# Copyright (c) 1993 - 2025 ARM Limited. All Rights Reserved.
# Use of this Software is subject to the terms and conditions of the
# applicable license agreement with ARM Limited.

# PhyVGen V 11.0.0-beta2
# ARM Version r3p1
# Creation Date: Fri Jan 31 07:31:40 2025


# Memory Configuration:
# ~~~~~~~~~~~~~~~~~~~~~
#  -PG_PINS_domain VDDCE -activity_factor 50 -atf off -back_biasing off
# -bit_blast off -bits 128 -bmux off -check_instname on -diodes on -drive 6
# -ema on -frequency 500 -instname sram128x128 -left_bus_delim "[" -mux 2 -mvt
# BASE -name_case lower -power_gating off -power_type otc -pwr_gnd_rename
# vddpe:VDDPE,vddce:VDDCE,vsse:VSSE -rcols 2 -redundancy off -retention on
# -right_bus_delim "]" -rrows 0 -ser none -single_domain_only on -site_def off
# -top_layer m5-m10 -vmin_assist on -words 128 -wp_size 1 -write_mask off
# -write_thru off -corners
# ffg_cbestt_0p88v_0p88v_0c,ffg_cbestt_0p88v_0p88v_125c,ffg_cbestt_0p88v_0p88v_m40c,ssg_cworstt_0p72v_0p72v_0c,ssg_cworstt_0p72v_0p72v_125c,ssg_cworstt_0p72v_0p72v_m40c,tt_typical_0p80v_0p80v_25c,tt_typical_0p80v_0p80v_85c
# 

VERSION 5.8 ;
BUSBITCHARS "[]" ;
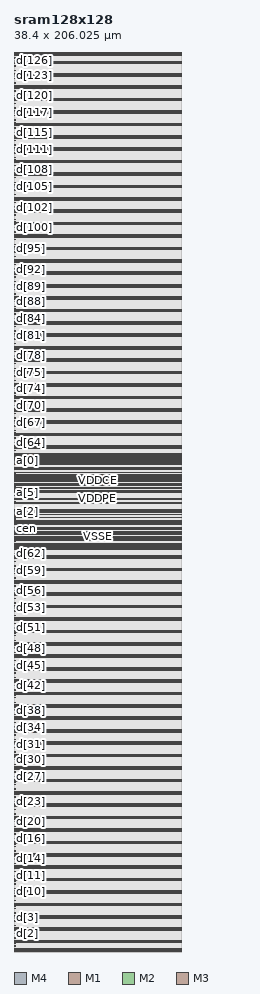
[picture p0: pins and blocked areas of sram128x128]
MACRO sram128x128
	FOREIGN sram128x128 0 0 ;
	SYMMETRY X Y ;
	SIZE 38.4 BY 206.025 ;
	CLASS BLOCK ;
	PIN VDDCE
		USE POWER ;
		DIRECTION INOUT ;
		PORT
			LAYER	M4 ;
			RECT	0 95.965 38.4 96.175 ;
		END

		PORT
			LAYER	M4 ;
			RECT	0 107.815 38.4 108.025 ;
		END

		PORT
			LAYER	M4 ;
			RECT	0 109.675 38.4 109.825 ;
		END

		PORT
			LAYER	M4 ;
			RECT	0 113.28 38.4 113.43 ;
		END

		PORT
			LAYER	M4 ;
			RECT	0 203.575 38.4 203.725 ;
		END

		PORT
			LAYER	M4 ;
			RECT	0 135.415 38.4 135.565 ;
		END

		PORT
			LAYER	M4 ;
			RECT	0 132.575 38.4 132.725 ;
		END

		PORT
			LAYER	M4 ;
			RECT	0 129.735 38.4 129.885 ;
		END

		PORT
			LAYER	M4 ;
			RECT	0 126.895 38.4 127.045 ;
		END

		PORT
			LAYER	M4 ;
			RECT	0 124.055 38.4 124.205 ;
		END

		PORT
			LAYER	M4 ;
			RECT	0 197.895 38.4 198.045 ;
		END

		PORT
			LAYER	M4 ;
			RECT	0 121.215 38.4 121.365 ;
		END

		PORT
			LAYER	M4 ;
			RECT	0 118.375 38.4 118.525 ;
		END

		PORT
			LAYER	M4 ;
			RECT	0 115.535 38.4 115.685 ;
		END

		PORT
			LAYER	M4 ;
			RECT	0 195.055 38.4 195.205 ;
		END

		PORT
			LAYER	M4 ;
			RECT	0 90.34 38.4 90.49 ;
		END

		PORT
			LAYER	M4 ;
			RECT	0 87.5 38.4 87.65 ;
		END

		PORT
			LAYER	M4 ;
			RECT	0 84.66 38.4 84.81 ;
		END

		PORT
			LAYER	M4 ;
			RECT	0 81.82 38.4 81.97 ;
		END

		PORT
			LAYER	M4 ;
			RECT	0 78.98 38.4 79.13 ;
		END

		PORT
			LAYER	M4 ;
			RECT	0 76.14 38.4 76.29 ;
		END

		PORT
			LAYER	M4 ;
			RECT	0 73.3 38.4 73.45 ;
		END

		PORT
			LAYER	M4 ;
			RECT	0 192.215 38.4 192.365 ;
		END

		PORT
			LAYER	M4 ;
			RECT	0 70.46 38.4 70.61 ;
		END

		PORT
			LAYER	M4 ;
			RECT	0 67.62 38.4 67.77 ;
		END

		PORT
			LAYER	M4 ;
			RECT	0 64.78 38.4 64.93 ;
		END

		PORT
			LAYER	M4 ;
			RECT	0 61.94 38.4 62.09 ;
		END

		PORT
			LAYER	M4 ;
			RECT	0 59.1 38.4 59.25 ;
		END

		PORT
			LAYER	M4 ;
			RECT	0 56.26 38.4 56.41 ;
		END

		PORT
			LAYER	M4 ;
			RECT	0 53.42 38.4 53.57 ;
		END

		PORT
			LAYER	M4 ;
			RECT	0 50.58 38.4 50.73 ;
		END

		PORT
			LAYER	M4 ;
			RECT	0 47.74 38.4 47.89 ;
		END

		PORT
			LAYER	M4 ;
			RECT	0 44.9 38.4 45.05 ;
		END

		PORT
			LAYER	M4 ;
			RECT	0 189.375 38.4 189.525 ;
		END

		PORT
			LAYER	M4 ;
			RECT	0 42.06 38.4 42.21 ;
		END

		PORT
			LAYER	M4 ;
			RECT	0 39.22 38.4 39.37 ;
		END

		PORT
			LAYER	M4 ;
			RECT	0 36.38 38.4 36.53 ;
		END

		PORT
			LAYER	M4 ;
			RECT	0 33.54 38.4 33.69 ;
		END

		PORT
			LAYER	M4 ;
			RECT	0 30.7 38.4 30.85 ;
		END

		PORT
			LAYER	M4 ;
			RECT	0 27.86 38.4 28.01 ;
		END

		PORT
			LAYER	M4 ;
			RECT	0 25.02 38.4 25.17 ;
		END

		PORT
			LAYER	M4 ;
			RECT	0 22.18 38.4 22.33 ;
		END

		PORT
			LAYER	M4 ;
			RECT	0 19.34 38.4 19.49 ;
		END

		PORT
			LAYER	M4 ;
			RECT	0 16.5 38.4 16.65 ;
		END

		PORT
			LAYER	M4 ;
			RECT	0 186.535 38.4 186.685 ;
		END

		PORT
			LAYER	M4 ;
			RECT	0 13.66 38.4 13.81 ;
		END

		PORT
			LAYER	M4 ;
			RECT	0 10.82 38.4 10.97 ;
		END

		PORT
			LAYER	M4 ;
			RECT	0 7.98 38.4 8.13 ;
		END

		PORT
			LAYER	M4 ;
			RECT	0 5.14 38.4 5.29 ;
		END

		PORT
			LAYER	M4 ;
			RECT	0 2.3 38.4 2.45 ;
		END

		PORT
			LAYER	M4 ;
			RECT	0 183.695 38.4 183.845 ;
		END

		PORT
			LAYER	M4 ;
			RECT	0 180.855 38.4 181.005 ;
		END

		PORT
			LAYER	M4 ;
			RECT	0 178.015 38.4 178.165 ;
		END

		PORT
			LAYER	M4 ;
			RECT	0 175.175 38.4 175.325 ;
		END

		PORT
			LAYER	M4 ;
			RECT	0 172.335 38.4 172.485 ;
		END

		PORT
			LAYER	M4 ;
			RECT	0 169.495 38.4 169.645 ;
		END

		PORT
			LAYER	M4 ;
			RECT	0 166.655 38.4 166.805 ;
		END

		PORT
			LAYER	M4 ;
			RECT	0 163.815 38.4 163.965 ;
		END

		PORT
			LAYER	M4 ;
			RECT	0 160.975 38.4 161.125 ;
		END

		PORT
			LAYER	M4 ;
			RECT	0 158.135 38.4 158.285 ;
		END

		PORT
			LAYER	M4 ;
			RECT	0 155.295 38.4 155.445 ;
		END

		PORT
			LAYER	M4 ;
			RECT	0 152.455 38.4 152.605 ;
		END

		PORT
			LAYER	M4 ;
			RECT	0 200.735 38.4 200.885 ;
		END

		PORT
			LAYER	M4 ;
			RECT	0 149.615 38.4 149.765 ;
		END

		PORT
			LAYER	M4 ;
			RECT	0 146.775 38.4 146.925 ;
		END

		PORT
			LAYER	M4 ;
			RECT	0 143.935 38.4 144.085 ;
		END

		PORT
			LAYER	M4 ;
			RECT	0 141.095 38.4 141.245 ;
		END

		PORT
			LAYER	M4 ;
			RECT	0 138.255 38.4 138.405 ;
		END

		PORT
			LAYER	M4 ;
			RECT	0 92.235 38.4 92.365 ;
		END

		PORT
			LAYER	M4 ;
			RECT	0 95.665 38.4 95.795 ;
		END

		PORT
			LAYER	M4 ;
			RECT	0 205.205 38.4 205.355 ;
		END

		PORT
			LAYER	M4 ;
			RECT	0 108.195 38.4 108.325 ;
		END

		PORT
			LAYER	M4 ;
			RECT	0 0.67 38.4 0.82 ;
		END

		PORT
			LAYER	M4 ;
			RECT	0 114.07 38.4 114.2 ;
		END

	END VDDCE

	PIN VDDPE
		USE POWER ;
		DIRECTION INOUT ;
		PORT
			LAYER	M4 ;
			RECT	0 94.255 38.4 94.405 ;
		END

		PORT
			LAYER	M4 ;
			RECT	0 94.625 38.4 94.835 ;
		END

		PORT
			LAYER	M4 ;
			RECT	0 98.15 38.4 98.36 ;
		END

		PORT
			LAYER	M4 ;
			RECT	0 98.625 38.4 98.835 ;
		END

		PORT
			LAYER	M4 ;
			RECT	0 100.04 38.4 100.25 ;
		END

		PORT
			LAYER	M4 ;
			RECT	0 101.185 38.4 101.335 ;
		END

		PORT
			LAYER	M4 ;
			RECT	0 103.6 38.4 103.81 ;
		END

		PORT
			LAYER	M4 ;
			RECT	0 105.16 38.4 105.37 ;
		END

		PORT
			LAYER	M4 ;
			RECT	0 106.02 38.4 106.23 ;
		END

		PORT
			LAYER	M4 ;
			RECT	0 109.13 38.4 109.34 ;
		END

		PORT
			LAYER	M4 ;
			RECT	0 112.11 38.4 112.32 ;
		END

		PORT
			LAYER	M4 ;
			RECT	0 112.485 38.4 112.695 ;
		END

		PORT
			LAYER	M4 ;
			RECT	0 203.345 38.4 203.495 ;
		END

		PORT
			LAYER	M4 ;
			RECT	0 135.185 38.4 135.335 ;
		END

		PORT
			LAYER	M4 ;
			RECT	0 132.345 38.4 132.495 ;
		END

		PORT
			LAYER	M4 ;
			RECT	0 129.505 38.4 129.655 ;
		END

		PORT
			LAYER	M4 ;
			RECT	0 126.665 38.4 126.815 ;
		END

		PORT
			LAYER	M4 ;
			RECT	0 123.825 38.4 123.975 ;
		END

		PORT
			LAYER	M4 ;
			RECT	0 120.985 38.4 121.135 ;
		END

		PORT
			LAYER	M4 ;
			RECT	0 118.145 38.4 118.295 ;
		END

		PORT
			LAYER	M4 ;
			RECT	0 115.305 38.4 115.455 ;
		END

		PORT
			LAYER	M4 ;
			RECT	0 197.665 38.4 197.815 ;
		END

		PORT
			LAYER	M4 ;
			RECT	0 194.825 38.4 194.975 ;
		END

		PORT
			LAYER	M4 ;
			RECT	0 90.57 38.4 90.72 ;
		END

		PORT
			LAYER	M4 ;
			RECT	0 87.73 38.4 87.88 ;
		END

		PORT
			LAYER	M4 ;
			RECT	0 84.89 38.4 85.04 ;
		END

		PORT
			LAYER	M4 ;
			RECT	0 82.05 38.4 82.2 ;
		END

		PORT
			LAYER	M4 ;
			RECT	0 79.21 38.4 79.36 ;
		END

		PORT
			LAYER	M4 ;
			RECT	0 76.37 38.4 76.52 ;
		END

		PORT
			LAYER	M4 ;
			RECT	0 73.53 38.4 73.68 ;
		END

		PORT
			LAYER	M4 ;
			RECT	0 70.69 38.4 70.84 ;
		END

		PORT
			LAYER	M4 ;
			RECT	0 67.85 38.4 68 ;
		END

		PORT
			LAYER	M4 ;
			RECT	0 191.985 38.4 192.135 ;
		END

		PORT
			LAYER	M4 ;
			RECT	0 65.01 38.4 65.16 ;
		END

		PORT
			LAYER	M4 ;
			RECT	0 62.17 38.4 62.32 ;
		END

		PORT
			LAYER	M4 ;
			RECT	0 59.33 38.4 59.48 ;
		END

		PORT
			LAYER	M4 ;
			RECT	0 56.49 38.4 56.64 ;
		END

		PORT
			LAYER	M4 ;
			RECT	0 53.65 38.4 53.8 ;
		END

		PORT
			LAYER	M4 ;
			RECT	0 50.81 38.4 50.96 ;
		END

		PORT
			LAYER	M4 ;
			RECT	0 47.97 38.4 48.12 ;
		END

		PORT
			LAYER	M4 ;
			RECT	0 45.13 38.4 45.28 ;
		END

		PORT
			LAYER	M4 ;
			RECT	0 42.29 38.4 42.44 ;
		END

		PORT
			LAYER	M4 ;
			RECT	0 39.45 38.4 39.6 ;
		END

		PORT
			LAYER	M4 ;
			RECT	0 189.145 38.4 189.295 ;
		END

		PORT
			LAYER	M4 ;
			RECT	0 36.61 38.4 36.76 ;
		END

		PORT
			LAYER	M4 ;
			RECT	0 33.77 38.4 33.92 ;
		END

		PORT
			LAYER	M4 ;
			RECT	0 30.93 38.4 31.08 ;
		END

		PORT
			LAYER	M4 ;
			RECT	0 28.09 38.4 28.24 ;
		END

		PORT
			LAYER	M4 ;
			RECT	0 25.25 38.4 25.4 ;
		END

		PORT
			LAYER	M4 ;
			RECT	0 22.41 38.4 22.56 ;
		END

		PORT
			LAYER	M4 ;
			RECT	0 19.57 38.4 19.72 ;
		END

		PORT
			LAYER	M4 ;
			RECT	0 16.73 38.4 16.88 ;
		END

		PORT
			LAYER	M4 ;
			RECT	0 13.89 38.4 14.04 ;
		END

		PORT
			LAYER	M4 ;
			RECT	0 11.05 38.4 11.2 ;
		END

		PORT
			LAYER	M4 ;
			RECT	0 186.305 38.4 186.455 ;
		END

		PORT
			LAYER	M4 ;
			RECT	0 8.21 38.4 8.36 ;
		END

		PORT
			LAYER	M4 ;
			RECT	0 5.37 38.4 5.52 ;
		END

		PORT
			LAYER	M4 ;
			RECT	0 2.53 38.4 2.68 ;
		END

		PORT
			LAYER	M4 ;
			RECT	0 183.465 38.4 183.615 ;
		END

		PORT
			LAYER	M4 ;
			RECT	0 180.625 38.4 180.775 ;
		END

		PORT
			LAYER	M4 ;
			RECT	0 177.785 38.4 177.935 ;
		END

		PORT
			LAYER	M4 ;
			RECT	0 174.945 38.4 175.095 ;
		END

		PORT
			LAYER	M4 ;
			RECT	0 172.105 38.4 172.255 ;
		END

		PORT
			LAYER	M4 ;
			RECT	0 169.265 38.4 169.415 ;
		END

		PORT
			LAYER	M4 ;
			RECT	0 166.425 38.4 166.575 ;
		END

		PORT
			LAYER	M4 ;
			RECT	0 163.585 38.4 163.735 ;
		END

		PORT
			LAYER	M4 ;
			RECT	0 160.745 38.4 160.895 ;
		END

		PORT
			LAYER	M4 ;
			RECT	0 157.905 38.4 158.055 ;
		END

		PORT
			LAYER	M4 ;
			RECT	0 155.065 38.4 155.215 ;
		END

		PORT
			LAYER	M4 ;
			RECT	0 152.225 38.4 152.375 ;
		END

		PORT
			LAYER	M4 ;
			RECT	0 149.385 38.4 149.535 ;
		END

		PORT
			LAYER	M4 ;
			RECT	0 146.545 38.4 146.695 ;
		END

		PORT
			LAYER	M4 ;
			RECT	0 143.705 38.4 143.855 ;
		END

		PORT
			LAYER	M4 ;
			RECT	0 200.505 38.4 200.655 ;
		END

		PORT
			LAYER	M4 ;
			RECT	0 140.865 38.4 141.015 ;
		END

		PORT
			LAYER	M4 ;
			RECT	0 138.025 38.4 138.175 ;
		END

		PORT
			LAYER	M4 ;
			RECT	0 205.705 38.4 205.855 ;
		END

		PORT
			LAYER	M4 ;
			RECT	0 92.655 38.4 92.785 ;
		END

		PORT
			LAYER	M4 ;
			RECT	0 97.125 38.4 97.255 ;
		END

		PORT
			LAYER	M4 ;
			RECT	0 0.17 38.4 0.32 ;
		END

		PORT
			LAYER	M4 ;
			RECT	0 105.5 38.4 105.63 ;
		END

		PORT
			LAYER	M4 ;
			RECT	0 113.65 38.4 113.78 ;
		END

	END VDDPE

	PIN VSSE
		USE GROUND ;
		DIRECTION INOUT ;
		PORT
			LAYER	M4 ;
			RECT	0 92.445 38.4 92.575 ;
		END

		PORT
			LAYER	M4 ;
			RECT	0 205.455 38.4 205.605 ;
		END

		PORT
			LAYER	M4 ;
			RECT	0 99.425 38.4 99.555 ;
		END

		PORT
			LAYER	M4 ;
			RECT	0 0.42 38.4 0.57 ;
		END

		PORT
			LAYER	M4 ;
			RECT	0 106.69 38.4 106.82 ;
		END

		PORT
			LAYER	M4 ;
			RECT	0 110.885 38.4 111.015 ;
		END

		PORT
			LAYER	M4 ;
			RECT	0 113.86 38.4 113.99 ;
		END

		PORT
			LAYER	M4 ;
			RECT	0 92.98 38.4 93.11 ;
		END

		PORT
			LAYER	M4 ;
			RECT	0 93.39 38.4 93.6 ;
		END

		PORT
			LAYER	M4 ;
			RECT	0 94.97 38.4 95.18 ;
		END

		PORT
			LAYER	M4 ;
			RECT	0 96.76 38.4 96.91 ;
		END

		PORT
			LAYER	M4 ;
			RECT	0 97.865 38.4 98.015 ;
		END

		PORT
			LAYER	M4 ;
			RECT	0 100.575 38.4 100.725 ;
		END

		PORT
			LAYER	M4 ;
			RECT	0 100.915 38.4 101.065 ;
		END

		PORT
			LAYER	M4 ;
			RECT	0 102.63 38.4 102.84 ;
		END

		PORT
			LAYER	M4 ;
			RECT	0 107.05 38.4 107.26 ;
		END

		PORT
			LAYER	M4 ;
			RECT	0 108.655 38.4 108.865 ;
		END

		PORT
			LAYER	M4 ;
			RECT	0 110.395 38.4 110.605 ;
		END

		PORT
			LAYER	M4 ;
			RECT	0 111.59 38.4 111.8 ;
		END

		PORT
			LAYER	M4 ;
			RECT	0 112.955 38.4 113.165 ;
		END

		PORT
			LAYER	M4 ;
			RECT	0 203.805 38.4 203.955 ;
		END

		PORT
			LAYER	M4 ;
			RECT	0 132.805 38.4 132.955 ;
		END

		PORT
			LAYER	M4 ;
			RECT	0 129.965 38.4 130.115 ;
		END

		PORT
			LAYER	M4 ;
			RECT	0 198.125 38.4 198.275 ;
		END

		PORT
			LAYER	M4 ;
			RECT	0 127.125 38.4 127.275 ;
		END

		PORT
			LAYER	M4 ;
			RECT	0 124.285 38.4 124.435 ;
		END

		PORT
			LAYER	M4 ;
			RECT	0 121.445 38.4 121.595 ;
		END

		PORT
			LAYER	M4 ;
			RECT	0 118.605 38.4 118.755 ;
		END

		PORT
			LAYER	M4 ;
			RECT	0 115.765 38.4 115.915 ;
		END

		PORT
			LAYER	M4 ;
			RECT	0 195.285 38.4 195.435 ;
		END

		PORT
			LAYER	M4 ;
			RECT	0 90.11 38.4 90.26 ;
		END

		PORT
			LAYER	M4 ;
			RECT	0 87.27 38.4 87.42 ;
		END

		PORT
			LAYER	M4 ;
			RECT	0 84.43 38.4 84.58 ;
		END

		PORT
			LAYER	M4 ;
			RECT	0 81.59 38.4 81.74 ;
		END

		PORT
			LAYER	M4 ;
			RECT	0 192.445 38.4 192.595 ;
		END

		PORT
			LAYER	M4 ;
			RECT	0 78.75 38.4 78.9 ;
		END

		PORT
			LAYER	M4 ;
			RECT	0 75.91 38.4 76.06 ;
		END

		PORT
			LAYER	M4 ;
			RECT	0 73.07 38.4 73.22 ;
		END

		PORT
			LAYER	M4 ;
			RECT	0 70.23 38.4 70.38 ;
		END

		PORT
			LAYER	M4 ;
			RECT	0 67.39 38.4 67.54 ;
		END

		PORT
			LAYER	M4 ;
			RECT	0 64.55 38.4 64.7 ;
		END

		PORT
			LAYER	M4 ;
			RECT	0 61.71 38.4 61.86 ;
		END

		PORT
			LAYER	M4 ;
			RECT	0 58.87 38.4 59.02 ;
		END

		PORT
			LAYER	M4 ;
			RECT	0 56.03 38.4 56.18 ;
		END

		PORT
			LAYER	M4 ;
			RECT	0 53.19 38.4 53.34 ;
		END

		PORT
			LAYER	M4 ;
			RECT	0 189.605 38.4 189.755 ;
		END

		PORT
			LAYER	M4 ;
			RECT	0 50.35 38.4 50.5 ;
		END

		PORT
			LAYER	M4 ;
			RECT	0 47.51 38.4 47.66 ;
		END

		PORT
			LAYER	M4 ;
			RECT	0 44.67 38.4 44.82 ;
		END

		PORT
			LAYER	M4 ;
			RECT	0 41.83 38.4 41.98 ;
		END

		PORT
			LAYER	M4 ;
			RECT	0 38.99 38.4 39.14 ;
		END

		PORT
			LAYER	M4 ;
			RECT	0 36.15 38.4 36.3 ;
		END

		PORT
			LAYER	M4 ;
			RECT	0 33.31 38.4 33.46 ;
		END

		PORT
			LAYER	M4 ;
			RECT	0 30.47 38.4 30.62 ;
		END

		PORT
			LAYER	M4 ;
			RECT	0 27.63 38.4 27.78 ;
		END

		PORT
			LAYER	M4 ;
			RECT	0 24.79 38.4 24.94 ;
		END

		PORT
			LAYER	M4 ;
			RECT	0 186.765 38.4 186.915 ;
		END

		PORT
			LAYER	M4 ;
			RECT	0 21.95 38.4 22.1 ;
		END

		PORT
			LAYER	M4 ;
			RECT	0 19.11 38.4 19.26 ;
		END

		PORT
			LAYER	M4 ;
			RECT	0 16.27 38.4 16.42 ;
		END

		PORT
			LAYER	M4 ;
			RECT	0 13.43 38.4 13.58 ;
		END

		PORT
			LAYER	M4 ;
			RECT	0 10.59 38.4 10.74 ;
		END

		PORT
			LAYER	M4 ;
			RECT	0 7.75 38.4 7.9 ;
		END

		PORT
			LAYER	M4 ;
			RECT	0 4.91 38.4 5.06 ;
		END

		PORT
			LAYER	M4 ;
			RECT	0 2.07 38.4 2.22 ;
		END

		PORT
			LAYER	M4 ;
			RECT	0 183.925 38.4 184.075 ;
		END

		PORT
			LAYER	M4 ;
			RECT	0 181.085 38.4 181.235 ;
		END

		PORT
			LAYER	M4 ;
			RECT	0 178.245 38.4 178.395 ;
		END

		PORT
			LAYER	M4 ;
			RECT	0 175.405 38.4 175.555 ;
		END

		PORT
			LAYER	M4 ;
			RECT	0 172.565 38.4 172.715 ;
		END

		PORT
			LAYER	M4 ;
			RECT	0 169.725 38.4 169.875 ;
		END

		PORT
			LAYER	M4 ;
			RECT	0 166.885 38.4 167.035 ;
		END

		PORT
			LAYER	M4 ;
			RECT	0 164.045 38.4 164.195 ;
		END

		PORT
			LAYER	M4 ;
			RECT	0 161.205 38.4 161.355 ;
		END

		PORT
			LAYER	M4 ;
			RECT	0 158.365 38.4 158.515 ;
		END

		PORT
			LAYER	M4 ;
			RECT	0 200.965 38.4 201.115 ;
		END

		PORT
			LAYER	M4 ;
			RECT	0 155.525 38.4 155.675 ;
		END

		PORT
			LAYER	M4 ;
			RECT	0 152.685 38.4 152.835 ;
		END

		PORT
			LAYER	M4 ;
			RECT	0 149.845 38.4 149.995 ;
		END

		PORT
			LAYER	M4 ;
			RECT	0 147.005 38.4 147.155 ;
		END

		PORT
			LAYER	M4 ;
			RECT	0 144.165 38.4 144.315 ;
		END

		PORT
			LAYER	M4 ;
			RECT	0 141.325 38.4 141.475 ;
		END

		PORT
			LAYER	M4 ;
			RECT	0 138.485 38.4 138.635 ;
		END

		PORT
			LAYER	M4 ;
			RECT	0 135.645 38.4 135.795 ;
		END

	END VSSE

	PIN a[0]
		USE SIGNAL ;
		DIRECTION INPUT ;
		SHAPE ABUTMENT ;
		PORT
			LAYER	M1 ;
			RECT	0 112.385 0.25 112.485 ;
			LAYER	M2 ;
			RECT	0 112.385 0.25 112.485 ;
			LAYER	M3 ;
			RECT	0 112.385 0.25 112.485 ;
		END

		ANTENNAGATEAREA 0.014 ;
		ANTENNADIFFAREA 0.018 ;
		ANTENNAPARTIALMETALAREA 0.025 ;
	END a[0]

	PIN a[1]
		USE SIGNAL ;
		DIRECTION INPUT ;
		SHAPE ABUTMENT ;
		PORT
			LAYER	M1 ;
			RECT	0 100.49 0.25 100.59 ;
			LAYER	M2 ;
			RECT	0 100.49 0.25 100.59 ;
			LAYER	M3 ;
			RECT	0 100.49 0.25 100.59 ;
		END

		ANTENNAGATEAREA 0.014 ;
		ANTENNADIFFAREA 0.018 ;
		ANTENNAPARTIALMETALAREA 0.025 ;
	END a[1]

	PIN a[2]
		USE SIGNAL ;
		DIRECTION INPUT ;
		SHAPE ABUTMENT ;
		PORT
			LAYER	M1 ;
			RECT	0 100.89 0.25 100.99 ;
			LAYER	M2 ;
			RECT	0 100.89 0.25 100.99 ;
			LAYER	M3 ;
			RECT	0 100.89 0.25 100.99 ;
		END

		ANTENNAGATEAREA 0.014 ;
		ANTENNADIFFAREA 0.018 ;
		ANTENNAPARTIALMETALAREA 0.025 ;
	END a[2]

	PIN a[3]
		USE SIGNAL ;
		DIRECTION INPUT ;
		SHAPE ABUTMENT ;
		PORT
			LAYER	M1 ;
			RECT	0 102.8 0.25 102.9 ;
			LAYER	M2 ;
			RECT	0 102.8 0.25 102.9 ;
			LAYER	M3 ;
			RECT	0 102.8 0.25 102.9 ;
		END

		ANTENNAGATEAREA 0.014 ;
		ANTENNADIFFAREA 0.018 ;
		ANTENNAPARTIALMETALAREA 0.025 ;
	END a[3]

	PIN a[4]
		USE SIGNAL ;
		DIRECTION INPUT ;
		SHAPE ABUTMENT ;
		PORT
			LAYER	M1 ;
			RECT	0 103.13 0.25 103.23 ;
			LAYER	M2 ;
			RECT	0 103.13 0.25 103.23 ;
			LAYER	M3 ;
			RECT	0 103.13 0.25 103.23 ;
		END

		ANTENNAGATEAREA 0.014 ;
		ANTENNADIFFAREA 0.018 ;
		ANTENNAPARTIALMETALAREA 0.025 ;
	END a[4]

	PIN a[5]
		USE SIGNAL ;
		DIRECTION INPUT ;
		SHAPE ABUTMENT ;
		PORT
			LAYER	M1 ;
			RECT	0 105.235 0.25 105.335 ;
			LAYER	M2 ;
			RECT	0 105.235 0.25 105.335 ;
			LAYER	M3 ;
			RECT	0 105.235 0.25 105.335 ;
		END

		ANTENNAGATEAREA 0.014 ;
		ANTENNADIFFAREA 0.018 ;
		ANTENNAPARTIALMETALAREA 0.025 ;
	END a[5]

	PIN a[6]
		USE SIGNAL ;
		DIRECTION INPUT ;
		SHAPE ABUTMENT ;
		PORT
			LAYER	M1 ;
			RECT	0 106.505 0.25 106.605 ;
			LAYER	M2 ;
			RECT	0 106.505 0.25 106.605 ;
			LAYER	M3 ;
			RECT	0 106.505 0.25 106.605 ;
		END

		ANTENNAGATEAREA 0.014 ;
		ANTENNADIFFAREA 0.018 ;
		ANTENNAPARTIALMETALAREA 0.025 ;
	END a[6]

	PIN cen
		USE SIGNAL ;
		DIRECTION INPUT ;
		SHAPE ABUTMENT ;
		PORT
			LAYER	M1 ;
			RECT	0 96.9 0.25 97 ;
			LAYER	M2 ;
			RECT	0 96.9 0.25 97 ;
			LAYER	M3 ;
			RECT	0 96.9 0.25 97 ;
		END

		ANTENNAGATEAREA 0.014 ;
		ANTENNADIFFAREA 0.018 ;
		ANTENNAPARTIALMETALAREA 0.025 ;
	END cen

	PIN clk
		USE SIGNAL ;
		DIRECTION INPUT ;
		SHAPE ABUTMENT ;
		PORT
			LAYER	M1 ;
			RECT	0 96.51 0.25 96.61 ;
			LAYER	M2 ;
			RECT	0 96.51 0.25 96.61 ;
			LAYER	M3 ;
			RECT	0 96.51 0.25 96.61 ;
			LAYER	M4 ;
			RECT	0 96.51 0.25 96.61 ;
		END

		ANTENNAGATEAREA 0.014 ;
		ANTENNADIFFAREA 0.018 ;
		ANTENNAPARTIALMETALAREA 0.025 ;
	END clk

	PIN d[0]
		USE SIGNAL ;
		DIRECTION INPUT ;
		SHAPE ABUTMENT ;
		PORT
			LAYER	M1 ;
			RECT	0 1.365 0.25 1.465 ;
			LAYER	M2 ;
			RECT	0 1.365 0.25 1.465 ;
			LAYER	M3 ;
			RECT	0 1.365 0.25 1.465 ;
		END

		ANTENNAGATEAREA 0.014 ;
		ANTENNADIFFAREA 0.018 ;
		ANTENNAPARTIALMETALAREA 0.025 ;
	END d[0]

	PIN d[100]
		USE SIGNAL ;
		DIRECTION INPUT ;
		SHAPE ABUTMENT ;
		PORT
			LAYER	M1 ;
			RECT	0 165.85 0.25 165.95 ;
			LAYER	M2 ;
			RECT	0 165.85 0.25 165.95 ;
			LAYER	M3 ;
			RECT	0 165.85 0.25 165.95 ;
		END

		ANTENNAGATEAREA 0.014 ;
		ANTENNADIFFAREA 0.018 ;
		ANTENNAPARTIALMETALAREA 0.025 ;
	END d[100]

	PIN d[101]
		USE SIGNAL ;
		DIRECTION INPUT ;
		SHAPE ABUTMENT ;
		PORT
			LAYER	M1 ;
			RECT	0 167.64 0.25 167.74 ;
			LAYER	M2 ;
			RECT	0 167.64 0.25 167.74 ;
			LAYER	M3 ;
			RECT	0 167.64 0.25 167.74 ;
		END

		ANTENNAGATEAREA 0.014 ;
		ANTENNADIFFAREA 0.018 ;
		ANTENNAPARTIALMETALAREA 0.025 ;
	END d[101]

	PIN d[102]
		USE SIGNAL ;
		DIRECTION INPUT ;
		SHAPE ABUTMENT ;
		PORT
			LAYER	M1 ;
			RECT	0 168.69 0.25 168.79 ;
			LAYER	M2 ;
			RECT	0 168.69 0.25 168.79 ;
			LAYER	M3 ;
			RECT	0 168.69 0.25 168.79 ;
		END

		ANTENNAGATEAREA 0.014 ;
		ANTENNADIFFAREA 0.018 ;
		ANTENNAPARTIALMETALAREA 0.025 ;
	END d[102]

	PIN d[103]
		USE SIGNAL ;
		DIRECTION INPUT ;
		SHAPE ABUTMENT ;
		PORT
			LAYER	M1 ;
			RECT	0 170.48 0.25 170.58 ;
			LAYER	M2 ;
			RECT	0 170.48 0.25 170.58 ;
			LAYER	M3 ;
			RECT	0 170.48 0.25 170.58 ;
		END

		ANTENNAGATEAREA 0.014 ;
		ANTENNADIFFAREA 0.018 ;
		ANTENNAPARTIALMETALAREA 0.025 ;
	END d[103]

	PIN d[104]
		USE SIGNAL ;
		DIRECTION INPUT ;
		SHAPE ABUTMENT ;
		PORT
			LAYER	M1 ;
			RECT	0 171.53 0.25 171.63 ;
			LAYER	M2 ;
			RECT	0 171.53 0.25 171.63 ;
			LAYER	M3 ;
			RECT	0 171.53 0.25 171.63 ;
		END

		ANTENNAGATEAREA 0.014 ;
		ANTENNADIFFAREA 0.018 ;
		ANTENNAPARTIALMETALAREA 0.025 ;
	END d[104]

	PIN d[105]
		USE SIGNAL ;
		DIRECTION INPUT ;
		SHAPE ABUTMENT ;
		PORT
			LAYER	M1 ;
			RECT	0 173.32 0.25 173.42 ;
			LAYER	M2 ;
			RECT	0 173.32 0.25 173.42 ;
			LAYER	M3 ;
			RECT	0 173.32 0.25 173.42 ;
		END

		ANTENNAGATEAREA 0.014 ;
		ANTENNADIFFAREA 0.018 ;
		ANTENNAPARTIALMETALAREA 0.025 ;
	END d[105]

	PIN d[106]
		USE SIGNAL ;
		DIRECTION INPUT ;
		SHAPE ABUTMENT ;
		PORT
			LAYER	M1 ;
			RECT	0 174.37 0.25 174.47 ;
			LAYER	M2 ;
			RECT	0 174.37 0.25 174.47 ;
			LAYER	M3 ;
			RECT	0 174.37 0.25 174.47 ;
		END

		ANTENNAGATEAREA 0.014 ;
		ANTENNADIFFAREA 0.018 ;
		ANTENNAPARTIALMETALAREA 0.025 ;
	END d[106]

	PIN d[107]
		USE SIGNAL ;
		DIRECTION INPUT ;
		SHAPE ABUTMENT ;
		PORT
			LAYER	M1 ;
			RECT	0 176.16 0.25 176.26 ;
			LAYER	M2 ;
			RECT	0 176.16 0.25 176.26 ;
			LAYER	M3 ;
			RECT	0 176.16 0.25 176.26 ;
		END

		ANTENNAGATEAREA 0.014 ;
		ANTENNADIFFAREA 0.018 ;
		ANTENNAPARTIALMETALAREA 0.025 ;
	END d[107]

	PIN d[108]
		USE SIGNAL ;
		DIRECTION INPUT ;
		SHAPE ABUTMENT ;
		PORT
			LAYER	M1 ;
			RECT	0 177.21 0.25 177.31 ;
			LAYER	M2 ;
			RECT	0 177.21 0.25 177.31 ;
			LAYER	M3 ;
			RECT	0 177.21 0.25 177.31 ;
		END

		ANTENNAGATEAREA 0.014 ;
		ANTENNADIFFAREA 0.018 ;
		ANTENNAPARTIALMETALAREA 0.025 ;
	END d[108]

	PIN d[109]
		USE SIGNAL ;
		DIRECTION INPUT ;
		SHAPE ABUTMENT ;
		PORT
			LAYER	M1 ;
			RECT	0 179 0.25 179.1 ;
			LAYER	M2 ;
			RECT	0 179 0.25 179.1 ;
			LAYER	M3 ;
			RECT	0 179 0.25 179.1 ;
		END

		ANTENNAGATEAREA 0.014 ;
		ANTENNADIFFAREA 0.018 ;
		ANTENNAPARTIALMETALAREA 0.025 ;
	END d[109]

	PIN d[10]
		USE SIGNAL ;
		DIRECTION INPUT ;
		SHAPE ABUTMENT ;
		PORT
			LAYER	M1 ;
			RECT	0 15.565 0.25 15.665 ;
			LAYER	M2 ;
			RECT	0 15.565 0.25 15.665 ;
			LAYER	M3 ;
			RECT	0 15.565 0.25 15.665 ;
		END

		ANTENNAGATEAREA 0.014 ;
		ANTENNADIFFAREA 0.018 ;
		ANTENNAPARTIALMETALAREA 0.025 ;
	END d[10]

	PIN d[110]
		USE SIGNAL ;
		DIRECTION INPUT ;
		SHAPE ABUTMENT ;
		PORT
			LAYER	M1 ;
			RECT	0 180.05 0.25 180.15 ;
			LAYER	M2 ;
			RECT	0 180.05 0.25 180.15 ;
			LAYER	M3 ;
			RECT	0 180.05 0.25 180.15 ;
		END

		ANTENNAGATEAREA 0.014 ;
		ANTENNADIFFAREA 0.018 ;
		ANTENNAPARTIALMETALAREA 0.025 ;
	END d[110]

	PIN d[111]
		USE SIGNAL ;
		DIRECTION INPUT ;
		SHAPE ABUTMENT ;
		PORT
			LAYER	M1 ;
			RECT	0 181.84 0.25 181.94 ;
			LAYER	M2 ;
			RECT	0 181.84 0.25 181.94 ;
			LAYER	M3 ;
			RECT	0 181.84 0.25 181.94 ;
		END

		ANTENNAGATEAREA 0.014 ;
		ANTENNADIFFAREA 0.018 ;
		ANTENNAPARTIALMETALAREA 0.025 ;
	END d[111]

	PIN d[112]
		USE SIGNAL ;
		DIRECTION INPUT ;
		SHAPE ABUTMENT ;
		PORT
			LAYER	M1 ;
			RECT	0 182.89 0.25 182.99 ;
			LAYER	M2 ;
			RECT	0 182.89 0.25 182.99 ;
			LAYER	M3 ;
			RECT	0 182.89 0.25 182.99 ;
		END

		ANTENNAGATEAREA 0.014 ;
		ANTENNADIFFAREA 0.018 ;
		ANTENNAPARTIALMETALAREA 0.025 ;
	END d[112]

	PIN d[113]
		USE SIGNAL ;
		DIRECTION INPUT ;
		SHAPE ABUTMENT ;
		PORT
			LAYER	M1 ;
			RECT	0 184.68 0.25 184.78 ;
			LAYER	M2 ;
			RECT	0 184.68 0.25 184.78 ;
			LAYER	M3 ;
			RECT	0 184.68 0.25 184.78 ;
		END

		ANTENNAGATEAREA 0.014 ;
		ANTENNADIFFAREA 0.018 ;
		ANTENNAPARTIALMETALAREA 0.025 ;
	END d[113]

	PIN d[114]
		USE SIGNAL ;
		DIRECTION INPUT ;
		SHAPE ABUTMENT ;
		PORT
			LAYER	M1 ;
			RECT	0 185.73 0.25 185.83 ;
			LAYER	M2 ;
			RECT	0 185.73 0.25 185.83 ;
			LAYER	M3 ;
			RECT	0 185.73 0.25 185.83 ;
		END

		ANTENNAGATEAREA 0.014 ;
		ANTENNADIFFAREA 0.018 ;
		ANTENNAPARTIALMETALAREA 0.025 ;
	END d[114]

	PIN d[115]
		USE SIGNAL ;
		DIRECTION INPUT ;
		SHAPE ABUTMENT ;
		PORT
			LAYER	M1 ;
			RECT	0 187.52 0.25 187.62 ;
			LAYER	M2 ;
			RECT	0 187.52 0.25 187.62 ;
			LAYER	M3 ;
			RECT	0 187.52 0.25 187.62 ;
		END

		ANTENNAGATEAREA 0.014 ;
		ANTENNADIFFAREA 0.018 ;
		ANTENNAPARTIALMETALAREA 0.025 ;
	END d[115]

	PIN d[116]
		USE SIGNAL ;
		DIRECTION INPUT ;
		SHAPE ABUTMENT ;
		PORT
			LAYER	M1 ;
			RECT	0 188.57 0.25 188.67 ;
			LAYER	M2 ;
			RECT	0 188.57 0.25 188.67 ;
			LAYER	M3 ;
			RECT	0 188.57 0.25 188.67 ;
		END

		ANTENNAGATEAREA 0.014 ;
		ANTENNADIFFAREA 0.018 ;
		ANTENNAPARTIALMETALAREA 0.025 ;
	END d[116]

	PIN d[117]
		USE SIGNAL ;
		DIRECTION INPUT ;
		SHAPE ABUTMENT ;
		PORT
			LAYER	M1 ;
			RECT	0 190.36 0.25 190.46 ;
			LAYER	M2 ;
			RECT	0 190.36 0.25 190.46 ;
			LAYER	M3 ;
			RECT	0 190.36 0.25 190.46 ;
		END

		ANTENNAGATEAREA 0.014 ;
		ANTENNADIFFAREA 0.018 ;
		ANTENNAPARTIALMETALAREA 0.025 ;
	END d[117]

	PIN d[118]
		USE SIGNAL ;
		DIRECTION INPUT ;
		SHAPE ABUTMENT ;
		PORT
			LAYER	M1 ;
			RECT	0 191.41 0.25 191.51 ;
			LAYER	M2 ;
			RECT	0 191.41 0.25 191.51 ;
			LAYER	M3 ;
			RECT	0 191.41 0.25 191.51 ;
		END

		ANTENNAGATEAREA 0.014 ;
		ANTENNADIFFAREA 0.018 ;
		ANTENNAPARTIALMETALAREA 0.025 ;
	END d[118]

	PIN d[119]
		USE SIGNAL ;
		DIRECTION INPUT ;
		SHAPE ABUTMENT ;
		PORT
			LAYER	M1 ;
			RECT	0 193.2 0.25 193.3 ;
			LAYER	M2 ;
			RECT	0 193.2 0.25 193.3 ;
			LAYER	M3 ;
			RECT	0 193.2 0.25 193.3 ;
		END

		ANTENNAGATEAREA 0.014 ;
		ANTENNADIFFAREA 0.018 ;
		ANTENNAPARTIALMETALAREA 0.025 ;
	END d[119]

	PIN d[11]
		USE SIGNAL ;
		DIRECTION INPUT ;
		SHAPE ABUTMENT ;
		PORT
			LAYER	M1 ;
			RECT	0 17.355 0.25 17.455 ;
			LAYER	M2 ;
			RECT	0 17.355 0.25 17.455 ;
			LAYER	M3 ;
			RECT	0 17.355 0.25 17.455 ;
		END

		ANTENNAGATEAREA 0.014 ;
		ANTENNADIFFAREA 0.018 ;
		ANTENNAPARTIALMETALAREA 0.025 ;
	END d[11]

	PIN d[120]
		USE SIGNAL ;
		DIRECTION INPUT ;
		SHAPE ABUTMENT ;
		PORT
			LAYER	M1 ;
			RECT	0 194.25 0.25 194.35 ;
			LAYER	M2 ;
			RECT	0 194.25 0.25 194.35 ;
			LAYER	M3 ;
			RECT	0 194.25 0.25 194.35 ;
		END

		ANTENNAGATEAREA 0.014 ;
		ANTENNADIFFAREA 0.018 ;
		ANTENNAPARTIALMETALAREA 0.025 ;
	END d[120]

	PIN d[121]
		USE SIGNAL ;
		DIRECTION INPUT ;
		SHAPE ABUTMENT ;
		PORT
			LAYER	M1 ;
			RECT	0 196.04 0.25 196.14 ;
			LAYER	M2 ;
			RECT	0 196.04 0.25 196.14 ;
			LAYER	M3 ;
			RECT	0 196.04 0.25 196.14 ;
		END

		ANTENNAGATEAREA 0.014 ;
		ANTENNADIFFAREA 0.018 ;
		ANTENNAPARTIALMETALAREA 0.025 ;
	END d[121]

	PIN d[122]
		USE SIGNAL ;
		DIRECTION INPUT ;
		SHAPE ABUTMENT ;
		PORT
			LAYER	M1 ;
			RECT	0 197.09 0.25 197.19 ;
			LAYER	M2 ;
			RECT	0 197.09 0.25 197.19 ;
			LAYER	M3 ;
			RECT	0 197.09 0.25 197.19 ;
		END

		ANTENNAGATEAREA 0.014 ;
		ANTENNADIFFAREA 0.018 ;
		ANTENNAPARTIALMETALAREA 0.025 ;
	END d[122]

	PIN d[123]
		USE SIGNAL ;
		DIRECTION INPUT ;
		SHAPE ABUTMENT ;
		PORT
			LAYER	M1 ;
			RECT	0 198.88 0.25 198.98 ;
			LAYER	M2 ;
			RECT	0 198.88 0.25 198.98 ;
			LAYER	M3 ;
			RECT	0 198.88 0.25 198.98 ;
		END

		ANTENNAGATEAREA 0.014 ;
		ANTENNADIFFAREA 0.018 ;
		ANTENNAPARTIALMETALAREA 0.025 ;
	END d[123]

	PIN d[124]
		USE SIGNAL ;
		DIRECTION INPUT ;
		SHAPE ABUTMENT ;
		PORT
			LAYER	M1 ;
			RECT	0 199.93 0.25 200.03 ;
			LAYER	M2 ;
			RECT	0 199.93 0.25 200.03 ;
			LAYER	M3 ;
			RECT	0 199.93 0.25 200.03 ;
		END

		ANTENNAGATEAREA 0.014 ;
		ANTENNADIFFAREA 0.018 ;
		ANTENNAPARTIALMETALAREA 0.025 ;
	END d[124]

	PIN d[125]
		USE SIGNAL ;
		DIRECTION INPUT ;
		SHAPE ABUTMENT ;
		PORT
			LAYER	M1 ;
			RECT	0 201.72 0.25 201.82 ;
			LAYER	M2 ;
			RECT	0 201.72 0.25 201.82 ;
			LAYER	M3 ;
			RECT	0 201.72 0.25 201.82 ;
		END

		ANTENNAGATEAREA 0.014 ;
		ANTENNADIFFAREA 0.018 ;
		ANTENNAPARTIALMETALAREA 0.025 ;
	END d[125]

	PIN d[126]
		USE SIGNAL ;
		DIRECTION INPUT ;
		SHAPE ABUTMENT ;
		PORT
			LAYER	M1 ;
			RECT	0 202.77 0.25 202.87 ;
			LAYER	M2 ;
			RECT	0 202.77 0.25 202.87 ;
			LAYER	M3 ;
			RECT	0 202.77 0.25 202.87 ;
		END

		ANTENNAGATEAREA 0.014 ;
		ANTENNADIFFAREA 0.018 ;
		ANTENNAPARTIALMETALAREA 0.025 ;
	END d[126]

	PIN d[127]
		USE SIGNAL ;
		DIRECTION INPUT ;
		SHAPE ABUTMENT ;
		PORT
			LAYER	M1 ;
			RECT	0 204.56 0.25 204.66 ;
			LAYER	M2 ;
			RECT	0 204.56 0.25 204.66 ;
			LAYER	M3 ;
			RECT	0 204.56 0.25 204.66 ;
		END

		ANTENNAGATEAREA 0.014 ;
		ANTENNADIFFAREA 0.018 ;
		ANTENNAPARTIALMETALAREA 0.025 ;
	END d[127]

	PIN d[12]
		USE SIGNAL ;
		DIRECTION INPUT ;
		SHAPE ABUTMENT ;
		PORT
			LAYER	M1 ;
			RECT	0 18.405 0.25 18.505 ;
			LAYER	M2 ;
			RECT	0 18.405 0.25 18.505 ;
			LAYER	M3 ;
			RECT	0 18.405 0.25 18.505 ;
		END

		ANTENNAGATEAREA 0.014 ;
		ANTENNADIFFAREA 0.018 ;
		ANTENNAPARTIALMETALAREA 0.025 ;
	END d[12]

	PIN d[13]
		USE SIGNAL ;
		DIRECTION INPUT ;
		SHAPE ABUTMENT ;
		PORT
			LAYER	M1 ;
			RECT	0 20.195 0.25 20.295 ;
			LAYER	M2 ;
			RECT	0 20.195 0.25 20.295 ;
			LAYER	M3 ;
			RECT	0 20.195 0.25 20.295 ;
		END

		ANTENNAGATEAREA 0.014 ;
		ANTENNADIFFAREA 0.018 ;
		ANTENNAPARTIALMETALAREA 0.025 ;
	END d[13]

	PIN d[14]
		USE SIGNAL ;
		DIRECTION INPUT ;
		SHAPE ABUTMENT ;
		PORT
			LAYER	M1 ;
			RECT	0 21.245 0.25 21.345 ;
			LAYER	M2 ;
			RECT	0 21.245 0.25 21.345 ;
			LAYER	M3 ;
			RECT	0 21.245 0.25 21.345 ;
		END

		ANTENNAGATEAREA 0.014 ;
		ANTENNADIFFAREA 0.018 ;
		ANTENNAPARTIALMETALAREA 0.025 ;
	END d[14]

	PIN d[15]
		USE SIGNAL ;
		DIRECTION INPUT ;
		SHAPE ABUTMENT ;
		PORT
			LAYER	M1 ;
			RECT	0 23.035 0.25 23.135 ;
			LAYER	M2 ;
			RECT	0 23.035 0.25 23.135 ;
			LAYER	M3 ;
			RECT	0 23.035 0.25 23.135 ;
		END

		ANTENNAGATEAREA 0.014 ;
		ANTENNADIFFAREA 0.018 ;
		ANTENNAPARTIALMETALAREA 0.025 ;
	END d[15]

	PIN d[16]
		USE SIGNAL ;
		DIRECTION INPUT ;
		SHAPE ABUTMENT ;
		PORT
			LAYER	M1 ;
			RECT	0 24.085 0.25 24.185 ;
			LAYER	M2 ;
			RECT	0 24.085 0.25 24.185 ;
			LAYER	M3 ;
			RECT	0 24.085 0.25 24.185 ;
		END

		ANTENNAGATEAREA 0.014 ;
		ANTENNADIFFAREA 0.018 ;
		ANTENNAPARTIALMETALAREA 0.025 ;
	END d[16]

	PIN d[17]
		USE SIGNAL ;
		DIRECTION INPUT ;
		SHAPE ABUTMENT ;
		PORT
			LAYER	M1 ;
			RECT	0 25.875 0.25 25.975 ;
			LAYER	M2 ;
			RECT	0 25.875 0.25 25.975 ;
			LAYER	M3 ;
			RECT	0 25.875 0.25 25.975 ;
		END

		ANTENNAGATEAREA 0.014 ;
		ANTENNADIFFAREA 0.018 ;
		ANTENNAPARTIALMETALAREA 0.025 ;
	END d[17]

	PIN d[18]
		USE SIGNAL ;
		DIRECTION INPUT ;
		SHAPE ABUTMENT ;
		PORT
			LAYER	M1 ;
			RECT	0 26.925 0.25 27.025 ;
			LAYER	M2 ;
			RECT	0 26.925 0.25 27.025 ;
			LAYER	M3 ;
			RECT	0 26.925 0.25 27.025 ;
		END

		ANTENNAGATEAREA 0.014 ;
		ANTENNADIFFAREA 0.018 ;
		ANTENNAPARTIALMETALAREA 0.025 ;
	END d[18]

	PIN d[19]
		USE SIGNAL ;
		DIRECTION INPUT ;
		SHAPE ABUTMENT ;
		PORT
			LAYER	M1 ;
			RECT	0 28.715 0.25 28.815 ;
			LAYER	M2 ;
			RECT	0 28.715 0.25 28.815 ;
			LAYER	M3 ;
			RECT	0 28.715 0.25 28.815 ;
		END

		ANTENNAGATEAREA 0.014 ;
		ANTENNADIFFAREA 0.018 ;
		ANTENNAPARTIALMETALAREA 0.025 ;
	END d[19]

	PIN d[1]
		USE SIGNAL ;
		DIRECTION INPUT ;
		SHAPE ABUTMENT ;
		PORT
			LAYER	M1 ;
			RECT	0 3.155 0.25 3.255 ;
			LAYER	M2 ;
			RECT	0 3.155 0.25 3.255 ;
			LAYER	M3 ;
			RECT	0 3.155 0.25 3.255 ;
		END

		ANTENNAGATEAREA 0.014 ;
		ANTENNADIFFAREA 0.018 ;
		ANTENNAPARTIALMETALAREA 0.025 ;
	END d[1]

	PIN d[20]
		USE SIGNAL ;
		DIRECTION INPUT ;
		SHAPE ABUTMENT ;
		PORT
			LAYER	M1 ;
			RECT	0 29.765 0.25 29.865 ;
			LAYER	M2 ;
			RECT	0 29.765 0.25 29.865 ;
			LAYER	M3 ;
			RECT	0 29.765 0.25 29.865 ;
		END

		ANTENNAGATEAREA 0.014 ;
		ANTENNADIFFAREA 0.018 ;
		ANTENNAPARTIALMETALAREA 0.025 ;
	END d[20]

	PIN d[21]
		USE SIGNAL ;
		DIRECTION INPUT ;
		SHAPE ABUTMENT ;
		PORT
			LAYER	M1 ;
			RECT	0 31.555 0.25 31.655 ;
			LAYER	M2 ;
			RECT	0 31.555 0.25 31.655 ;
			LAYER	M3 ;
			RECT	0 31.555 0.25 31.655 ;
		END

		ANTENNAGATEAREA 0.014 ;
		ANTENNADIFFAREA 0.018 ;
		ANTENNAPARTIALMETALAREA 0.025 ;
	END d[21]

	PIN d[22]
		USE SIGNAL ;
		DIRECTION INPUT ;
		SHAPE ABUTMENT ;
		PORT
			LAYER	M1 ;
			RECT	0 32.605 0.25 32.705 ;
			LAYER	M2 ;
			RECT	0 32.605 0.25 32.705 ;
			LAYER	M3 ;
			RECT	0 32.605 0.25 32.705 ;
		END

		ANTENNAGATEAREA 0.014 ;
		ANTENNADIFFAREA 0.018 ;
		ANTENNAPARTIALMETALAREA 0.025 ;
	END d[22]

	PIN d[23]
		USE SIGNAL ;
		DIRECTION INPUT ;
		SHAPE ABUTMENT ;
		PORT
			LAYER	M1 ;
			RECT	0 34.395 0.25 34.495 ;
			LAYER	M2 ;
			RECT	0 34.395 0.25 34.495 ;
			LAYER	M3 ;
			RECT	0 34.395 0.25 34.495 ;
		END

		ANTENNAGATEAREA 0.014 ;
		ANTENNADIFFAREA 0.018 ;
		ANTENNAPARTIALMETALAREA 0.025 ;
	END d[23]

	PIN d[24]
		USE SIGNAL ;
		DIRECTION INPUT ;
		SHAPE ABUTMENT ;
		PORT
			LAYER	M1 ;
			RECT	0 35.445 0.25 35.545 ;
			LAYER	M2 ;
			RECT	0 35.445 0.25 35.545 ;
			LAYER	M3 ;
			RECT	0 35.445 0.25 35.545 ;
		END

		ANTENNAGATEAREA 0.014 ;
		ANTENNADIFFAREA 0.018 ;
		ANTENNAPARTIALMETALAREA 0.025 ;
	END d[24]

	PIN d[25]
		USE SIGNAL ;
		DIRECTION INPUT ;
		SHAPE ABUTMENT ;
		PORT
			LAYER	M1 ;
			RECT	0 37.235 0.25 37.335 ;
			LAYER	M2 ;
			RECT	0 37.235 0.25 37.335 ;
			LAYER	M3 ;
			RECT	0 37.235 0.25 37.335 ;
		END

		ANTENNAGATEAREA 0.014 ;
		ANTENNADIFFAREA 0.018 ;
		ANTENNAPARTIALMETALAREA 0.025 ;
	END d[25]

	PIN d[26]
		USE SIGNAL ;
		DIRECTION INPUT ;
		SHAPE ABUTMENT ;
		PORT
			LAYER	M1 ;
			RECT	0 38.285 0.25 38.385 ;
			LAYER	M2 ;
			RECT	0 38.285 0.25 38.385 ;
			LAYER	M3 ;
			RECT	0 38.285 0.25 38.385 ;
		END

		ANTENNAGATEAREA 0.014 ;
		ANTENNADIFFAREA 0.018 ;
		ANTENNAPARTIALMETALAREA 0.025 ;
	END d[26]

	PIN d[27]
		USE SIGNAL ;
		DIRECTION INPUT ;
		SHAPE ABUTMENT ;
		PORT
			LAYER	M1 ;
			RECT	0 40.075 0.25 40.175 ;
			LAYER	M2 ;
			RECT	0 40.075 0.25 40.175 ;
			LAYER	M3 ;
			RECT	0 40.075 0.25 40.175 ;
		END

		ANTENNAGATEAREA 0.014 ;
		ANTENNADIFFAREA 0.018 ;
		ANTENNAPARTIALMETALAREA 0.025 ;
	END d[27]

	PIN d[28]
		USE SIGNAL ;
		DIRECTION INPUT ;
		SHAPE ABUTMENT ;
		PORT
			LAYER	M1 ;
			RECT	0 41.125 0.25 41.225 ;
			LAYER	M2 ;
			RECT	0 41.125 0.25 41.225 ;
			LAYER	M3 ;
			RECT	0 41.125 0.25 41.225 ;
		END

		ANTENNAGATEAREA 0.014 ;
		ANTENNADIFFAREA 0.018 ;
		ANTENNAPARTIALMETALAREA 0.025 ;
	END d[28]

	PIN d[29]
		USE SIGNAL ;
		DIRECTION INPUT ;
		SHAPE ABUTMENT ;
		PORT
			LAYER	M1 ;
			RECT	0 42.915 0.25 43.015 ;
			LAYER	M2 ;
			RECT	0 42.915 0.25 43.015 ;
			LAYER	M3 ;
			RECT	0 42.915 0.25 43.015 ;
		END

		ANTENNAGATEAREA 0.014 ;
		ANTENNADIFFAREA 0.018 ;
		ANTENNAPARTIALMETALAREA 0.025 ;
	END d[29]

	PIN d[2]
		USE SIGNAL ;
		DIRECTION INPUT ;
		SHAPE ABUTMENT ;
		PORT
			LAYER	M1 ;
			RECT	0 4.205 0.25 4.305 ;
			LAYER	M2 ;
			RECT	0 4.205 0.25 4.305 ;
			LAYER	M3 ;
			RECT	0 4.205 0.25 4.305 ;
		END

		ANTENNAGATEAREA 0.014 ;
		ANTENNADIFFAREA 0.018 ;
		ANTENNAPARTIALMETALAREA 0.025 ;
	END d[2]

	PIN d[30]
		USE SIGNAL ;
		DIRECTION INPUT ;
		SHAPE ABUTMENT ;
		PORT
			LAYER	M1 ;
			RECT	0 43.965 0.25 44.065 ;
			LAYER	M2 ;
			RECT	0 43.965 0.25 44.065 ;
			LAYER	M3 ;
			RECT	0 43.965 0.25 44.065 ;
		END

		ANTENNAGATEAREA 0.014 ;
		ANTENNADIFFAREA 0.018 ;
		ANTENNAPARTIALMETALAREA 0.025 ;
	END d[30]

	PIN d[31]
		USE SIGNAL ;
		DIRECTION INPUT ;
		SHAPE ABUTMENT ;
		PORT
			LAYER	M1 ;
			RECT	0 45.755 0.25 45.855 ;
			LAYER	M2 ;
			RECT	0 45.755 0.25 45.855 ;
			LAYER	M3 ;
			RECT	0 45.755 0.25 45.855 ;
		END

		ANTENNAGATEAREA 0.014 ;
		ANTENNADIFFAREA 0.018 ;
		ANTENNAPARTIALMETALAREA 0.025 ;
	END d[31]

	PIN d[32]
		USE SIGNAL ;
		DIRECTION INPUT ;
		SHAPE ABUTMENT ;
		PORT
			LAYER	M1 ;
			RECT	0 46.805 0.25 46.905 ;
			LAYER	M2 ;
			RECT	0 46.805 0.25 46.905 ;
			LAYER	M3 ;
			RECT	0 46.805 0.25 46.905 ;
		END

		ANTENNAGATEAREA 0.014 ;
		ANTENNADIFFAREA 0.018 ;
		ANTENNAPARTIALMETALAREA 0.025 ;
	END d[32]

	PIN d[33]
		USE SIGNAL ;
		DIRECTION INPUT ;
		SHAPE ABUTMENT ;
		PORT
			LAYER	M1 ;
			RECT	0 48.595 0.25 48.695 ;
			LAYER	M2 ;
			RECT	0 48.595 0.25 48.695 ;
			LAYER	M3 ;
			RECT	0 48.595 0.25 48.695 ;
		END

		ANTENNAGATEAREA 0.014 ;
		ANTENNADIFFAREA 0.018 ;
		ANTENNAPARTIALMETALAREA 0.025 ;
	END d[33]

	PIN d[34]
		USE SIGNAL ;
		DIRECTION INPUT ;
		SHAPE ABUTMENT ;
		PORT
			LAYER	M1 ;
			RECT	0 49.645 0.25 49.745 ;
			LAYER	M2 ;
			RECT	0 49.645 0.25 49.745 ;
			LAYER	M3 ;
			RECT	0 49.645 0.25 49.745 ;
		END

		ANTENNAGATEAREA 0.014 ;
		ANTENNADIFFAREA 0.018 ;
		ANTENNAPARTIALMETALAREA 0.025 ;
	END d[34]

	PIN d[35]
		USE SIGNAL ;
		DIRECTION INPUT ;
		SHAPE ABUTMENT ;
		PORT
			LAYER	M1 ;
			RECT	0 51.435 0.25 51.535 ;
			LAYER	M2 ;
			RECT	0 51.435 0.25 51.535 ;
			LAYER	M3 ;
			RECT	0 51.435 0.25 51.535 ;
		END

		ANTENNAGATEAREA 0.014 ;
		ANTENNADIFFAREA 0.018 ;
		ANTENNAPARTIALMETALAREA 0.025 ;
	END d[35]

	PIN d[36]
		USE SIGNAL ;
		DIRECTION INPUT ;
		SHAPE ABUTMENT ;
		PORT
			LAYER	M1 ;
			RECT	0 52.485 0.25 52.585 ;
			LAYER	M2 ;
			RECT	0 52.485 0.25 52.585 ;
			LAYER	M3 ;
			RECT	0 52.485 0.25 52.585 ;
		END

		ANTENNAGATEAREA 0.014 ;
		ANTENNADIFFAREA 0.018 ;
		ANTENNAPARTIALMETALAREA 0.025 ;
	END d[36]

	PIN d[37]
		USE SIGNAL ;
		DIRECTION INPUT ;
		SHAPE ABUTMENT ;
		PORT
			LAYER	M1 ;
			RECT	0 54.275 0.25 54.375 ;
			LAYER	M2 ;
			RECT	0 54.275 0.25 54.375 ;
			LAYER	M3 ;
			RECT	0 54.275 0.25 54.375 ;
		END

		ANTENNAGATEAREA 0.014 ;
		ANTENNADIFFAREA 0.018 ;
		ANTENNAPARTIALMETALAREA 0.025 ;
	END d[37]

	PIN d[38]
		USE SIGNAL ;
		DIRECTION INPUT ;
		SHAPE ABUTMENT ;
		PORT
			LAYER	M1 ;
			RECT	0 55.325 0.25 55.425 ;
			LAYER	M2 ;
			RECT	0 55.325 0.25 55.425 ;
			LAYER	M3 ;
			RECT	0 55.325 0.25 55.425 ;
		END

		ANTENNAGATEAREA 0.014 ;
		ANTENNADIFFAREA 0.018 ;
		ANTENNAPARTIALMETALAREA 0.025 ;
	END d[38]

	PIN d[39]
		USE SIGNAL ;
		DIRECTION INPUT ;
		SHAPE ABUTMENT ;
		PORT
			LAYER	M1 ;
			RECT	0 57.115 0.25 57.215 ;
			LAYER	M2 ;
			RECT	0 57.115 0.25 57.215 ;
			LAYER	M3 ;
			RECT	0 57.115 0.25 57.215 ;
		END

		ANTENNAGATEAREA 0.014 ;
		ANTENNADIFFAREA 0.018 ;
		ANTENNAPARTIALMETALAREA 0.025 ;
	END d[39]

	PIN d[3]
		USE SIGNAL ;
		DIRECTION INPUT ;
		SHAPE ABUTMENT ;
		PORT
			LAYER	M1 ;
			RECT	0 5.995 0.25 6.095 ;
			LAYER	M2 ;
			RECT	0 5.995 0.25 6.095 ;
			LAYER	M3 ;
			RECT	0 5.995 0.25 6.095 ;
		END

		ANTENNAGATEAREA 0.014 ;
		ANTENNADIFFAREA 0.018 ;
		ANTENNAPARTIALMETALAREA 0.025 ;
	END d[3]

	PIN d[40]
		USE SIGNAL ;
		DIRECTION INPUT ;
		SHAPE ABUTMENT ;
		PORT
			LAYER	M1 ;
			RECT	0 58.165 0.25 58.265 ;
			LAYER	M2 ;
			RECT	0 58.165 0.25 58.265 ;
			LAYER	M3 ;
			RECT	0 58.165 0.25 58.265 ;
		END

		ANTENNAGATEAREA 0.014 ;
		ANTENNADIFFAREA 0.018 ;
		ANTENNAPARTIALMETALAREA 0.025 ;
	END d[40]

	PIN d[41]
		USE SIGNAL ;
		DIRECTION INPUT ;
		SHAPE ABUTMENT ;
		PORT
			LAYER	M1 ;
			RECT	0 59.955 0.25 60.055 ;
			LAYER	M2 ;
			RECT	0 59.955 0.25 60.055 ;
			LAYER	M3 ;
			RECT	0 59.955 0.25 60.055 ;
		END

		ANTENNAGATEAREA 0.014 ;
		ANTENNADIFFAREA 0.018 ;
		ANTENNAPARTIALMETALAREA 0.025 ;
	END d[41]

	PIN d[42]
		USE SIGNAL ;
		DIRECTION INPUT ;
		SHAPE ABUTMENT ;
		PORT
			LAYER	M1 ;
			RECT	0 61.005 0.25 61.105 ;
			LAYER	M2 ;
			RECT	0 61.005 0.25 61.105 ;
			LAYER	M3 ;
			RECT	0 61.005 0.25 61.105 ;
		END

		ANTENNAGATEAREA 0.014 ;
		ANTENNADIFFAREA 0.018 ;
		ANTENNAPARTIALMETALAREA 0.025 ;
	END d[42]

	PIN d[43]
		USE SIGNAL ;
		DIRECTION INPUT ;
		SHAPE ABUTMENT ;
		PORT
			LAYER	M1 ;
			RECT	0 62.795 0.25 62.895 ;
			LAYER	M2 ;
			RECT	0 62.795 0.25 62.895 ;
			LAYER	M3 ;
			RECT	0 62.795 0.25 62.895 ;
		END

		ANTENNAGATEAREA 0.014 ;
		ANTENNADIFFAREA 0.018 ;
		ANTENNAPARTIALMETALAREA 0.025 ;
	END d[43]

	PIN d[44]
		USE SIGNAL ;
		DIRECTION INPUT ;
		SHAPE ABUTMENT ;
		PORT
			LAYER	M1 ;
			RECT	0 63.845 0.25 63.945 ;
			LAYER	M2 ;
			RECT	0 63.845 0.25 63.945 ;
			LAYER	M3 ;
			RECT	0 63.845 0.25 63.945 ;
		END

		ANTENNAGATEAREA 0.014 ;
		ANTENNADIFFAREA 0.018 ;
		ANTENNAPARTIALMETALAREA 0.025 ;
	END d[44]

	PIN d[45]
		USE SIGNAL ;
		DIRECTION INPUT ;
		SHAPE ABUTMENT ;
		PORT
			LAYER	M1 ;
			RECT	0 65.635 0.25 65.735 ;
			LAYER	M2 ;
			RECT	0 65.635 0.25 65.735 ;
			LAYER	M3 ;
			RECT	0 65.635 0.25 65.735 ;
		END

		ANTENNAGATEAREA 0.014 ;
		ANTENNADIFFAREA 0.018 ;
		ANTENNAPARTIALMETALAREA 0.025 ;
	END d[45]

	PIN d[46]
		USE SIGNAL ;
		DIRECTION INPUT ;
		SHAPE ABUTMENT ;
		PORT
			LAYER	M1 ;
			RECT	0 66.685 0.25 66.785 ;
			LAYER	M2 ;
			RECT	0 66.685 0.25 66.785 ;
			LAYER	M3 ;
			RECT	0 66.685 0.25 66.785 ;
		END

		ANTENNAGATEAREA 0.014 ;
		ANTENNADIFFAREA 0.018 ;
		ANTENNAPARTIALMETALAREA 0.025 ;
	END d[46]

	PIN d[47]
		USE SIGNAL ;
		DIRECTION INPUT ;
		SHAPE ABUTMENT ;
		PORT
			LAYER	M1 ;
			RECT	0 68.475 0.25 68.575 ;
			LAYER	M2 ;
			RECT	0 68.475 0.25 68.575 ;
			LAYER	M3 ;
			RECT	0 68.475 0.25 68.575 ;
		END

		ANTENNAGATEAREA 0.014 ;
		ANTENNADIFFAREA 0.018 ;
		ANTENNAPARTIALMETALAREA 0.025 ;
	END d[47]

	PIN d[48]
		USE SIGNAL ;
		DIRECTION INPUT ;
		SHAPE ABUTMENT ;
		PORT
			LAYER	M1 ;
			RECT	0 69.525 0.25 69.625 ;
			LAYER	M2 ;
			RECT	0 69.525 0.25 69.625 ;
			LAYER	M3 ;
			RECT	0 69.525 0.25 69.625 ;
		END

		ANTENNAGATEAREA 0.014 ;
		ANTENNADIFFAREA 0.018 ;
		ANTENNAPARTIALMETALAREA 0.025 ;
	END d[48]

	PIN d[49]
		USE SIGNAL ;
		DIRECTION INPUT ;
		SHAPE ABUTMENT ;
		PORT
			LAYER	M1 ;
			RECT	0 71.315 0.25 71.415 ;
			LAYER	M2 ;
			RECT	0 71.315 0.25 71.415 ;
			LAYER	M3 ;
			RECT	0 71.315 0.25 71.415 ;
		END

		ANTENNAGATEAREA 0.014 ;
		ANTENNADIFFAREA 0.018 ;
		ANTENNAPARTIALMETALAREA 0.025 ;
	END d[49]

	PIN d[4]
		USE SIGNAL ;
		DIRECTION INPUT ;
		SHAPE ABUTMENT ;
		PORT
			LAYER	M1 ;
			RECT	0 7.045 0.25 7.145 ;
			LAYER	M2 ;
			RECT	0 7.045 0.25 7.145 ;
			LAYER	M3 ;
			RECT	0 7.045 0.25 7.145 ;
		END

		ANTENNAGATEAREA 0.014 ;
		ANTENNADIFFAREA 0.018 ;
		ANTENNAPARTIALMETALAREA 0.025 ;
	END d[4]

	PIN d[50]
		USE SIGNAL ;
		DIRECTION INPUT ;
		SHAPE ABUTMENT ;
		PORT
			LAYER	M1 ;
			RECT	0 72.365 0.25 72.465 ;
			LAYER	M2 ;
			RECT	0 72.365 0.25 72.465 ;
			LAYER	M3 ;
			RECT	0 72.365 0.25 72.465 ;
		END

		ANTENNAGATEAREA 0.014 ;
		ANTENNADIFFAREA 0.018 ;
		ANTENNAPARTIALMETALAREA 0.025 ;
	END d[50]

	PIN d[51]
		USE SIGNAL ;
		DIRECTION INPUT ;
		SHAPE ABUTMENT ;
		PORT
			LAYER	M1 ;
			RECT	0 74.155 0.25 74.255 ;
			LAYER	M2 ;
			RECT	0 74.155 0.25 74.255 ;
			LAYER	M3 ;
			RECT	0 74.155 0.25 74.255 ;
		END

		ANTENNAGATEAREA 0.014 ;
		ANTENNADIFFAREA 0.018 ;
		ANTENNAPARTIALMETALAREA 0.025 ;
	END d[51]

	PIN d[52]
		USE SIGNAL ;
		DIRECTION INPUT ;
		SHAPE ABUTMENT ;
		PORT
			LAYER	M1 ;
			RECT	0 75.205 0.25 75.305 ;
			LAYER	M2 ;
			RECT	0 75.205 0.25 75.305 ;
			LAYER	M3 ;
			RECT	0 75.205 0.25 75.305 ;
		END

		ANTENNAGATEAREA 0.014 ;
		ANTENNADIFFAREA 0.018 ;
		ANTENNAPARTIALMETALAREA 0.025 ;
	END d[52]

	PIN d[53]
		USE SIGNAL ;
		DIRECTION INPUT ;
		SHAPE ABUTMENT ;
		PORT
			LAYER	M1 ;
			RECT	0 76.995 0.25 77.095 ;
			LAYER	M2 ;
			RECT	0 76.995 0.25 77.095 ;
			LAYER	M3 ;
			RECT	0 76.995 0.25 77.095 ;
		END

		ANTENNAGATEAREA 0.014 ;
		ANTENNADIFFAREA 0.018 ;
		ANTENNAPARTIALMETALAREA 0.025 ;
	END d[53]

	PIN d[54]
		USE SIGNAL ;
		DIRECTION INPUT ;
		SHAPE ABUTMENT ;
		PORT
			LAYER	M1 ;
			RECT	0 78.045 0.25 78.145 ;
			LAYER	M2 ;
			RECT	0 78.045 0.25 78.145 ;
			LAYER	M3 ;
			RECT	0 78.045 0.25 78.145 ;
		END

		ANTENNAGATEAREA 0.014 ;
		ANTENNADIFFAREA 0.018 ;
		ANTENNAPARTIALMETALAREA 0.025 ;
	END d[54]

	PIN d[55]
		USE SIGNAL ;
		DIRECTION INPUT ;
		SHAPE ABUTMENT ;
		PORT
			LAYER	M1 ;
			RECT	0 79.835 0.25 79.935 ;
			LAYER	M2 ;
			RECT	0 79.835 0.25 79.935 ;
			LAYER	M3 ;
			RECT	0 79.835 0.25 79.935 ;
		END

		ANTENNAGATEAREA 0.014 ;
		ANTENNADIFFAREA 0.018 ;
		ANTENNAPARTIALMETALAREA 0.025 ;
	END d[55]

	PIN d[56]
		USE SIGNAL ;
		DIRECTION INPUT ;
		SHAPE ABUTMENT ;
		PORT
			LAYER	M1 ;
			RECT	0 80.885 0.25 80.985 ;
			LAYER	M2 ;
			RECT	0 80.885 0.25 80.985 ;
			LAYER	M3 ;
			RECT	0 80.885 0.25 80.985 ;
		END

		ANTENNAGATEAREA 0.014 ;
		ANTENNADIFFAREA 0.018 ;
		ANTENNAPARTIALMETALAREA 0.025 ;
	END d[56]

	PIN d[57]
		USE SIGNAL ;
		DIRECTION INPUT ;
		SHAPE ABUTMENT ;
		PORT
			LAYER	M1 ;
			RECT	0 82.675 0.25 82.775 ;
			LAYER	M2 ;
			RECT	0 82.675 0.25 82.775 ;
			LAYER	M3 ;
			RECT	0 82.675 0.25 82.775 ;
		END

		ANTENNAGATEAREA 0.014 ;
		ANTENNADIFFAREA 0.018 ;
		ANTENNAPARTIALMETALAREA 0.025 ;
	END d[57]

	PIN d[58]
		USE SIGNAL ;
		DIRECTION INPUT ;
		SHAPE ABUTMENT ;
		PORT
			LAYER	M1 ;
			RECT	0 83.725 0.25 83.825 ;
			LAYER	M2 ;
			RECT	0 83.725 0.25 83.825 ;
			LAYER	M3 ;
			RECT	0 83.725 0.25 83.825 ;
		END

		ANTENNAGATEAREA 0.014 ;
		ANTENNADIFFAREA 0.018 ;
		ANTENNAPARTIALMETALAREA 0.025 ;
	END d[58]

	PIN d[59]
		USE SIGNAL ;
		DIRECTION INPUT ;
		SHAPE ABUTMENT ;
		PORT
			LAYER	M1 ;
			RECT	0 85.515 0.25 85.615 ;
			LAYER	M2 ;
			RECT	0 85.515 0.25 85.615 ;
			LAYER	M3 ;
			RECT	0 85.515 0.25 85.615 ;
		END

		ANTENNAGATEAREA 0.014 ;
		ANTENNADIFFAREA 0.018 ;
		ANTENNAPARTIALMETALAREA 0.025 ;
	END d[59]

	PIN d[5]
		USE SIGNAL ;
		DIRECTION INPUT ;
		SHAPE ABUTMENT ;
		PORT
			LAYER	M1 ;
			RECT	0 8.835 0.25 8.935 ;
			LAYER	M2 ;
			RECT	0 8.835 0.25 8.935 ;
			LAYER	M3 ;
			RECT	0 8.835 0.25 8.935 ;
		END

		ANTENNAGATEAREA 0.014 ;
		ANTENNADIFFAREA 0.018 ;
		ANTENNAPARTIALMETALAREA 0.025 ;
	END d[5]

	PIN d[60]
		USE SIGNAL ;
		DIRECTION INPUT ;
		SHAPE ABUTMENT ;
		PORT
			LAYER	M1 ;
			RECT	0 86.565 0.25 86.665 ;
			LAYER	M2 ;
			RECT	0 86.565 0.25 86.665 ;
			LAYER	M3 ;
			RECT	0 86.565 0.25 86.665 ;
		END

		ANTENNAGATEAREA 0.014 ;
		ANTENNADIFFAREA 0.018 ;
		ANTENNAPARTIALMETALAREA 0.025 ;
	END d[60]

	PIN d[61]
		USE SIGNAL ;
		DIRECTION INPUT ;
		SHAPE ABUTMENT ;
		PORT
			LAYER	M1 ;
			RECT	0 88.355 0.25 88.455 ;
			LAYER	M2 ;
			RECT	0 88.355 0.25 88.455 ;
			LAYER	M3 ;
			RECT	0 88.355 0.25 88.455 ;
		END

		ANTENNAGATEAREA 0.014 ;
		ANTENNADIFFAREA 0.018 ;
		ANTENNAPARTIALMETALAREA 0.025 ;
	END d[61]

	PIN d[62]
		USE SIGNAL ;
		DIRECTION INPUT ;
		SHAPE ABUTMENT ;
		PORT
			LAYER	M1 ;
			RECT	0 89.405 0.25 89.505 ;
			LAYER	M2 ;
			RECT	0 89.405 0.25 89.505 ;
			LAYER	M3 ;
			RECT	0 89.405 0.25 89.505 ;
		END

		ANTENNAGATEAREA 0.014 ;
		ANTENNADIFFAREA 0.018 ;
		ANTENNAPARTIALMETALAREA 0.025 ;
	END d[62]

	PIN d[63]
		USE SIGNAL ;
		DIRECTION INPUT ;
		SHAPE ABUTMENT ;
		PORT
			LAYER	M1 ;
			RECT	0 91.195 0.25 91.295 ;
			LAYER	M2 ;
			RECT	0 91.195 0.25 91.295 ;
			LAYER	M3 ;
			RECT	0 91.195 0.25 91.295 ;
		END

		ANTENNAGATEAREA 0.014 ;
		ANTENNADIFFAREA 0.018 ;
		ANTENNAPARTIALMETALAREA 0.025 ;
	END d[63]

	PIN d[64]
		USE SIGNAL ;
		DIRECTION INPUT ;
		SHAPE ABUTMENT ;
		PORT
			LAYER	M1 ;
			RECT	0 114.73 0.25 114.83 ;
			LAYER	M2 ;
			RECT	0 114.73 0.25 114.83 ;
			LAYER	M3 ;
			RECT	0 114.73 0.25 114.83 ;
		END

		ANTENNAGATEAREA 0.014 ;
		ANTENNADIFFAREA 0.018 ;
		ANTENNAPARTIALMETALAREA 0.025 ;
	END d[64]

	PIN d[65]
		USE SIGNAL ;
		DIRECTION INPUT ;
		SHAPE ABUTMENT ;
		PORT
			LAYER	M1 ;
			RECT	0 116.52 0.25 116.62 ;
			LAYER	M2 ;
			RECT	0 116.52 0.25 116.62 ;
			LAYER	M3 ;
			RECT	0 116.52 0.25 116.62 ;
		END

		ANTENNAGATEAREA 0.014 ;
		ANTENNADIFFAREA 0.018 ;
		ANTENNAPARTIALMETALAREA 0.025 ;
	END d[65]

	PIN d[66]
		USE SIGNAL ;
		DIRECTION INPUT ;
		SHAPE ABUTMENT ;
		PORT
			LAYER	M1 ;
			RECT	0 117.57 0.25 117.67 ;
			LAYER	M2 ;
			RECT	0 117.57 0.25 117.67 ;
			LAYER	M3 ;
			RECT	0 117.57 0.25 117.67 ;
		END

		ANTENNAGATEAREA 0.014 ;
		ANTENNADIFFAREA 0.018 ;
		ANTENNAPARTIALMETALAREA 0.025 ;
	END d[66]

	PIN d[67]
		USE SIGNAL ;
		DIRECTION INPUT ;
		SHAPE ABUTMENT ;
		PORT
			LAYER	M1 ;
			RECT	0 119.36 0.25 119.46 ;
			LAYER	M2 ;
			RECT	0 119.36 0.25 119.46 ;
			LAYER	M3 ;
			RECT	0 119.36 0.25 119.46 ;
		END

		ANTENNAGATEAREA 0.014 ;
		ANTENNADIFFAREA 0.018 ;
		ANTENNAPARTIALMETALAREA 0.025 ;
	END d[67]

	PIN d[68]
		USE SIGNAL ;
		DIRECTION INPUT ;
		SHAPE ABUTMENT ;
		PORT
			LAYER	M1 ;
			RECT	0 120.41 0.25 120.51 ;
			LAYER	M2 ;
			RECT	0 120.41 0.25 120.51 ;
			LAYER	M3 ;
			RECT	0 120.41 0.25 120.51 ;
		END

		ANTENNAGATEAREA 0.014 ;
		ANTENNADIFFAREA 0.018 ;
		ANTENNAPARTIALMETALAREA 0.025 ;
	END d[68]

	PIN d[69]
		USE SIGNAL ;
		DIRECTION INPUT ;
		SHAPE ABUTMENT ;
		PORT
			LAYER	M1 ;
			RECT	0 122.2 0.25 122.3 ;
			LAYER	M2 ;
			RECT	0 122.2 0.25 122.3 ;
			LAYER	M3 ;
			RECT	0 122.2 0.25 122.3 ;
		END

		ANTENNAGATEAREA 0.014 ;
		ANTENNADIFFAREA 0.018 ;
		ANTENNAPARTIALMETALAREA 0.025 ;
	END d[69]

	PIN d[6]
		USE SIGNAL ;
		DIRECTION INPUT ;
		SHAPE ABUTMENT ;
		PORT
			LAYER	M1 ;
			RECT	0 9.885 0.25 9.985 ;
			LAYER	M2 ;
			RECT	0 9.885 0.25 9.985 ;
			LAYER	M3 ;
			RECT	0 9.885 0.25 9.985 ;
		END

		ANTENNAGATEAREA 0.014 ;
		ANTENNADIFFAREA 0.018 ;
		ANTENNAPARTIALMETALAREA 0.025 ;
	END d[6]

	PIN d[70]
		USE SIGNAL ;
		DIRECTION INPUT ;
		SHAPE ABUTMENT ;
		PORT
			LAYER	M1 ;
			RECT	0 123.25 0.25 123.35 ;
			LAYER	M2 ;
			RECT	0 123.25 0.25 123.35 ;
			LAYER	M3 ;
			RECT	0 123.25 0.25 123.35 ;
		END

		ANTENNAGATEAREA 0.014 ;
		ANTENNADIFFAREA 0.018 ;
		ANTENNAPARTIALMETALAREA 0.025 ;
	END d[70]

	PIN d[71]
		USE SIGNAL ;
		DIRECTION INPUT ;
		SHAPE ABUTMENT ;
		PORT
			LAYER	M1 ;
			RECT	0 125.04 0.25 125.14 ;
			LAYER	M2 ;
			RECT	0 125.04 0.25 125.14 ;
			LAYER	M3 ;
			RECT	0 125.04 0.25 125.14 ;
		END

		ANTENNAGATEAREA 0.014 ;
		ANTENNADIFFAREA 0.018 ;
		ANTENNAPARTIALMETALAREA 0.025 ;
	END d[71]

	PIN d[72]
		USE SIGNAL ;
		DIRECTION INPUT ;
		SHAPE ABUTMENT ;
		PORT
			LAYER	M1 ;
			RECT	0 126.09 0.25 126.19 ;
			LAYER	M2 ;
			RECT	0 126.09 0.25 126.19 ;
			LAYER	M3 ;
			RECT	0 126.09 0.25 126.19 ;
		END

		ANTENNAGATEAREA 0.014 ;
		ANTENNADIFFAREA 0.018 ;
		ANTENNAPARTIALMETALAREA 0.025 ;
	END d[72]

	PIN d[73]
		USE SIGNAL ;
		DIRECTION INPUT ;
		SHAPE ABUTMENT ;
		PORT
			LAYER	M1 ;
			RECT	0 127.88 0.25 127.98 ;
			LAYER	M2 ;
			RECT	0 127.88 0.25 127.98 ;
			LAYER	M3 ;
			RECT	0 127.88 0.25 127.98 ;
		END

		ANTENNAGATEAREA 0.014 ;
		ANTENNADIFFAREA 0.018 ;
		ANTENNAPARTIALMETALAREA 0.025 ;
	END d[73]

	PIN d[74]
		USE SIGNAL ;
		DIRECTION INPUT ;
		SHAPE ABUTMENT ;
		PORT
			LAYER	M1 ;
			RECT	0 128.93 0.25 129.03 ;
			LAYER	M2 ;
			RECT	0 128.93 0.25 129.03 ;
			LAYER	M3 ;
			RECT	0 128.93 0.25 129.03 ;
		END

		ANTENNAGATEAREA 0.014 ;
		ANTENNADIFFAREA 0.018 ;
		ANTENNAPARTIALMETALAREA 0.025 ;
	END d[74]

	PIN d[75]
		USE SIGNAL ;
		DIRECTION INPUT ;
		SHAPE ABUTMENT ;
		PORT
			LAYER	M1 ;
			RECT	0 130.72 0.25 130.82 ;
			LAYER	M2 ;
			RECT	0 130.72 0.25 130.82 ;
			LAYER	M3 ;
			RECT	0 130.72 0.25 130.82 ;
		END

		ANTENNAGATEAREA 0.014 ;
		ANTENNADIFFAREA 0.018 ;
		ANTENNAPARTIALMETALAREA 0.025 ;
	END d[75]

	PIN d[76]
		USE SIGNAL ;
		DIRECTION INPUT ;
		SHAPE ABUTMENT ;
		PORT
			LAYER	M1 ;
			RECT	0 131.77 0.25 131.87 ;
			LAYER	M2 ;
			RECT	0 131.77 0.25 131.87 ;
			LAYER	M3 ;
			RECT	0 131.77 0.25 131.87 ;
		END

		ANTENNAGATEAREA 0.014 ;
		ANTENNADIFFAREA 0.018 ;
		ANTENNAPARTIALMETALAREA 0.025 ;
	END d[76]

	PIN d[77]
		USE SIGNAL ;
		DIRECTION INPUT ;
		SHAPE ABUTMENT ;
		PORT
			LAYER	M1 ;
			RECT	0 133.56 0.25 133.66 ;
			LAYER	M2 ;
			RECT	0 133.56 0.25 133.66 ;
			LAYER	M3 ;
			RECT	0 133.56 0.25 133.66 ;
		END

		ANTENNAGATEAREA 0.014 ;
		ANTENNADIFFAREA 0.018 ;
		ANTENNAPARTIALMETALAREA 0.025 ;
	END d[77]

	PIN d[78]
		USE SIGNAL ;
		DIRECTION INPUT ;
		SHAPE ABUTMENT ;
		PORT
			LAYER	M1 ;
			RECT	0 134.61 0.25 134.71 ;
			LAYER	M2 ;
			RECT	0 134.61 0.25 134.71 ;
			LAYER	M3 ;
			RECT	0 134.61 0.25 134.71 ;
		END

		ANTENNAGATEAREA 0.014 ;
		ANTENNADIFFAREA 0.018 ;
		ANTENNAPARTIALMETALAREA 0.025 ;
	END d[78]

	PIN d[79]
		USE SIGNAL ;
		DIRECTION INPUT ;
		SHAPE ABUTMENT ;
		PORT
			LAYER	M1 ;
			RECT	0 136.4 0.25 136.5 ;
			LAYER	M2 ;
			RECT	0 136.4 0.25 136.5 ;
			LAYER	M3 ;
			RECT	0 136.4 0.25 136.5 ;
		END

		ANTENNAGATEAREA 0.014 ;
		ANTENNADIFFAREA 0.018 ;
		ANTENNAPARTIALMETALAREA 0.025 ;
	END d[79]

	PIN d[7]
		USE SIGNAL ;
		DIRECTION INPUT ;
		SHAPE ABUTMENT ;
		PORT
			LAYER	M1 ;
			RECT	0 11.675 0.25 11.775 ;
			LAYER	M2 ;
			RECT	0 11.675 0.25 11.775 ;
			LAYER	M3 ;
			RECT	0 11.675 0.25 11.775 ;
		END

		ANTENNAGATEAREA 0.014 ;
		ANTENNADIFFAREA 0.018 ;
		ANTENNAPARTIALMETALAREA 0.025 ;
	END d[7]

	PIN d[80]
		USE SIGNAL ;
		DIRECTION INPUT ;
		SHAPE ABUTMENT ;
		PORT
			LAYER	M1 ;
			RECT	0 137.45 0.25 137.55 ;
			LAYER	M2 ;
			RECT	0 137.45 0.25 137.55 ;
			LAYER	M3 ;
			RECT	0 137.45 0.25 137.55 ;
		END

		ANTENNAGATEAREA 0.014 ;
		ANTENNADIFFAREA 0.018 ;
		ANTENNAPARTIALMETALAREA 0.025 ;
	END d[80]

	PIN d[81]
		USE SIGNAL ;
		DIRECTION INPUT ;
		SHAPE ABUTMENT ;
		PORT
			LAYER	M1 ;
			RECT	0 139.24 0.25 139.34 ;
			LAYER	M2 ;
			RECT	0 139.24 0.25 139.34 ;
			LAYER	M3 ;
			RECT	0 139.24 0.25 139.34 ;
		END

		ANTENNAGATEAREA 0.014 ;
		ANTENNADIFFAREA 0.018 ;
		ANTENNAPARTIALMETALAREA 0.025 ;
	END d[81]

	PIN d[82]
		USE SIGNAL ;
		DIRECTION INPUT ;
		SHAPE ABUTMENT ;
		PORT
			LAYER	M1 ;
			RECT	0 140.29 0.25 140.39 ;
			LAYER	M2 ;
			RECT	0 140.29 0.25 140.39 ;
			LAYER	M3 ;
			RECT	0 140.29 0.25 140.39 ;
		END

		ANTENNAGATEAREA 0.014 ;
		ANTENNADIFFAREA 0.018 ;
		ANTENNAPARTIALMETALAREA 0.025 ;
	END d[82]

	PIN d[83]
		USE SIGNAL ;
		DIRECTION INPUT ;
		SHAPE ABUTMENT ;
		PORT
			LAYER	M1 ;
			RECT	0 142.08 0.25 142.18 ;
			LAYER	M2 ;
			RECT	0 142.08 0.25 142.18 ;
			LAYER	M3 ;
			RECT	0 142.08 0.25 142.18 ;
		END

		ANTENNAGATEAREA 0.014 ;
		ANTENNADIFFAREA 0.018 ;
		ANTENNAPARTIALMETALAREA 0.025 ;
	END d[83]

	PIN d[84]
		USE SIGNAL ;
		DIRECTION INPUT ;
		SHAPE ABUTMENT ;
		PORT
			LAYER	M1 ;
			RECT	0 143.13 0.25 143.23 ;
			LAYER	M2 ;
			RECT	0 143.13 0.25 143.23 ;
			LAYER	M3 ;
			RECT	0 143.13 0.25 143.23 ;
		END

		ANTENNAGATEAREA 0.014 ;
		ANTENNADIFFAREA 0.018 ;
		ANTENNAPARTIALMETALAREA 0.025 ;
	END d[84]

	PIN d[85]
		USE SIGNAL ;
		DIRECTION INPUT ;
		SHAPE ABUTMENT ;
		PORT
			LAYER	M1 ;
			RECT	0 144.92 0.25 145.02 ;
			LAYER	M2 ;
			RECT	0 144.92 0.25 145.02 ;
			LAYER	M3 ;
			RECT	0 144.92 0.25 145.02 ;
		END

		ANTENNAGATEAREA 0.014 ;
		ANTENNADIFFAREA 0.018 ;
		ANTENNAPARTIALMETALAREA 0.025 ;
	END d[85]

	PIN d[86]
		USE SIGNAL ;
		DIRECTION INPUT ;
		SHAPE ABUTMENT ;
		PORT
			LAYER	M1 ;
			RECT	0 145.97 0.25 146.07 ;
			LAYER	M2 ;
			RECT	0 145.97 0.25 146.07 ;
			LAYER	M3 ;
			RECT	0 145.97 0.25 146.07 ;
		END

		ANTENNAGATEAREA 0.014 ;
		ANTENNADIFFAREA 0.018 ;
		ANTENNAPARTIALMETALAREA 0.025 ;
	END d[86]

	PIN d[87]
		USE SIGNAL ;
		DIRECTION INPUT ;
		SHAPE ABUTMENT ;
		PORT
			LAYER	M1 ;
			RECT	0 147.76 0.25 147.86 ;
			LAYER	M2 ;
			RECT	0 147.76 0.25 147.86 ;
			LAYER	M3 ;
			RECT	0 147.76 0.25 147.86 ;
		END

		ANTENNAGATEAREA 0.014 ;
		ANTENNADIFFAREA 0.018 ;
		ANTENNAPARTIALMETALAREA 0.025 ;
	END d[87]

	PIN d[88]
		USE SIGNAL ;
		DIRECTION INPUT ;
		SHAPE ABUTMENT ;
		PORT
			LAYER	M1 ;
			RECT	0 148.81 0.25 148.91 ;
			LAYER	M2 ;
			RECT	0 148.81 0.25 148.91 ;
			LAYER	M3 ;
			RECT	0 148.81 0.25 148.91 ;
		END

		ANTENNAGATEAREA 0.014 ;
		ANTENNADIFFAREA 0.018 ;
		ANTENNAPARTIALMETALAREA 0.025 ;
	END d[88]

	PIN d[89]
		USE SIGNAL ;
		DIRECTION INPUT ;
		SHAPE ABUTMENT ;
		PORT
			LAYER	M1 ;
			RECT	0 150.6 0.25 150.7 ;
			LAYER	M2 ;
			RECT	0 150.6 0.25 150.7 ;
			LAYER	M3 ;
			RECT	0 150.6 0.25 150.7 ;
		END

		ANTENNAGATEAREA 0.014 ;
		ANTENNADIFFAREA 0.018 ;
		ANTENNAPARTIALMETALAREA 0.025 ;
	END d[89]

	PIN d[8]
		USE SIGNAL ;
		DIRECTION INPUT ;
		SHAPE ABUTMENT ;
		PORT
			LAYER	M1 ;
			RECT	0 12.725 0.25 12.825 ;
			LAYER	M2 ;
			RECT	0 12.725 0.25 12.825 ;
			LAYER	M3 ;
			RECT	0 12.725 0.25 12.825 ;
		END

		ANTENNAGATEAREA 0.014 ;
		ANTENNADIFFAREA 0.018 ;
		ANTENNAPARTIALMETALAREA 0.025 ;
	END d[8]

	PIN d[90]
		USE SIGNAL ;
		DIRECTION INPUT ;
		SHAPE ABUTMENT ;
		PORT
			LAYER	M1 ;
			RECT	0 151.65 0.25 151.75 ;
			LAYER	M2 ;
			RECT	0 151.65 0.25 151.75 ;
			LAYER	M3 ;
			RECT	0 151.65 0.25 151.75 ;
		END

		ANTENNAGATEAREA 0.014 ;
		ANTENNADIFFAREA 0.018 ;
		ANTENNAPARTIALMETALAREA 0.025 ;
	END d[90]

	PIN d[91]
		USE SIGNAL ;
		DIRECTION INPUT ;
		SHAPE ABUTMENT ;
		PORT
			LAYER	M1 ;
			RECT	0 153.44 0.25 153.54 ;
			LAYER	M2 ;
			RECT	0 153.44 0.25 153.54 ;
			LAYER	M3 ;
			RECT	0 153.44 0.25 153.54 ;
		END

		ANTENNAGATEAREA 0.014 ;
		ANTENNADIFFAREA 0.018 ;
		ANTENNAPARTIALMETALAREA 0.025 ;
	END d[91]

	PIN d[92]
		USE SIGNAL ;
		DIRECTION INPUT ;
		SHAPE ABUTMENT ;
		PORT
			LAYER	M1 ;
			RECT	0 154.49 0.25 154.59 ;
			LAYER	M2 ;
			RECT	0 154.49 0.25 154.59 ;
			LAYER	M3 ;
			RECT	0 154.49 0.25 154.59 ;
		END

		ANTENNAGATEAREA 0.014 ;
		ANTENNADIFFAREA 0.018 ;
		ANTENNAPARTIALMETALAREA 0.025 ;
	END d[92]

	PIN d[93]
		USE SIGNAL ;
		DIRECTION INPUT ;
		SHAPE ABUTMENT ;
		PORT
			LAYER	M1 ;
			RECT	0 156.28 0.25 156.38 ;
			LAYER	M2 ;
			RECT	0 156.28 0.25 156.38 ;
			LAYER	M3 ;
			RECT	0 156.28 0.25 156.38 ;
		END

		ANTENNAGATEAREA 0.014 ;
		ANTENNADIFFAREA 0.018 ;
		ANTENNAPARTIALMETALAREA 0.025 ;
	END d[93]

	PIN d[94]
		USE SIGNAL ;
		DIRECTION INPUT ;
		SHAPE ABUTMENT ;
		PORT
			LAYER	M1 ;
			RECT	0 157.33 0.25 157.43 ;
			LAYER	M2 ;
			RECT	0 157.33 0.25 157.43 ;
			LAYER	M3 ;
			RECT	0 157.33 0.25 157.43 ;
		END

		ANTENNAGATEAREA 0.014 ;
		ANTENNADIFFAREA 0.018 ;
		ANTENNAPARTIALMETALAREA 0.025 ;
	END d[94]

	PIN d[95]
		USE SIGNAL ;
		DIRECTION INPUT ;
		SHAPE ABUTMENT ;
		PORT
			LAYER	M1 ;
			RECT	0 159.12 0.25 159.22 ;
			LAYER	M2 ;
			RECT	0 159.12 0.25 159.22 ;
			LAYER	M3 ;
			RECT	0 159.12 0.25 159.22 ;
		END

		ANTENNAGATEAREA 0.014 ;
		ANTENNADIFFAREA 0.018 ;
		ANTENNAPARTIALMETALAREA 0.025 ;
	END d[95]

	PIN d[96]
		USE SIGNAL ;
		DIRECTION INPUT ;
		SHAPE ABUTMENT ;
		PORT
			LAYER	M1 ;
			RECT	0 160.17 0.25 160.27 ;
			LAYER	M2 ;
			RECT	0 160.17 0.25 160.27 ;
			LAYER	M3 ;
			RECT	0 160.17 0.25 160.27 ;
		END

		ANTENNAGATEAREA 0.014 ;
		ANTENNADIFFAREA 0.018 ;
		ANTENNAPARTIALMETALAREA 0.025 ;
	END d[96]

	PIN d[97]
		USE SIGNAL ;
		DIRECTION INPUT ;
		SHAPE ABUTMENT ;
		PORT
			LAYER	M1 ;
			RECT	0 161.96 0.25 162.06 ;
			LAYER	M2 ;
			RECT	0 161.96 0.25 162.06 ;
			LAYER	M3 ;
			RECT	0 161.96 0.25 162.06 ;
		END

		ANTENNAGATEAREA 0.014 ;
		ANTENNADIFFAREA 0.018 ;
		ANTENNAPARTIALMETALAREA 0.025 ;
	END d[97]

	PIN d[98]
		USE SIGNAL ;
		DIRECTION INPUT ;
		SHAPE ABUTMENT ;
		PORT
			LAYER	M1 ;
			RECT	0 163.01 0.25 163.11 ;
			LAYER	M2 ;
			RECT	0 163.01 0.25 163.11 ;
			LAYER	M3 ;
			RECT	0 163.01 0.25 163.11 ;
		END

		ANTENNAGATEAREA 0.014 ;
		ANTENNADIFFAREA 0.018 ;
		ANTENNAPARTIALMETALAREA 0.025 ;
	END d[98]

	PIN d[99]
		USE SIGNAL ;
		DIRECTION INPUT ;
		SHAPE ABUTMENT ;
		PORT
			LAYER	M1 ;
			RECT	0 164.8 0.25 164.9 ;
			LAYER	M2 ;
			RECT	0 164.8 0.25 164.9 ;
			LAYER	M3 ;
			RECT	0 164.8 0.25 164.9 ;
		END

		ANTENNAGATEAREA 0.014 ;
		ANTENNADIFFAREA 0.018 ;
		ANTENNAPARTIALMETALAREA 0.025 ;
	END d[99]

	PIN d[9]
		USE SIGNAL ;
		DIRECTION INPUT ;
		SHAPE ABUTMENT ;
		PORT
			LAYER	M1 ;
			RECT	0 14.515 0.25 14.615 ;
			LAYER	M2 ;
			RECT	0 14.515 0.25 14.615 ;
			LAYER	M3 ;
			RECT	0 14.515 0.25 14.615 ;
		END

		ANTENNAGATEAREA 0.014 ;
		ANTENNADIFFAREA 0.018 ;
		ANTENNAPARTIALMETALAREA 0.025 ;
	END d[9]

	PIN ema[0]
		USE SIGNAL ;
		DIRECTION INPUT ;
		SHAPE ABUTMENT ;
		PORT
			LAYER	M1 ;
			RECT	0 106.105 0.25 106.205 ;
			LAYER	M2 ;
			RECT	0 106.105 0.25 106.205 ;
			LAYER	M3 ;
			RECT	0 106.105 0.25 106.205 ;
		END

		ANTENNAGATEAREA 0.014 ;
		ANTENNADIFFAREA 0.018 ;
		ANTENNAPARTIALMETALAREA 0.025 ;
	END ema[0]

	PIN ema[1]
		USE SIGNAL ;
		DIRECTION INPUT ;
		SHAPE ABUTMENT ;
		PORT
			LAYER	M1 ;
			RECT	0 105.905 0.25 106.005 ;
			LAYER	M2 ;
			RECT	0 105.905 0.25 106.005 ;
			LAYER	M3 ;
			RECT	0 105.905 0.25 106.005 ;
		END

		ANTENNAGATEAREA 0.014 ;
		ANTENNADIFFAREA 0.018 ;
		ANTENNAPARTIALMETALAREA 0.025 ;
	END ema[1]

	PIN ema[2]
		USE SIGNAL ;
		DIRECTION INPUT ;
		SHAPE ABUTMENT ;
		PORT
			LAYER	M1 ;
			RECT	0 105.705 0.25 105.805 ;
			LAYER	M2 ;
			RECT	0 105.705 0.25 105.805 ;
			LAYER	M3 ;
			RECT	0 105.705 0.25 105.805 ;
		END

		ANTENNAGATEAREA 0.014 ;
		ANTENNADIFFAREA 0.018 ;
		ANTENNAPARTIALMETALAREA 0.025 ;
	END ema[2]

	PIN emas
		USE SIGNAL ;
		DIRECTION INPUT ;
		SHAPE ABUTMENT ;
		PORT
			LAYER	M1 ;
			RECT	0 112.76 0.25 112.86 ;
			LAYER	M2 ;
			RECT	0 112.76 0.25 112.86 ;
			LAYER	M3 ;
			RECT	0 112.76 0.25 112.86 ;
		END

		ANTENNAGATEAREA 0.014 ;
		ANTENNADIFFAREA 0.018 ;
		ANTENNAPARTIALMETALAREA 0.025 ;
	END emas

	PIN emaw[0]
		USE SIGNAL ;
		DIRECTION INPUT ;
		SHAPE ABUTMENT ;
		PORT
			LAYER	M2 ;
			RECT	0 99.695 0.25 99.795 ;
			LAYER	M3 ;
			RECT	0 99.695 0.25 99.795 ;
		END

		ANTENNAGATEAREA 0.014 ;
		ANTENNADIFFAREA 0.018 ;
		ANTENNAPARTIALMETALAREA 0.025 ;
	END emaw[0]

	PIN emaw[1]
		USE SIGNAL ;
		DIRECTION INPUT ;
		SHAPE ABUTMENT ;
		PORT
			LAYER	M1 ;
			RECT	0 99.89 0.25 99.99 ;
			LAYER	M2 ;
			RECT	0 99.89 0.25 99.99 ;
			LAYER	M3 ;
			RECT	0 99.89 0.25 99.99 ;
		END

		ANTENNAGATEAREA 0.014 ;
		ANTENNADIFFAREA 0.018 ;
		ANTENNAPARTIALMETALAREA 0.025 ;
	END emaw[1]

	PIN q[0]
		USE SIGNAL ;
		DIRECTION OUTPUT ;
		SHAPE ABUTMENT ;
		PORT
			LAYER	M1 ;
			RECT	0 1.995 0.25 2.095 ;
			LAYER	M2 ;
			RECT	0 1.995 0.25 2.095 ;
			LAYER	M3 ;
			RECT	0 1.995 0.25 2.095 ;
		END

		ANTENNADIFFAREA 0.018 ;
		ANTENNAPARTIALMETALAREA 0.025 ;
	END q[0]

	PIN q[100]
		USE SIGNAL ;
		DIRECTION OUTPUT ;
		SHAPE ABUTMENT ;
		PORT
			LAYER	M1 ;
			RECT	0 166.48 0.25 166.58 ;
			LAYER	M2 ;
			RECT	0 166.48 0.25 166.58 ;
			LAYER	M3 ;
			RECT	0 166.48 0.25 166.58 ;
		END

		ANTENNADIFFAREA 0.018 ;
		ANTENNAPARTIALMETALAREA 0.025 ;
	END q[100]

	PIN q[101]
		USE SIGNAL ;
		DIRECTION OUTPUT ;
		SHAPE ABUTMENT ;
		PORT
			LAYER	M1 ;
			RECT	0 167.01 0.25 167.11 ;
			LAYER	M2 ;
			RECT	0 167.01 0.25 167.11 ;
			LAYER	M3 ;
			RECT	0 167.01 0.25 167.11 ;
		END

		ANTENNADIFFAREA 0.018 ;
		ANTENNAPARTIALMETALAREA 0.025 ;
	END q[101]

	PIN q[102]
		USE SIGNAL ;
		DIRECTION OUTPUT ;
		SHAPE ABUTMENT ;
		PORT
			LAYER	M1 ;
			RECT	0 169.32 0.25 169.42 ;
			LAYER	M2 ;
			RECT	0 169.32 0.25 169.42 ;
			LAYER	M3 ;
			RECT	0 169.32 0.25 169.42 ;
		END

		ANTENNADIFFAREA 0.018 ;
		ANTENNAPARTIALMETALAREA 0.025 ;
	END q[102]

	PIN q[103]
		USE SIGNAL ;
		DIRECTION OUTPUT ;
		SHAPE ABUTMENT ;
		PORT
			LAYER	M1 ;
			RECT	0 169.85 0.25 169.95 ;
			LAYER	M2 ;
			RECT	0 169.85 0.25 169.95 ;
			LAYER	M3 ;
			RECT	0 169.85 0.25 169.95 ;
		END

		ANTENNADIFFAREA 0.018 ;
		ANTENNAPARTIALMETALAREA 0.025 ;
	END q[103]

	PIN q[104]
		USE SIGNAL ;
		DIRECTION OUTPUT ;
		SHAPE ABUTMENT ;
		PORT
			LAYER	M1 ;
			RECT	0 172.16 0.25 172.26 ;
			LAYER	M2 ;
			RECT	0 172.16 0.25 172.26 ;
			LAYER	M3 ;
			RECT	0 172.16 0.25 172.26 ;
		END

		ANTENNADIFFAREA 0.018 ;
		ANTENNAPARTIALMETALAREA 0.025 ;
	END q[104]

	PIN q[105]
		USE SIGNAL ;
		DIRECTION OUTPUT ;
		SHAPE ABUTMENT ;
		PORT
			LAYER	M1 ;
			RECT	0 172.69 0.25 172.79 ;
			LAYER	M2 ;
			RECT	0 172.69 0.25 172.79 ;
			LAYER	M3 ;
			RECT	0 172.69 0.25 172.79 ;
		END

		ANTENNADIFFAREA 0.018 ;
		ANTENNAPARTIALMETALAREA 0.025 ;
	END q[105]

	PIN q[106]
		USE SIGNAL ;
		DIRECTION OUTPUT ;
		SHAPE ABUTMENT ;
		PORT
			LAYER	M1 ;
			RECT	0 175 0.25 175.1 ;
			LAYER	M2 ;
			RECT	0 175 0.25 175.1 ;
			LAYER	M3 ;
			RECT	0 175 0.25 175.1 ;
		END

		ANTENNADIFFAREA 0.018 ;
		ANTENNAPARTIALMETALAREA 0.025 ;
	END q[106]

	PIN q[107]
		USE SIGNAL ;
		DIRECTION OUTPUT ;
		SHAPE ABUTMENT ;
		PORT
			LAYER	M1 ;
			RECT	0 175.53 0.25 175.63 ;
			LAYER	M2 ;
			RECT	0 175.53 0.25 175.63 ;
			LAYER	M3 ;
			RECT	0 175.53 0.25 175.63 ;
		END

		ANTENNADIFFAREA 0.018 ;
		ANTENNAPARTIALMETALAREA 0.025 ;
	END q[107]

	PIN q[108]
		USE SIGNAL ;
		DIRECTION OUTPUT ;
		SHAPE ABUTMENT ;
		PORT
			LAYER	M1 ;
			RECT	0 177.84 0.25 177.94 ;
			LAYER	M2 ;
			RECT	0 177.84 0.25 177.94 ;
			LAYER	M3 ;
			RECT	0 177.84 0.25 177.94 ;
		END

		ANTENNADIFFAREA 0.018 ;
		ANTENNAPARTIALMETALAREA 0.025 ;
	END q[108]

	PIN q[109]
		USE SIGNAL ;
		DIRECTION OUTPUT ;
		SHAPE ABUTMENT ;
		PORT
			LAYER	M1 ;
			RECT	0 178.37 0.25 178.47 ;
			LAYER	M2 ;
			RECT	0 178.37 0.25 178.47 ;
			LAYER	M3 ;
			RECT	0 178.37 0.25 178.47 ;
		END

		ANTENNADIFFAREA 0.018 ;
		ANTENNAPARTIALMETALAREA 0.025 ;
	END q[109]

	PIN q[10]
		USE SIGNAL ;
		DIRECTION OUTPUT ;
		SHAPE ABUTMENT ;
		PORT
			LAYER	M1 ;
			RECT	0 16.195 0.25 16.295 ;
			LAYER	M2 ;
			RECT	0 16.195 0.25 16.295 ;
			LAYER	M3 ;
			RECT	0 16.195 0.25 16.295 ;
		END

		ANTENNADIFFAREA 0.018 ;
		ANTENNAPARTIALMETALAREA 0.025 ;
	END q[10]

	PIN q[110]
		USE SIGNAL ;
		DIRECTION OUTPUT ;
		SHAPE ABUTMENT ;
		PORT
			LAYER	M1 ;
			RECT	0 180.68 0.25 180.78 ;
			LAYER	M2 ;
			RECT	0 180.68 0.25 180.78 ;
			LAYER	M3 ;
			RECT	0 180.68 0.25 180.78 ;
		END

		ANTENNADIFFAREA 0.018 ;
		ANTENNAPARTIALMETALAREA 0.025 ;
	END q[110]

	PIN q[111]
		USE SIGNAL ;
		DIRECTION OUTPUT ;
		SHAPE ABUTMENT ;
		PORT
			LAYER	M1 ;
			RECT	0 181.21 0.25 181.31 ;
			LAYER	M2 ;
			RECT	0 181.21 0.25 181.31 ;
			LAYER	M3 ;
			RECT	0 181.21 0.25 181.31 ;
		END

		ANTENNADIFFAREA 0.018 ;
		ANTENNAPARTIALMETALAREA 0.025 ;
	END q[111]

	PIN q[112]
		USE SIGNAL ;
		DIRECTION OUTPUT ;
		SHAPE ABUTMENT ;
		PORT
			LAYER	M1 ;
			RECT	0 183.52 0.25 183.62 ;
			LAYER	M2 ;
			RECT	0 183.52 0.25 183.62 ;
			LAYER	M3 ;
			RECT	0 183.52 0.25 183.62 ;
		END

		ANTENNADIFFAREA 0.018 ;
		ANTENNAPARTIALMETALAREA 0.025 ;
	END q[112]

	PIN q[113]
		USE SIGNAL ;
		DIRECTION OUTPUT ;
		SHAPE ABUTMENT ;
		PORT
			LAYER	M1 ;
			RECT	0 184.05 0.25 184.15 ;
			LAYER	M2 ;
			RECT	0 184.05 0.25 184.15 ;
			LAYER	M3 ;
			RECT	0 184.05 0.25 184.15 ;
		END

		ANTENNADIFFAREA 0.018 ;
		ANTENNAPARTIALMETALAREA 0.025 ;
	END q[113]

	PIN q[114]
		USE SIGNAL ;
		DIRECTION OUTPUT ;
		SHAPE ABUTMENT ;
		PORT
			LAYER	M1 ;
			RECT	0 186.36 0.25 186.46 ;
			LAYER	M2 ;
			RECT	0 186.36 0.25 186.46 ;
			LAYER	M3 ;
			RECT	0 186.36 0.25 186.46 ;
		END

		ANTENNADIFFAREA 0.018 ;
		ANTENNAPARTIALMETALAREA 0.025 ;
	END q[114]

	PIN q[115]
		USE SIGNAL ;
		DIRECTION OUTPUT ;
		SHAPE ABUTMENT ;
		PORT
			LAYER	M1 ;
			RECT	0 186.89 0.25 186.99 ;
			LAYER	M2 ;
			RECT	0 186.89 0.25 186.99 ;
			LAYER	M3 ;
			RECT	0 186.89 0.25 186.99 ;
		END

		ANTENNADIFFAREA 0.018 ;
		ANTENNAPARTIALMETALAREA 0.025 ;
	END q[115]

	PIN q[116]
		USE SIGNAL ;
		DIRECTION OUTPUT ;
		SHAPE ABUTMENT ;
		PORT
			LAYER	M1 ;
			RECT	0 189.2 0.25 189.3 ;
			LAYER	M2 ;
			RECT	0 189.2 0.25 189.3 ;
			LAYER	M3 ;
			RECT	0 189.2 0.25 189.3 ;
		END

		ANTENNADIFFAREA 0.018 ;
		ANTENNAPARTIALMETALAREA 0.025 ;
	END q[116]

	PIN q[117]
		USE SIGNAL ;
		DIRECTION OUTPUT ;
		SHAPE ABUTMENT ;
		PORT
			LAYER	M1 ;
			RECT	0 189.73 0.25 189.83 ;
			LAYER	M2 ;
			RECT	0 189.73 0.25 189.83 ;
			LAYER	M3 ;
			RECT	0 189.73 0.25 189.83 ;
		END

		ANTENNADIFFAREA 0.018 ;
		ANTENNAPARTIALMETALAREA 0.025 ;
	END q[117]

	PIN q[118]
		USE SIGNAL ;
		DIRECTION OUTPUT ;
		SHAPE ABUTMENT ;
		PORT
			LAYER	M1 ;
			RECT	0 192.04 0.25 192.14 ;
			LAYER	M2 ;
			RECT	0 192.04 0.25 192.14 ;
			LAYER	M3 ;
			RECT	0 192.04 0.25 192.14 ;
		END

		ANTENNADIFFAREA 0.018 ;
		ANTENNAPARTIALMETALAREA 0.025 ;
	END q[118]

	PIN q[119]
		USE SIGNAL ;
		DIRECTION OUTPUT ;
		SHAPE ABUTMENT ;
		PORT
			LAYER	M1 ;
			RECT	0 192.57 0.25 192.67 ;
			LAYER	M2 ;
			RECT	0 192.57 0.25 192.67 ;
			LAYER	M3 ;
			RECT	0 192.57 0.25 192.67 ;
		END

		ANTENNADIFFAREA 0.018 ;
		ANTENNAPARTIALMETALAREA 0.025 ;
	END q[119]

	PIN q[11]
		USE SIGNAL ;
		DIRECTION OUTPUT ;
		SHAPE ABUTMENT ;
		PORT
			LAYER	M1 ;
			RECT	0 16.725 0.25 16.825 ;
			LAYER	M2 ;
			RECT	0 16.725 0.25 16.825 ;
			LAYER	M3 ;
			RECT	0 16.725 0.25 16.825 ;
		END

		ANTENNADIFFAREA 0.018 ;
		ANTENNAPARTIALMETALAREA 0.025 ;
	END q[11]

	PIN q[120]
		USE SIGNAL ;
		DIRECTION OUTPUT ;
		SHAPE ABUTMENT ;
		PORT
			LAYER	M1 ;
			RECT	0 194.88 0.25 194.98 ;
			LAYER	M2 ;
			RECT	0 194.88 0.25 194.98 ;
			LAYER	M3 ;
			RECT	0 194.88 0.25 194.98 ;
		END

		ANTENNADIFFAREA 0.018 ;
		ANTENNAPARTIALMETALAREA 0.025 ;
	END q[120]

	PIN q[121]
		USE SIGNAL ;
		DIRECTION OUTPUT ;
		SHAPE ABUTMENT ;
		PORT
			LAYER	M1 ;
			RECT	0 195.41 0.25 195.51 ;
			LAYER	M2 ;
			RECT	0 195.41 0.25 195.51 ;
			LAYER	M3 ;
			RECT	0 195.41 0.25 195.51 ;
		END

		ANTENNADIFFAREA 0.018 ;
		ANTENNAPARTIALMETALAREA 0.025 ;
	END q[121]

	PIN q[122]
		USE SIGNAL ;
		DIRECTION OUTPUT ;
		SHAPE ABUTMENT ;
		PORT
			LAYER	M1 ;
			RECT	0 197.72 0.25 197.82 ;
			LAYER	M2 ;
			RECT	0 197.72 0.25 197.82 ;
			LAYER	M3 ;
			RECT	0 197.72 0.25 197.82 ;
		END

		ANTENNADIFFAREA 0.018 ;
		ANTENNAPARTIALMETALAREA 0.025 ;
	END q[122]

	PIN q[123]
		USE SIGNAL ;
		DIRECTION OUTPUT ;
		SHAPE ABUTMENT ;
		PORT
			LAYER	M1 ;
			RECT	0 198.25 0.25 198.35 ;
			LAYER	M2 ;
			RECT	0 198.25 0.25 198.35 ;
			LAYER	M3 ;
			RECT	0 198.25 0.25 198.35 ;
		END

		ANTENNADIFFAREA 0.018 ;
		ANTENNAPARTIALMETALAREA 0.025 ;
	END q[123]

	PIN q[124]
		USE SIGNAL ;
		DIRECTION OUTPUT ;
		SHAPE ABUTMENT ;
		PORT
			LAYER	M1 ;
			RECT	0 200.56 0.25 200.66 ;
			LAYER	M2 ;
			RECT	0 200.56 0.25 200.66 ;
			LAYER	M3 ;
			RECT	0 200.56 0.25 200.66 ;
		END

		ANTENNADIFFAREA 0.018 ;
		ANTENNAPARTIALMETALAREA 0.025 ;
	END q[124]

	PIN q[125]
		USE SIGNAL ;
		DIRECTION OUTPUT ;
		SHAPE ABUTMENT ;
		PORT
			LAYER	M1 ;
			RECT	0 201.09 0.25 201.19 ;
			LAYER	M2 ;
			RECT	0 201.09 0.25 201.19 ;
			LAYER	M3 ;
			RECT	0 201.09 0.25 201.19 ;
		END

		ANTENNADIFFAREA 0.018 ;
		ANTENNAPARTIALMETALAREA 0.025 ;
	END q[125]

	PIN q[126]
		USE SIGNAL ;
		DIRECTION OUTPUT ;
		SHAPE ABUTMENT ;
		PORT
			LAYER	M1 ;
			RECT	0 203.4 0.25 203.5 ;
			LAYER	M2 ;
			RECT	0 203.4 0.25 203.5 ;
			LAYER	M3 ;
			RECT	0 203.4 0.25 203.5 ;
		END

		ANTENNADIFFAREA 0.018 ;
		ANTENNAPARTIALMETALAREA 0.025 ;
	END q[126]

	PIN q[127]
		USE SIGNAL ;
		DIRECTION OUTPUT ;
		SHAPE ABUTMENT ;
		PORT
			LAYER	M1 ;
			RECT	0 203.93 0.25 204.03 ;
			LAYER	M2 ;
			RECT	0 203.93 0.25 204.03 ;
			LAYER	M3 ;
			RECT	0 203.93 0.25 204.03 ;
		END

		ANTENNADIFFAREA 0.018 ;
		ANTENNAPARTIALMETALAREA 0.025 ;
	END q[127]

	PIN q[12]
		USE SIGNAL ;
		DIRECTION OUTPUT ;
		SHAPE ABUTMENT ;
		PORT
			LAYER	M1 ;
			RECT	0 19.035 0.25 19.135 ;
			LAYER	M2 ;
			RECT	0 19.035 0.25 19.135 ;
			LAYER	M3 ;
			RECT	0 19.035 0.25 19.135 ;
		END

		ANTENNADIFFAREA 0.018 ;
		ANTENNAPARTIALMETALAREA 0.025 ;
	END q[12]

	PIN q[13]
		USE SIGNAL ;
		DIRECTION OUTPUT ;
		SHAPE ABUTMENT ;
		PORT
			LAYER	M1 ;
			RECT	0 19.565 0.25 19.665 ;
			LAYER	M2 ;
			RECT	0 19.565 0.25 19.665 ;
			LAYER	M3 ;
			RECT	0 19.565 0.25 19.665 ;
		END

		ANTENNADIFFAREA 0.018 ;
		ANTENNAPARTIALMETALAREA 0.025 ;
	END q[13]

	PIN q[14]
		USE SIGNAL ;
		DIRECTION OUTPUT ;
		SHAPE ABUTMENT ;
		PORT
			LAYER	M1 ;
			RECT	0 21.875 0.25 21.975 ;
			LAYER	M2 ;
			RECT	0 21.875 0.25 21.975 ;
			LAYER	M3 ;
			RECT	0 21.875 0.25 21.975 ;
		END

		ANTENNADIFFAREA 0.018 ;
		ANTENNAPARTIALMETALAREA 0.025 ;
	END q[14]

	PIN q[15]
		USE SIGNAL ;
		DIRECTION OUTPUT ;
		SHAPE ABUTMENT ;
		PORT
			LAYER	M1 ;
			RECT	0 22.405 0.25 22.505 ;
			LAYER	M2 ;
			RECT	0 22.405 0.25 22.505 ;
			LAYER	M3 ;
			RECT	0 22.405 0.25 22.505 ;
		END

		ANTENNADIFFAREA 0.018 ;
		ANTENNAPARTIALMETALAREA 0.025 ;
	END q[15]

	PIN q[16]
		USE SIGNAL ;
		DIRECTION OUTPUT ;
		SHAPE ABUTMENT ;
		PORT
			LAYER	M1 ;
			RECT	0 24.715 0.25 24.815 ;
			LAYER	M2 ;
			RECT	0 24.715 0.25 24.815 ;
			LAYER	M3 ;
			RECT	0 24.715 0.25 24.815 ;
		END

		ANTENNADIFFAREA 0.018 ;
		ANTENNAPARTIALMETALAREA 0.025 ;
	END q[16]

	PIN q[17]
		USE SIGNAL ;
		DIRECTION OUTPUT ;
		SHAPE ABUTMENT ;
		PORT
			LAYER	M1 ;
			RECT	0 25.245 0.25 25.345 ;
			LAYER	M2 ;
			RECT	0 25.245 0.25 25.345 ;
			LAYER	M3 ;
			RECT	0 25.245 0.25 25.345 ;
		END

		ANTENNADIFFAREA 0.018 ;
		ANTENNAPARTIALMETALAREA 0.025 ;
	END q[17]

	PIN q[18]
		USE SIGNAL ;
		DIRECTION OUTPUT ;
		SHAPE ABUTMENT ;
		PORT
			LAYER	M1 ;
			RECT	0 27.555 0.25 27.655 ;
			LAYER	M2 ;
			RECT	0 27.555 0.25 27.655 ;
			LAYER	M3 ;
			RECT	0 27.555 0.25 27.655 ;
		END

		ANTENNADIFFAREA 0.018 ;
		ANTENNAPARTIALMETALAREA 0.025 ;
	END q[18]

	PIN q[19]
		USE SIGNAL ;
		DIRECTION OUTPUT ;
		SHAPE ABUTMENT ;
		PORT
			LAYER	M1 ;
			RECT	0 28.085 0.25 28.185 ;
			LAYER	M2 ;
			RECT	0 28.085 0.25 28.185 ;
			LAYER	M3 ;
			RECT	0 28.085 0.25 28.185 ;
		END

		ANTENNADIFFAREA 0.018 ;
		ANTENNAPARTIALMETALAREA 0.025 ;
	END q[19]

	PIN q[1]
		USE SIGNAL ;
		DIRECTION OUTPUT ;
		SHAPE ABUTMENT ;
		PORT
			LAYER	M1 ;
			RECT	0 2.525 0.25 2.625 ;
			LAYER	M2 ;
			RECT	0 2.525 0.25 2.625 ;
			LAYER	M3 ;
			RECT	0 2.525 0.25 2.625 ;
		END

		ANTENNADIFFAREA 0.018 ;
		ANTENNAPARTIALMETALAREA 0.025 ;
	END q[1]

	PIN q[20]
		USE SIGNAL ;
		DIRECTION OUTPUT ;
		SHAPE ABUTMENT ;
		PORT
			LAYER	M1 ;
			RECT	0 30.395 0.25 30.495 ;
			LAYER	M2 ;
			RECT	0 30.395 0.25 30.495 ;
			LAYER	M3 ;
			RECT	0 30.395 0.25 30.495 ;
		END

		ANTENNADIFFAREA 0.018 ;
		ANTENNAPARTIALMETALAREA 0.025 ;
	END q[20]

	PIN q[21]
		USE SIGNAL ;
		DIRECTION OUTPUT ;
		SHAPE ABUTMENT ;
		PORT
			LAYER	M1 ;
			RECT	0 30.925 0.25 31.025 ;
			LAYER	M2 ;
			RECT	0 30.925 0.25 31.025 ;
			LAYER	M3 ;
			RECT	0 30.925 0.25 31.025 ;
		END

		ANTENNADIFFAREA 0.018 ;
		ANTENNAPARTIALMETALAREA 0.025 ;
	END q[21]

	PIN q[22]
		USE SIGNAL ;
		DIRECTION OUTPUT ;
		SHAPE ABUTMENT ;
		PORT
			LAYER	M1 ;
			RECT	0 33.235 0.25 33.335 ;
			LAYER	M2 ;
			RECT	0 33.235 0.25 33.335 ;
			LAYER	M3 ;
			RECT	0 33.235 0.25 33.335 ;
		END

		ANTENNADIFFAREA 0.018 ;
		ANTENNAPARTIALMETALAREA 0.025 ;
	END q[22]

	PIN q[23]
		USE SIGNAL ;
		DIRECTION OUTPUT ;
		SHAPE ABUTMENT ;
		PORT
			LAYER	M1 ;
			RECT	0 33.765 0.25 33.865 ;
			LAYER	M2 ;
			RECT	0 33.765 0.25 33.865 ;
			LAYER	M3 ;
			RECT	0 33.765 0.25 33.865 ;
		END

		ANTENNADIFFAREA 0.018 ;
		ANTENNAPARTIALMETALAREA 0.025 ;
	END q[23]

	PIN q[24]
		USE SIGNAL ;
		DIRECTION OUTPUT ;
		SHAPE ABUTMENT ;
		PORT
			LAYER	M1 ;
			RECT	0 36.075 0.25 36.175 ;
			LAYER	M2 ;
			RECT	0 36.075 0.25 36.175 ;
			LAYER	M3 ;
			RECT	0 36.075 0.25 36.175 ;
		END

		ANTENNADIFFAREA 0.018 ;
		ANTENNAPARTIALMETALAREA 0.025 ;
	END q[24]

	PIN q[25]
		USE SIGNAL ;
		DIRECTION OUTPUT ;
		SHAPE ABUTMENT ;
		PORT
			LAYER	M1 ;
			RECT	0 36.605 0.25 36.705 ;
			LAYER	M2 ;
			RECT	0 36.605 0.25 36.705 ;
			LAYER	M3 ;
			RECT	0 36.605 0.25 36.705 ;
		END

		ANTENNADIFFAREA 0.018 ;
		ANTENNAPARTIALMETALAREA 0.025 ;
	END q[25]

	PIN q[26]
		USE SIGNAL ;
		DIRECTION OUTPUT ;
		SHAPE ABUTMENT ;
		PORT
			LAYER	M1 ;
			RECT	0 38.915 0.25 39.015 ;
			LAYER	M2 ;
			RECT	0 38.915 0.25 39.015 ;
			LAYER	M3 ;
			RECT	0 38.915 0.25 39.015 ;
		END

		ANTENNADIFFAREA 0.018 ;
		ANTENNAPARTIALMETALAREA 0.025 ;
	END q[26]

	PIN q[27]
		USE SIGNAL ;
		DIRECTION OUTPUT ;
		SHAPE ABUTMENT ;
		PORT
			LAYER	M1 ;
			RECT	0 39.445 0.25 39.545 ;
			LAYER	M2 ;
			RECT	0 39.445 0.25 39.545 ;
			LAYER	M3 ;
			RECT	0 39.445 0.25 39.545 ;
		END

		ANTENNADIFFAREA 0.018 ;
		ANTENNAPARTIALMETALAREA 0.025 ;
	END q[27]

	PIN q[28]
		USE SIGNAL ;
		DIRECTION OUTPUT ;
		SHAPE ABUTMENT ;
		PORT
			LAYER	M1 ;
			RECT	0 41.755 0.25 41.855 ;
			LAYER	M2 ;
			RECT	0 41.755 0.25 41.855 ;
			LAYER	M3 ;
			RECT	0 41.755 0.25 41.855 ;
		END

		ANTENNADIFFAREA 0.018 ;
		ANTENNAPARTIALMETALAREA 0.025 ;
	END q[28]

	PIN q[29]
		USE SIGNAL ;
		DIRECTION OUTPUT ;
		SHAPE ABUTMENT ;
		PORT
			LAYER	M1 ;
			RECT	0 42.285 0.25 42.385 ;
			LAYER	M2 ;
			RECT	0 42.285 0.25 42.385 ;
			LAYER	M3 ;
			RECT	0 42.285 0.25 42.385 ;
		END

		ANTENNADIFFAREA 0.018 ;
		ANTENNAPARTIALMETALAREA 0.025 ;
	END q[29]

	PIN q[2]
		USE SIGNAL ;
		DIRECTION OUTPUT ;
		SHAPE ABUTMENT ;
		PORT
			LAYER	M1 ;
			RECT	0 4.835 0.25 4.935 ;
			LAYER	M2 ;
			RECT	0 4.835 0.25 4.935 ;
			LAYER	M3 ;
			RECT	0 4.835 0.25 4.935 ;
		END

		ANTENNADIFFAREA 0.018 ;
		ANTENNAPARTIALMETALAREA 0.025 ;
	END q[2]

	PIN q[30]
		USE SIGNAL ;
		DIRECTION OUTPUT ;
		SHAPE ABUTMENT ;
		PORT
			LAYER	M1 ;
			RECT	0 44.595 0.25 44.695 ;
			LAYER	M2 ;
			RECT	0 44.595 0.25 44.695 ;
			LAYER	M3 ;
			RECT	0 44.595 0.25 44.695 ;
		END

		ANTENNADIFFAREA 0.018 ;
		ANTENNAPARTIALMETALAREA 0.025 ;
	END q[30]

	PIN q[31]
		USE SIGNAL ;
		DIRECTION OUTPUT ;
		SHAPE ABUTMENT ;
		PORT
			LAYER	M1 ;
			RECT	0 45.125 0.25 45.225 ;
			LAYER	M2 ;
			RECT	0 45.125 0.25 45.225 ;
			LAYER	M3 ;
			RECT	0 45.125 0.25 45.225 ;
		END

		ANTENNADIFFAREA 0.018 ;
		ANTENNAPARTIALMETALAREA 0.025 ;
	END q[31]

	PIN q[32]
		USE SIGNAL ;
		DIRECTION OUTPUT ;
		SHAPE ABUTMENT ;
		PORT
			LAYER	M1 ;
			RECT	0 47.435 0.25 47.535 ;
			LAYER	M2 ;
			RECT	0 47.435 0.25 47.535 ;
			LAYER	M3 ;
			RECT	0 47.435 0.25 47.535 ;
		END

		ANTENNADIFFAREA 0.018 ;
		ANTENNAPARTIALMETALAREA 0.025 ;
	END q[32]

	PIN q[33]
		USE SIGNAL ;
		DIRECTION OUTPUT ;
		SHAPE ABUTMENT ;
		PORT
			LAYER	M1 ;
			RECT	0 47.965 0.25 48.065 ;
			LAYER	M2 ;
			RECT	0 47.965 0.25 48.065 ;
			LAYER	M3 ;
			RECT	0 47.965 0.25 48.065 ;
		END

		ANTENNADIFFAREA 0.018 ;
		ANTENNAPARTIALMETALAREA 0.025 ;
	END q[33]

	PIN q[34]
		USE SIGNAL ;
		DIRECTION OUTPUT ;
		SHAPE ABUTMENT ;
		PORT
			LAYER	M1 ;
			RECT	0 50.275 0.25 50.375 ;
			LAYER	M2 ;
			RECT	0 50.275 0.25 50.375 ;
			LAYER	M3 ;
			RECT	0 50.275 0.25 50.375 ;
		END

		ANTENNADIFFAREA 0.018 ;
		ANTENNAPARTIALMETALAREA 0.025 ;
	END q[34]

	PIN q[35]
		USE SIGNAL ;
		DIRECTION OUTPUT ;
		SHAPE ABUTMENT ;
		PORT
			LAYER	M1 ;
			RECT	0 50.805 0.25 50.905 ;
			LAYER	M2 ;
			RECT	0 50.805 0.25 50.905 ;
			LAYER	M3 ;
			RECT	0 50.805 0.25 50.905 ;
		END

		ANTENNADIFFAREA 0.018 ;
		ANTENNAPARTIALMETALAREA 0.025 ;
	END q[35]

	PIN q[36]
		USE SIGNAL ;
		DIRECTION OUTPUT ;
		SHAPE ABUTMENT ;
		PORT
			LAYER	M1 ;
			RECT	0 53.115 0.25 53.215 ;
			LAYER	M2 ;
			RECT	0 53.115 0.25 53.215 ;
			LAYER	M3 ;
			RECT	0 53.115 0.25 53.215 ;
		END

		ANTENNADIFFAREA 0.018 ;
		ANTENNAPARTIALMETALAREA 0.025 ;
	END q[36]

	PIN q[37]
		USE SIGNAL ;
		DIRECTION OUTPUT ;
		SHAPE ABUTMENT ;
		PORT
			LAYER	M1 ;
			RECT	0 53.645 0.25 53.745 ;
			LAYER	M2 ;
			RECT	0 53.645 0.25 53.745 ;
			LAYER	M3 ;
			RECT	0 53.645 0.25 53.745 ;
		END

		ANTENNADIFFAREA 0.018 ;
		ANTENNAPARTIALMETALAREA 0.025 ;
	END q[37]

	PIN q[38]
		USE SIGNAL ;
		DIRECTION OUTPUT ;
		SHAPE ABUTMENT ;
		PORT
			LAYER	M1 ;
			RECT	0 55.955 0.25 56.055 ;
			LAYER	M2 ;
			RECT	0 55.955 0.25 56.055 ;
			LAYER	M3 ;
			RECT	0 55.955 0.25 56.055 ;
		END

		ANTENNADIFFAREA 0.018 ;
		ANTENNAPARTIALMETALAREA 0.025 ;
	END q[38]

	PIN q[39]
		USE SIGNAL ;
		DIRECTION OUTPUT ;
		SHAPE ABUTMENT ;
		PORT
			LAYER	M1 ;
			RECT	0 56.485 0.25 56.585 ;
			LAYER	M2 ;
			RECT	0 56.485 0.25 56.585 ;
			LAYER	M3 ;
			RECT	0 56.485 0.25 56.585 ;
		END

		ANTENNADIFFAREA 0.018 ;
		ANTENNAPARTIALMETALAREA 0.025 ;
	END q[39]

	PIN q[3]
		USE SIGNAL ;
		DIRECTION OUTPUT ;
		SHAPE ABUTMENT ;
		PORT
			LAYER	M1 ;
			RECT	0 5.365 0.25 5.465 ;
			LAYER	M2 ;
			RECT	0 5.365 0.25 5.465 ;
			LAYER	M3 ;
			RECT	0 5.365 0.25 5.465 ;
		END

		ANTENNADIFFAREA 0.018 ;
		ANTENNAPARTIALMETALAREA 0.025 ;
	END q[3]

	PIN q[40]
		USE SIGNAL ;
		DIRECTION OUTPUT ;
		SHAPE ABUTMENT ;
		PORT
			LAYER	M1 ;
			RECT	0 58.795 0.25 58.895 ;
			LAYER	M2 ;
			RECT	0 58.795 0.25 58.895 ;
			LAYER	M3 ;
			RECT	0 58.795 0.25 58.895 ;
		END

		ANTENNADIFFAREA 0.018 ;
		ANTENNAPARTIALMETALAREA 0.025 ;
	END q[40]

	PIN q[41]
		USE SIGNAL ;
		DIRECTION OUTPUT ;
		SHAPE ABUTMENT ;
		PORT
			LAYER	M1 ;
			RECT	0 59.325 0.25 59.425 ;
			LAYER	M2 ;
			RECT	0 59.325 0.25 59.425 ;
			LAYER	M3 ;
			RECT	0 59.325 0.25 59.425 ;
		END

		ANTENNADIFFAREA 0.018 ;
		ANTENNAPARTIALMETALAREA 0.025 ;
	END q[41]

	PIN q[42]
		USE SIGNAL ;
		DIRECTION OUTPUT ;
		SHAPE ABUTMENT ;
		PORT
			LAYER	M1 ;
			RECT	0 61.635 0.25 61.735 ;
			LAYER	M2 ;
			RECT	0 61.635 0.25 61.735 ;
			LAYER	M3 ;
			RECT	0 61.635 0.25 61.735 ;
		END

		ANTENNADIFFAREA 0.018 ;
		ANTENNAPARTIALMETALAREA 0.025 ;
	END q[42]

	PIN q[43]
		USE SIGNAL ;
		DIRECTION OUTPUT ;
		SHAPE ABUTMENT ;
		PORT
			LAYER	M1 ;
			RECT	0 62.165 0.25 62.265 ;
			LAYER	M2 ;
			RECT	0 62.165 0.25 62.265 ;
			LAYER	M3 ;
			RECT	0 62.165 0.25 62.265 ;
		END

		ANTENNADIFFAREA 0.018 ;
		ANTENNAPARTIALMETALAREA 0.025 ;
	END q[43]

	PIN q[44]
		USE SIGNAL ;
		DIRECTION OUTPUT ;
		SHAPE ABUTMENT ;
		PORT
			LAYER	M1 ;
			RECT	0 64.475 0.25 64.575 ;
			LAYER	M2 ;
			RECT	0 64.475 0.25 64.575 ;
			LAYER	M3 ;
			RECT	0 64.475 0.25 64.575 ;
		END

		ANTENNADIFFAREA 0.018 ;
		ANTENNAPARTIALMETALAREA 0.025 ;
	END q[44]

	PIN q[45]
		USE SIGNAL ;
		DIRECTION OUTPUT ;
		SHAPE ABUTMENT ;
		PORT
			LAYER	M1 ;
			RECT	0 65.005 0.25 65.105 ;
			LAYER	M2 ;
			RECT	0 65.005 0.25 65.105 ;
			LAYER	M3 ;
			RECT	0 65.005 0.25 65.105 ;
		END

		ANTENNADIFFAREA 0.018 ;
		ANTENNAPARTIALMETALAREA 0.025 ;
	END q[45]

	PIN q[46]
		USE SIGNAL ;
		DIRECTION OUTPUT ;
		SHAPE ABUTMENT ;
		PORT
			LAYER	M1 ;
			RECT	0 67.315 0.25 67.415 ;
			LAYER	M2 ;
			RECT	0 67.315 0.25 67.415 ;
			LAYER	M3 ;
			RECT	0 67.315 0.25 67.415 ;
		END

		ANTENNADIFFAREA 0.018 ;
		ANTENNAPARTIALMETALAREA 0.025 ;
	END q[46]

	PIN q[47]
		USE SIGNAL ;
		DIRECTION OUTPUT ;
		SHAPE ABUTMENT ;
		PORT
			LAYER	M1 ;
			RECT	0 67.845 0.25 67.945 ;
			LAYER	M2 ;
			RECT	0 67.845 0.25 67.945 ;
			LAYER	M3 ;
			RECT	0 67.845 0.25 67.945 ;
		END

		ANTENNADIFFAREA 0.018 ;
		ANTENNAPARTIALMETALAREA 0.025 ;
	END q[47]

	PIN q[48]
		USE SIGNAL ;
		DIRECTION OUTPUT ;
		SHAPE ABUTMENT ;
		PORT
			LAYER	M1 ;
			RECT	0 70.155 0.25 70.255 ;
			LAYER	M2 ;
			RECT	0 70.155 0.25 70.255 ;
			LAYER	M3 ;
			RECT	0 70.155 0.25 70.255 ;
		END

		ANTENNADIFFAREA 0.018 ;
		ANTENNAPARTIALMETALAREA 0.025 ;
	END q[48]

	PIN q[49]
		USE SIGNAL ;
		DIRECTION OUTPUT ;
		SHAPE ABUTMENT ;
		PORT
			LAYER	M1 ;
			RECT	0 70.685 0.25 70.785 ;
			LAYER	M2 ;
			RECT	0 70.685 0.25 70.785 ;
			LAYER	M3 ;
			RECT	0 70.685 0.25 70.785 ;
		END

		ANTENNADIFFAREA 0.018 ;
		ANTENNAPARTIALMETALAREA 0.025 ;
	END q[49]

	PIN q[4]
		USE SIGNAL ;
		DIRECTION OUTPUT ;
		SHAPE ABUTMENT ;
		PORT
			LAYER	M1 ;
			RECT	0 7.675 0.25 7.775 ;
			LAYER	M2 ;
			RECT	0 7.675 0.25 7.775 ;
			LAYER	M3 ;
			RECT	0 7.675 0.25 7.775 ;
		END

		ANTENNADIFFAREA 0.018 ;
		ANTENNAPARTIALMETALAREA 0.025 ;
	END q[4]

	PIN q[50]
		USE SIGNAL ;
		DIRECTION OUTPUT ;
		SHAPE ABUTMENT ;
		PORT
			LAYER	M1 ;
			RECT	0 72.995 0.25 73.095 ;
			LAYER	M2 ;
			RECT	0 72.995 0.25 73.095 ;
			LAYER	M3 ;
			RECT	0 72.995 0.25 73.095 ;
		END

		ANTENNADIFFAREA 0.018 ;
		ANTENNAPARTIALMETALAREA 0.025 ;
	END q[50]

	PIN q[51]
		USE SIGNAL ;
		DIRECTION OUTPUT ;
		SHAPE ABUTMENT ;
		PORT
			LAYER	M1 ;
			RECT	0 73.525 0.25 73.625 ;
			LAYER	M2 ;
			RECT	0 73.525 0.25 73.625 ;
			LAYER	M3 ;
			RECT	0 73.525 0.25 73.625 ;
		END

		ANTENNADIFFAREA 0.018 ;
		ANTENNAPARTIALMETALAREA 0.025 ;
	END q[51]

	PIN q[52]
		USE SIGNAL ;
		DIRECTION OUTPUT ;
		SHAPE ABUTMENT ;
		PORT
			LAYER	M1 ;
			RECT	0 75.835 0.25 75.935 ;
			LAYER	M2 ;
			RECT	0 75.835 0.25 75.935 ;
			LAYER	M3 ;
			RECT	0 75.835 0.25 75.935 ;
		END

		ANTENNADIFFAREA 0.018 ;
		ANTENNAPARTIALMETALAREA 0.025 ;
	END q[52]

	PIN q[53]
		USE SIGNAL ;
		DIRECTION OUTPUT ;
		SHAPE ABUTMENT ;
		PORT
			LAYER	M1 ;
			RECT	0 76.365 0.25 76.465 ;
			LAYER	M2 ;
			RECT	0 76.365 0.25 76.465 ;
			LAYER	M3 ;
			RECT	0 76.365 0.25 76.465 ;
		END

		ANTENNADIFFAREA 0.018 ;
		ANTENNAPARTIALMETALAREA 0.025 ;
	END q[53]

	PIN q[54]
		USE SIGNAL ;
		DIRECTION OUTPUT ;
		SHAPE ABUTMENT ;
		PORT
			LAYER	M1 ;
			RECT	0 78.675 0.25 78.775 ;
			LAYER	M2 ;
			RECT	0 78.675 0.25 78.775 ;
			LAYER	M3 ;
			RECT	0 78.675 0.25 78.775 ;
		END

		ANTENNADIFFAREA 0.018 ;
		ANTENNAPARTIALMETALAREA 0.025 ;
	END q[54]

	PIN q[55]
		USE SIGNAL ;
		DIRECTION OUTPUT ;
		SHAPE ABUTMENT ;
		PORT
			LAYER	M1 ;
			RECT	0 79.205 0.25 79.305 ;
			LAYER	M2 ;
			RECT	0 79.205 0.25 79.305 ;
			LAYER	M3 ;
			RECT	0 79.205 0.25 79.305 ;
		END

		ANTENNADIFFAREA 0.018 ;
		ANTENNAPARTIALMETALAREA 0.025 ;
	END q[55]

	PIN q[56]
		USE SIGNAL ;
		DIRECTION OUTPUT ;
		SHAPE ABUTMENT ;
		PORT
			LAYER	M1 ;
			RECT	0 81.515 0.25 81.615 ;
			LAYER	M2 ;
			RECT	0 81.515 0.25 81.615 ;
			LAYER	M3 ;
			RECT	0 81.515 0.25 81.615 ;
		END

		ANTENNADIFFAREA 0.018 ;
		ANTENNAPARTIALMETALAREA 0.025 ;
	END q[56]

	PIN q[57]
		USE SIGNAL ;
		DIRECTION OUTPUT ;
		SHAPE ABUTMENT ;
		PORT
			LAYER	M1 ;
			RECT	0 82.045 0.25 82.145 ;
			LAYER	M2 ;
			RECT	0 82.045 0.25 82.145 ;
			LAYER	M3 ;
			RECT	0 82.045 0.25 82.145 ;
		END

		ANTENNADIFFAREA 0.018 ;
		ANTENNAPARTIALMETALAREA 0.025 ;
	END q[57]

	PIN q[58]
		USE SIGNAL ;
		DIRECTION OUTPUT ;
		SHAPE ABUTMENT ;
		PORT
			LAYER	M1 ;
			RECT	0 84.355 0.25 84.455 ;
			LAYER	M2 ;
			RECT	0 84.355 0.25 84.455 ;
			LAYER	M3 ;
			RECT	0 84.355 0.25 84.455 ;
		END

		ANTENNADIFFAREA 0.018 ;
		ANTENNAPARTIALMETALAREA 0.025 ;
	END q[58]

	PIN q[59]
		USE SIGNAL ;
		DIRECTION OUTPUT ;
		SHAPE ABUTMENT ;
		PORT
			LAYER	M1 ;
			RECT	0 84.885 0.25 84.985 ;
			LAYER	M2 ;
			RECT	0 84.885 0.25 84.985 ;
			LAYER	M3 ;
			RECT	0 84.885 0.25 84.985 ;
		END

		ANTENNADIFFAREA 0.018 ;
		ANTENNAPARTIALMETALAREA 0.025 ;
	END q[59]

	PIN q[5]
		USE SIGNAL ;
		DIRECTION OUTPUT ;
		SHAPE ABUTMENT ;
		PORT
			LAYER	M1 ;
			RECT	0 8.205 0.25 8.305 ;
			LAYER	M2 ;
			RECT	0 8.205 0.25 8.305 ;
			LAYER	M3 ;
			RECT	0 8.205 0.25 8.305 ;
		END

		ANTENNADIFFAREA 0.018 ;
		ANTENNAPARTIALMETALAREA 0.025 ;
	END q[5]

	PIN q[60]
		USE SIGNAL ;
		DIRECTION OUTPUT ;
		SHAPE ABUTMENT ;
		PORT
			LAYER	M1 ;
			RECT	0 87.195 0.25 87.295 ;
			LAYER	M2 ;
			RECT	0 87.195 0.25 87.295 ;
			LAYER	M3 ;
			RECT	0 87.195 0.25 87.295 ;
		END

		ANTENNADIFFAREA 0.018 ;
		ANTENNAPARTIALMETALAREA 0.025 ;
	END q[60]

	PIN q[61]
		USE SIGNAL ;
		DIRECTION OUTPUT ;
		SHAPE ABUTMENT ;
		PORT
			LAYER	M1 ;
			RECT	0 87.725 0.25 87.825 ;
			LAYER	M2 ;
			RECT	0 87.725 0.25 87.825 ;
			LAYER	M3 ;
			RECT	0 87.725 0.25 87.825 ;
		END

		ANTENNADIFFAREA 0.018 ;
		ANTENNAPARTIALMETALAREA 0.025 ;
	END q[61]

	PIN q[62]
		USE SIGNAL ;
		DIRECTION OUTPUT ;
		SHAPE ABUTMENT ;
		PORT
			LAYER	M1 ;
			RECT	0 90.035 0.25 90.135 ;
			LAYER	M2 ;
			RECT	0 90.035 0.25 90.135 ;
			LAYER	M3 ;
			RECT	0 90.035 0.25 90.135 ;
		END

		ANTENNADIFFAREA 0.018 ;
		ANTENNAPARTIALMETALAREA 0.025 ;
	END q[62]

	PIN q[63]
		USE SIGNAL ;
		DIRECTION OUTPUT ;
		SHAPE ABUTMENT ;
		PORT
			LAYER	M1 ;
			RECT	0 90.565 0.25 90.665 ;
			LAYER	M2 ;
			RECT	0 90.565 0.25 90.665 ;
			LAYER	M3 ;
			RECT	0 90.565 0.25 90.665 ;
		END

		ANTENNADIFFAREA 0.018 ;
		ANTENNAPARTIALMETALAREA 0.025 ;
	END q[63]

	PIN q[64]
		USE SIGNAL ;
		DIRECTION OUTPUT ;
		SHAPE ABUTMENT ;
		PORT
			LAYER	M1 ;
			RECT	0 115.36 0.25 115.46 ;
			LAYER	M2 ;
			RECT	0 115.36 0.25 115.46 ;
			LAYER	M3 ;
			RECT	0 115.36 0.25 115.46 ;
		END

		ANTENNADIFFAREA 0.018 ;
		ANTENNAPARTIALMETALAREA 0.025 ;
	END q[64]

	PIN q[65]
		USE SIGNAL ;
		DIRECTION OUTPUT ;
		SHAPE ABUTMENT ;
		PORT
			LAYER	M1 ;
			RECT	0 115.89 0.25 115.99 ;
			LAYER	M2 ;
			RECT	0 115.89 0.25 115.99 ;
			LAYER	M3 ;
			RECT	0 115.89 0.25 115.99 ;
		END

		ANTENNADIFFAREA 0.018 ;
		ANTENNAPARTIALMETALAREA 0.025 ;
	END q[65]

	PIN q[66]
		USE SIGNAL ;
		DIRECTION OUTPUT ;
		SHAPE ABUTMENT ;
		PORT
			LAYER	M1 ;
			RECT	0 118.2 0.25 118.3 ;
			LAYER	M2 ;
			RECT	0 118.2 0.25 118.3 ;
			LAYER	M3 ;
			RECT	0 118.2 0.25 118.3 ;
		END

		ANTENNADIFFAREA 0.018 ;
		ANTENNAPARTIALMETALAREA 0.025 ;
	END q[66]

	PIN q[67]
		USE SIGNAL ;
		DIRECTION OUTPUT ;
		SHAPE ABUTMENT ;
		PORT
			LAYER	M1 ;
			RECT	0 118.73 0.25 118.83 ;
			LAYER	M2 ;
			RECT	0 118.73 0.25 118.83 ;
			LAYER	M3 ;
			RECT	0 118.73 0.25 118.83 ;
		END

		ANTENNADIFFAREA 0.018 ;
		ANTENNAPARTIALMETALAREA 0.025 ;
	END q[67]

	PIN q[68]
		USE SIGNAL ;
		DIRECTION OUTPUT ;
		SHAPE ABUTMENT ;
		PORT
			LAYER	M1 ;
			RECT	0 121.04 0.25 121.14 ;
			LAYER	M2 ;
			RECT	0 121.04 0.25 121.14 ;
			LAYER	M3 ;
			RECT	0 121.04 0.25 121.14 ;
		END

		ANTENNADIFFAREA 0.018 ;
		ANTENNAPARTIALMETALAREA 0.025 ;
	END q[68]

	PIN q[69]
		USE SIGNAL ;
		DIRECTION OUTPUT ;
		SHAPE ABUTMENT ;
		PORT
			LAYER	M1 ;
			RECT	0 121.57 0.25 121.67 ;
			LAYER	M2 ;
			RECT	0 121.57 0.25 121.67 ;
			LAYER	M3 ;
			RECT	0 121.57 0.25 121.67 ;
		END

		ANTENNADIFFAREA 0.018 ;
		ANTENNAPARTIALMETALAREA 0.025 ;
	END q[69]

	PIN q[6]
		USE SIGNAL ;
		DIRECTION OUTPUT ;
		SHAPE ABUTMENT ;
		PORT
			LAYER	M1 ;
			RECT	0 10.515 0.25 10.615 ;
			LAYER	M2 ;
			RECT	0 10.515 0.25 10.615 ;
			LAYER	M3 ;
			RECT	0 10.515 0.25 10.615 ;
		END

		ANTENNADIFFAREA 0.018 ;
		ANTENNAPARTIALMETALAREA 0.025 ;
	END q[6]

	PIN q[70]
		USE SIGNAL ;
		DIRECTION OUTPUT ;
		SHAPE ABUTMENT ;
		PORT
			LAYER	M1 ;
			RECT	0 123.88 0.25 123.98 ;
			LAYER	M2 ;
			RECT	0 123.88 0.25 123.98 ;
			LAYER	M3 ;
			RECT	0 123.88 0.25 123.98 ;
		END

		ANTENNADIFFAREA 0.018 ;
		ANTENNAPARTIALMETALAREA 0.025 ;
	END q[70]

	PIN q[71]
		USE SIGNAL ;
		DIRECTION OUTPUT ;
		SHAPE ABUTMENT ;
		PORT
			LAYER	M1 ;
			RECT	0 124.41 0.25 124.51 ;
			LAYER	M2 ;
			RECT	0 124.41 0.25 124.51 ;
			LAYER	M3 ;
			RECT	0 124.41 0.25 124.51 ;
		END

		ANTENNADIFFAREA 0.018 ;
		ANTENNAPARTIALMETALAREA 0.025 ;
	END q[71]

	PIN q[72]
		USE SIGNAL ;
		DIRECTION OUTPUT ;
		SHAPE ABUTMENT ;
		PORT
			LAYER	M1 ;
			RECT	0 126.72 0.25 126.82 ;
			LAYER	M2 ;
			RECT	0 126.72 0.25 126.82 ;
			LAYER	M3 ;
			RECT	0 126.72 0.25 126.82 ;
		END

		ANTENNADIFFAREA 0.018 ;
		ANTENNAPARTIALMETALAREA 0.025 ;
	END q[72]

	PIN q[73]
		USE SIGNAL ;
		DIRECTION OUTPUT ;
		SHAPE ABUTMENT ;
		PORT
			LAYER	M1 ;
			RECT	0 127.25 0.25 127.35 ;
			LAYER	M2 ;
			RECT	0 127.25 0.25 127.35 ;
			LAYER	M3 ;
			RECT	0 127.25 0.25 127.35 ;
		END

		ANTENNADIFFAREA 0.018 ;
		ANTENNAPARTIALMETALAREA 0.025 ;
	END q[73]

	PIN q[74]
		USE SIGNAL ;
		DIRECTION OUTPUT ;
		SHAPE ABUTMENT ;
		PORT
			LAYER	M1 ;
			RECT	0 129.56 0.25 129.66 ;
			LAYER	M2 ;
			RECT	0 129.56 0.25 129.66 ;
			LAYER	M3 ;
			RECT	0 129.56 0.25 129.66 ;
		END

		ANTENNADIFFAREA 0.018 ;
		ANTENNAPARTIALMETALAREA 0.025 ;
	END q[74]

	PIN q[75]
		USE SIGNAL ;
		DIRECTION OUTPUT ;
		SHAPE ABUTMENT ;
		PORT
			LAYER	M1 ;
			RECT	0 130.09 0.25 130.19 ;
			LAYER	M2 ;
			RECT	0 130.09 0.25 130.19 ;
			LAYER	M3 ;
			RECT	0 130.09 0.25 130.19 ;
		END

		ANTENNADIFFAREA 0.018 ;
		ANTENNAPARTIALMETALAREA 0.025 ;
	END q[75]

	PIN q[76]
		USE SIGNAL ;
		DIRECTION OUTPUT ;
		SHAPE ABUTMENT ;
		PORT
			LAYER	M1 ;
			RECT	0 132.4 0.25 132.5 ;
			LAYER	M2 ;
			RECT	0 132.4 0.25 132.5 ;
			LAYER	M3 ;
			RECT	0 132.4 0.25 132.5 ;
		END

		ANTENNADIFFAREA 0.018 ;
		ANTENNAPARTIALMETALAREA 0.025 ;
	END q[76]

	PIN q[77]
		USE SIGNAL ;
		DIRECTION OUTPUT ;
		SHAPE ABUTMENT ;
		PORT
			LAYER	M1 ;
			RECT	0 132.93 0.25 133.03 ;
			LAYER	M2 ;
			RECT	0 132.93 0.25 133.03 ;
			LAYER	M3 ;
			RECT	0 132.93 0.25 133.03 ;
		END

		ANTENNADIFFAREA 0.018 ;
		ANTENNAPARTIALMETALAREA 0.025 ;
	END q[77]

	PIN q[78]
		USE SIGNAL ;
		DIRECTION OUTPUT ;
		SHAPE ABUTMENT ;
		PORT
			LAYER	M1 ;
			RECT	0 135.24 0.25 135.34 ;
			LAYER	M2 ;
			RECT	0 135.24 0.25 135.34 ;
			LAYER	M3 ;
			RECT	0 135.24 0.25 135.34 ;
		END

		ANTENNADIFFAREA 0.018 ;
		ANTENNAPARTIALMETALAREA 0.025 ;
	END q[78]

	PIN q[79]
		USE SIGNAL ;
		DIRECTION OUTPUT ;
		SHAPE ABUTMENT ;
		PORT
			LAYER	M1 ;
			RECT	0 135.77 0.25 135.87 ;
			LAYER	M2 ;
			RECT	0 135.77 0.25 135.87 ;
			LAYER	M3 ;
			RECT	0 135.77 0.25 135.87 ;
		END

		ANTENNADIFFAREA 0.018 ;
		ANTENNAPARTIALMETALAREA 0.025 ;
	END q[79]

	PIN q[7]
		USE SIGNAL ;
		DIRECTION OUTPUT ;
		SHAPE ABUTMENT ;
		PORT
			LAYER	M1 ;
			RECT	0 11.045 0.25 11.145 ;
			LAYER	M2 ;
			RECT	0 11.045 0.25 11.145 ;
			LAYER	M3 ;
			RECT	0 11.045 0.25 11.145 ;
		END

		ANTENNADIFFAREA 0.018 ;
		ANTENNAPARTIALMETALAREA 0.025 ;
	END q[7]

	PIN q[80]
		USE SIGNAL ;
		DIRECTION OUTPUT ;
		SHAPE ABUTMENT ;
		PORT
			LAYER	M1 ;
			RECT	0 138.08 0.25 138.18 ;
			LAYER	M2 ;
			RECT	0 138.08 0.25 138.18 ;
			LAYER	M3 ;
			RECT	0 138.08 0.25 138.18 ;
		END

		ANTENNADIFFAREA 0.018 ;
		ANTENNAPARTIALMETALAREA 0.025 ;
	END q[80]

	PIN q[81]
		USE SIGNAL ;
		DIRECTION OUTPUT ;
		SHAPE ABUTMENT ;
		PORT
			LAYER	M1 ;
			RECT	0 138.61 0.25 138.71 ;
			LAYER	M2 ;
			RECT	0 138.61 0.25 138.71 ;
			LAYER	M3 ;
			RECT	0 138.61 0.25 138.71 ;
		END

		ANTENNADIFFAREA 0.018 ;
		ANTENNAPARTIALMETALAREA 0.025 ;
	END q[81]

	PIN q[82]
		USE SIGNAL ;
		DIRECTION OUTPUT ;
		SHAPE ABUTMENT ;
		PORT
			LAYER	M1 ;
			RECT	0 140.92 0.25 141.02 ;
			LAYER	M2 ;
			RECT	0 140.92 0.25 141.02 ;
			LAYER	M3 ;
			RECT	0 140.92 0.25 141.02 ;
		END

		ANTENNADIFFAREA 0.018 ;
		ANTENNAPARTIALMETALAREA 0.025 ;
	END q[82]

	PIN q[83]
		USE SIGNAL ;
		DIRECTION OUTPUT ;
		SHAPE ABUTMENT ;
		PORT
			LAYER	M1 ;
			RECT	0 141.45 0.25 141.55 ;
			LAYER	M2 ;
			RECT	0 141.45 0.25 141.55 ;
			LAYER	M3 ;
			RECT	0 141.45 0.25 141.55 ;
		END

		ANTENNADIFFAREA 0.018 ;
		ANTENNAPARTIALMETALAREA 0.025 ;
	END q[83]

	PIN q[84]
		USE SIGNAL ;
		DIRECTION OUTPUT ;
		SHAPE ABUTMENT ;
		PORT
			LAYER	M1 ;
			RECT	0 143.76 0.25 143.86 ;
			LAYER	M2 ;
			RECT	0 143.76 0.25 143.86 ;
			LAYER	M3 ;
			RECT	0 143.76 0.25 143.86 ;
		END

		ANTENNADIFFAREA 0.018 ;
		ANTENNAPARTIALMETALAREA 0.025 ;
	END q[84]

	PIN q[85]
		USE SIGNAL ;
		DIRECTION OUTPUT ;
		SHAPE ABUTMENT ;
		PORT
			LAYER	M1 ;
			RECT	0 144.29 0.25 144.39 ;
			LAYER	M2 ;
			RECT	0 144.29 0.25 144.39 ;
			LAYER	M3 ;
			RECT	0 144.29 0.25 144.39 ;
		END

		ANTENNADIFFAREA 0.018 ;
		ANTENNAPARTIALMETALAREA 0.025 ;
	END q[85]

	PIN q[86]
		USE SIGNAL ;
		DIRECTION OUTPUT ;
		SHAPE ABUTMENT ;
		PORT
			LAYER	M1 ;
			RECT	0 146.6 0.25 146.7 ;
			LAYER	M2 ;
			RECT	0 146.6 0.25 146.7 ;
			LAYER	M3 ;
			RECT	0 146.6 0.25 146.7 ;
		END

		ANTENNADIFFAREA 0.018 ;
		ANTENNAPARTIALMETALAREA 0.025 ;
	END q[86]

	PIN q[87]
		USE SIGNAL ;
		DIRECTION OUTPUT ;
		SHAPE ABUTMENT ;
		PORT
			LAYER	M1 ;
			RECT	0 147.13 0.25 147.23 ;
			LAYER	M2 ;
			RECT	0 147.13 0.25 147.23 ;
			LAYER	M3 ;
			RECT	0 147.13 0.25 147.23 ;
		END

		ANTENNADIFFAREA 0.018 ;
		ANTENNAPARTIALMETALAREA 0.025 ;
	END q[87]

	PIN q[88]
		USE SIGNAL ;
		DIRECTION OUTPUT ;
		SHAPE ABUTMENT ;
		PORT
			LAYER	M1 ;
			RECT	0 149.44 0.25 149.54 ;
			LAYER	M2 ;
			RECT	0 149.44 0.25 149.54 ;
			LAYER	M3 ;
			RECT	0 149.44 0.25 149.54 ;
		END

		ANTENNADIFFAREA 0.018 ;
		ANTENNAPARTIALMETALAREA 0.025 ;
	END q[88]

	PIN q[89]
		USE SIGNAL ;
		DIRECTION OUTPUT ;
		SHAPE ABUTMENT ;
		PORT
			LAYER	M1 ;
			RECT	0 149.97 0.25 150.07 ;
			LAYER	M2 ;
			RECT	0 149.97 0.25 150.07 ;
			LAYER	M3 ;
			RECT	0 149.97 0.25 150.07 ;
		END

		ANTENNADIFFAREA 0.018 ;
		ANTENNAPARTIALMETALAREA 0.025 ;
	END q[89]

	PIN q[8]
		USE SIGNAL ;
		DIRECTION OUTPUT ;
		SHAPE ABUTMENT ;
		PORT
			LAYER	M1 ;
			RECT	0 13.355 0.25 13.455 ;
			LAYER	M2 ;
			RECT	0 13.355 0.25 13.455 ;
			LAYER	M3 ;
			RECT	0 13.355 0.25 13.455 ;
		END

		ANTENNADIFFAREA 0.018 ;
		ANTENNAPARTIALMETALAREA 0.025 ;
	END q[8]

	PIN q[90]
		USE SIGNAL ;
		DIRECTION OUTPUT ;
		SHAPE ABUTMENT ;
		PORT
			LAYER	M1 ;
			RECT	0 152.28 0.25 152.38 ;
			LAYER	M2 ;
			RECT	0 152.28 0.25 152.38 ;
			LAYER	M3 ;
			RECT	0 152.28 0.25 152.38 ;
		END

		ANTENNADIFFAREA 0.018 ;
		ANTENNAPARTIALMETALAREA 0.025 ;
	END q[90]

	PIN q[91]
		USE SIGNAL ;
		DIRECTION OUTPUT ;
		SHAPE ABUTMENT ;
		PORT
			LAYER	M1 ;
			RECT	0 152.81 0.25 152.91 ;
			LAYER	M2 ;
			RECT	0 152.81 0.25 152.91 ;
			LAYER	M3 ;
			RECT	0 152.81 0.25 152.91 ;
		END

		ANTENNADIFFAREA 0.018 ;
		ANTENNAPARTIALMETALAREA 0.025 ;
	END q[91]

	PIN q[92]
		USE SIGNAL ;
		DIRECTION OUTPUT ;
		SHAPE ABUTMENT ;
		PORT
			LAYER	M1 ;
			RECT	0 155.12 0.25 155.22 ;
			LAYER	M2 ;
			RECT	0 155.12 0.25 155.22 ;
			LAYER	M3 ;
			RECT	0 155.12 0.25 155.22 ;
		END

		ANTENNADIFFAREA 0.018 ;
		ANTENNAPARTIALMETALAREA 0.025 ;
	END q[92]

	PIN q[93]
		USE SIGNAL ;
		DIRECTION OUTPUT ;
		SHAPE ABUTMENT ;
		PORT
			LAYER	M1 ;
			RECT	0 155.65 0.25 155.75 ;
			LAYER	M2 ;
			RECT	0 155.65 0.25 155.75 ;
			LAYER	M3 ;
			RECT	0 155.65 0.25 155.75 ;
		END

		ANTENNADIFFAREA 0.018 ;
		ANTENNAPARTIALMETALAREA 0.025 ;
	END q[93]

	PIN q[94]
		USE SIGNAL ;
		DIRECTION OUTPUT ;
		SHAPE ABUTMENT ;
		PORT
			LAYER	M1 ;
			RECT	0 157.96 0.25 158.06 ;
			LAYER	M2 ;
			RECT	0 157.96 0.25 158.06 ;
			LAYER	M3 ;
			RECT	0 157.96 0.25 158.06 ;
		END

		ANTENNADIFFAREA 0.018 ;
		ANTENNAPARTIALMETALAREA 0.025 ;
	END q[94]

	PIN q[95]
		USE SIGNAL ;
		DIRECTION OUTPUT ;
		SHAPE ABUTMENT ;
		PORT
			LAYER	M1 ;
			RECT	0 158.49 0.25 158.59 ;
			LAYER	M2 ;
			RECT	0 158.49 0.25 158.59 ;
			LAYER	M3 ;
			RECT	0 158.49 0.25 158.59 ;
		END

		ANTENNADIFFAREA 0.018 ;
		ANTENNAPARTIALMETALAREA 0.025 ;
	END q[95]

	PIN q[96]
		USE SIGNAL ;
		DIRECTION OUTPUT ;
		SHAPE ABUTMENT ;
		PORT
			LAYER	M1 ;
			RECT	0 160.8 0.25 160.9 ;
			LAYER	M2 ;
			RECT	0 160.8 0.25 160.9 ;
			LAYER	M3 ;
			RECT	0 160.8 0.25 160.9 ;
		END

		ANTENNADIFFAREA 0.018 ;
		ANTENNAPARTIALMETALAREA 0.025 ;
	END q[96]

	PIN q[97]
		USE SIGNAL ;
		DIRECTION OUTPUT ;
		SHAPE ABUTMENT ;
		PORT
			LAYER	M1 ;
			RECT	0 161.33 0.25 161.43 ;
			LAYER	M2 ;
			RECT	0 161.33 0.25 161.43 ;
			LAYER	M3 ;
			RECT	0 161.33 0.25 161.43 ;
		END

		ANTENNADIFFAREA 0.018 ;
		ANTENNAPARTIALMETALAREA 0.025 ;
	END q[97]

	PIN q[98]
		USE SIGNAL ;
		DIRECTION OUTPUT ;
		SHAPE ABUTMENT ;
		PORT
			LAYER	M1 ;
			RECT	0 163.64 0.25 163.74 ;
			LAYER	M2 ;
			RECT	0 163.64 0.25 163.74 ;
			LAYER	M3 ;
			RECT	0 163.64 0.25 163.74 ;
		END

		ANTENNADIFFAREA 0.018 ;
		ANTENNAPARTIALMETALAREA 0.025 ;
	END q[98]

	PIN q[99]
		USE SIGNAL ;
		DIRECTION OUTPUT ;
		SHAPE ABUTMENT ;
		PORT
			LAYER	M1 ;
			RECT	0 164.17 0.25 164.27 ;
			LAYER	M2 ;
			RECT	0 164.17 0.25 164.27 ;
			LAYER	M3 ;
			RECT	0 164.17 0.25 164.27 ;
		END

		ANTENNADIFFAREA 0.018 ;
		ANTENNAPARTIALMETALAREA 0.025 ;
	END q[99]

	PIN q[9]
		USE SIGNAL ;
		DIRECTION OUTPUT ;
		SHAPE ABUTMENT ;
		PORT
			LAYER	M1 ;
			RECT	0 13.885 0.25 13.985 ;
			LAYER	M2 ;
			RECT	0 13.885 0.25 13.985 ;
			LAYER	M3 ;
			RECT	0 13.885 0.25 13.985 ;
		END

		ANTENNADIFFAREA 0.018 ;
		ANTENNAPARTIALMETALAREA 0.025 ;
	END q[9]

	PIN rawl
		USE SIGNAL ;
		DIRECTION INPUT ;
		SHAPE ABUTMENT ;
		PORT
			LAYER	M1 ;
			RECT	0 98.52 0.25 98.62 ;
			LAYER	M2 ;
			RECT	0 98.52 0.25 98.62 ;
			LAYER	M3 ;
			RECT	0 98.52 0.25 98.62 ;
		END

		ANTENNAGATEAREA 0.014 ;
		ANTENNADIFFAREA 0.018 ;
		ANTENNAPARTIALMETALAREA 0.025 ;
	END rawl

	PIN rawlm[0]
		USE SIGNAL ;
		DIRECTION INPUT ;
		SHAPE ABUTMENT ;
		PORT
			LAYER	M1 ;
			RECT	0 98.82 0.25 98.92 ;
			LAYER	M2 ;
			RECT	0 98.82 0.25 98.92 ;
			LAYER	M3 ;
			RECT	0 98.82 0.25 98.92 ;
		END

		ANTENNAGATEAREA 0.014 ;
		ANTENNADIFFAREA 0.018 ;
		ANTENNAPARTIALMETALAREA 0.025 ;
	END rawlm[0]

	PIN rawlm[1]
		USE SIGNAL ;
		DIRECTION INPUT ;
		SHAPE ABUTMENT ;
		PORT
			LAYER	M1 ;
			RECT	0 99.07 0.25 99.17 ;
			LAYER	M2 ;
			RECT	0 99.07 0.25 99.17 ;
			LAYER	M3 ;
			RECT	0 99.07 0.25 99.17 ;
		END

		ANTENNAGATEAREA 0.014 ;
		ANTENNADIFFAREA 0.018 ;
		ANTENNAPARTIALMETALAREA 0.025 ;
	END rawlm[1]

	PIN ret1n
		USE SIGNAL ;
		DIRECTION INPUT ;
		SHAPE ABUTMENT ;
		PORT
			LAYER	M1 ;
			RECT	0 94.065 0.25 94.165 ;
			LAYER	M2 ;
			RECT	0 94.065 0.25 94.165 ;
			LAYER	M3 ;
			RECT	0 94.065 0.25 94.165 ;
		END

		ANTENNAGATEAREA 0.014 ;
		ANTENNADIFFAREA 0.018 ;
		ANTENNAPARTIALMETALAREA 0.025 ;
	END ret1n

	PIN wabl
		USE SIGNAL ;
		DIRECTION INPUT ;
		SHAPE ABUTMENT ;
		PORT
			LAYER	M1 ;
			RECT	0 112.98 0.25 113.08 ;
			LAYER	M2 ;
			RECT	0 112.98 0.25 113.08 ;
			LAYER	M3 ;
			RECT	0 112.98 0.25 113.08 ;
		END

		ANTENNAGATEAREA 0.014 ;
		ANTENNADIFFAREA 0.018 ;
		ANTENNAPARTIALMETALAREA 0.025 ;
	END wabl

	PIN wablm[0]
		USE SIGNAL ;
		DIRECTION INPUT ;
		SHAPE ABUTMENT ;
		PORT
			LAYER	M1 ;
			RECT	0 109.465 0.25 109.565 ;
			LAYER	M2 ;
			RECT	0 109.465 0.25 109.565 ;
			LAYER	M3 ;
			RECT	0 109.465 0.25 109.565 ;
		END

		ANTENNAGATEAREA 0.014 ;
		ANTENNADIFFAREA 0.018 ;
		ANTENNAPARTIALMETALAREA 0.025 ;
	END wablm[0]

	PIN wablm[1]
		USE SIGNAL ;
		DIRECTION INPUT ;
		SHAPE ABUTMENT ;
		PORT
			LAYER	M1 ;
			RECT	0 104.495 0.25 104.595 ;
			LAYER	M2 ;
			RECT	0 104.495 0.25 104.595 ;
			LAYER	M3 ;
			RECT	0 104.495 0.25 104.595 ;
		END

		ANTENNAGATEAREA 0.014 ;
		ANTENNADIFFAREA 0.018 ;
		ANTENNAPARTIALMETALAREA 0.025 ;
	END wablm[1]

	PIN wen
		USE SIGNAL ;
		DIRECTION INPUT ;
		SHAPE ABUTMENT ;
		PORT
			LAYER	M1 ;
			RECT	0 98.025 0.25 98.125 ;
			LAYER	M2 ;
			RECT	0 98.025 0.25 98.125 ;
			LAYER	M3 ;
			RECT	0 98.025 0.25 98.125 ;
		END

		ANTENNAGATEAREA 0.014 ;
		ANTENNADIFFAREA 0.018 ;
		ANTENNAPARTIALMETALAREA 0.025 ;
	END wen

	OBS
		LAYER	M1 DESIGNRULEWIDTH 0.165 ;
		RECT	0.32 0.3 38.08 205.725 ;
		RECT	0 0 0.32 1.315 ;
		RECT	0 1.515 0.32 1.945 ;
		RECT	0 2.145 0.32 2.475 ;
		RECT	0 2.675 0.32 3.105 ;
		RECT	0 3.305 0.32 4.155 ;
		RECT	0 4.355 0.32 4.785 ;
		RECT	0 4.985 0.32 5.315 ;
		RECT	0 5.515 0.32 5.945 ;
		RECT	0 6.145 0.32 6.995 ;
		RECT	0 7.195 0.32 7.625 ;
		RECT	0 7.825 0.32 8.155 ;
		RECT	0 8.355 0.32 8.785 ;
		RECT	0 8.985 0.32 9.835 ;
		RECT	0 10.035 0.32 10.465 ;
		RECT	0 10.665 0.32 10.995 ;
		RECT	0 11.195 0.32 11.625 ;
		RECT	0 11.825 0.32 12.675 ;
		RECT	0 12.875 0.32 13.305 ;
		RECT	0 13.505 0.32 13.835 ;
		RECT	0 14.035 0.32 14.465 ;
		RECT	0 14.665 0.32 15.515 ;
		RECT	0 15.715 0.32 16.145 ;
		RECT	0 16.345 0.32 16.675 ;
		RECT	0 16.875 0.32 17.305 ;
		RECT	0 17.505 0.32 18.355 ;
		RECT	0 18.555 0.32 18.985 ;
		RECT	0 19.185 0.32 19.515 ;
		RECT	0 19.715 0.32 20.145 ;
		RECT	0 20.345 0.32 21.195 ;
		RECT	0 21.395 0.32 21.825 ;
		RECT	0 22.025 0.32 22.355 ;
		RECT	0 22.555 0.32 22.985 ;
		RECT	0 23.185 0.32 24.035 ;
		RECT	0 24.235 0.32 24.665 ;
		RECT	0 24.865 0.32 25.195 ;
		RECT	0 25.395 0.32 25.825 ;
		RECT	0 26.025 0.32 26.875 ;
		RECT	0 27.075 0.32 27.505 ;
		RECT	0 27.705 0.32 28.035 ;
		RECT	0 28.235 0.32 28.665 ;
		RECT	0 28.865 0.32 29.715 ;
		RECT	0 29.915 0.32 30.345 ;
		RECT	0 30.545 0.32 30.875 ;
		RECT	0 31.075 0.32 31.505 ;
		RECT	0 31.705 0.32 32.555 ;
		RECT	0 32.755 0.32 33.185 ;
		RECT	0 33.385 0.32 33.715 ;
		RECT	0 33.915 0.32 34.345 ;
		RECT	0 34.545 0.32 35.395 ;
		RECT	0 35.595 0.32 36.025 ;
		RECT	0 36.225 0.32 36.555 ;
		RECT	0 36.755 0.32 37.185 ;
		RECT	0 37.385 0.32 38.235 ;
		RECT	0 38.435 0.32 38.865 ;
		RECT	0 39.065 0.32 39.395 ;
		RECT	0 39.595 0.32 40.025 ;
		RECT	0 40.225 0.32 41.075 ;
		RECT	0 41.275 0.32 41.705 ;
		RECT	0 41.905 0.32 42.235 ;
		RECT	0 42.435 0.32 42.865 ;
		RECT	0 43.065 0.32 43.915 ;
		RECT	0 44.115 0.32 44.545 ;
		RECT	0 44.745 0.32 45.075 ;
		RECT	0 45.275 0.32 45.705 ;
		RECT	0 45.905 0.32 46.755 ;
		RECT	0 46.955 0.32 47.385 ;
		RECT	0 47.585 0.32 47.915 ;
		RECT	0 48.115 0.32 48.545 ;
		RECT	0 48.745 0.32 49.595 ;
		RECT	0 49.795 0.32 50.225 ;
		RECT	0 50.425 0.32 50.755 ;
		RECT	0 50.955 0.32 51.385 ;
		RECT	0 51.585 0.32 52.435 ;
		RECT	0 52.635 0.32 53.065 ;
		RECT	0 53.265 0.32 53.595 ;
		RECT	0 53.795 0.32 54.225 ;
		RECT	0 54.425 0.32 55.275 ;
		RECT	0 55.475 0.32 55.905 ;
		RECT	0 56.105 0.32 56.435 ;
		RECT	0 56.635 0.32 57.065 ;
		RECT	0 57.265 0.32 58.115 ;
		RECT	0 58.315 0.32 58.745 ;
		RECT	0 58.945 0.32 59.275 ;
		RECT	0 59.475 0.32 59.905 ;
		RECT	0 60.105 0.32 60.955 ;
		RECT	0 61.155 0.32 61.585 ;
		RECT	0 61.785 0.32 62.115 ;
		RECT	0 62.315 0.32 62.745 ;
		RECT	0 62.945 0.32 63.795 ;
		RECT	0 63.995 0.32 64.425 ;
		RECT	0 64.625 0.32 64.955 ;
		RECT	0 65.155 0.32 65.585 ;
		RECT	0 65.785 0.32 66.635 ;
		RECT	0 66.835 0.32 67.265 ;
		RECT	0 67.465 0.32 67.795 ;
		RECT	0 67.995 0.32 68.425 ;
		RECT	0 68.625 0.32 69.475 ;
		RECT	0 69.675 0.32 70.105 ;
		RECT	0 70.305 0.32 70.635 ;
		RECT	0 70.835 0.32 71.265 ;
		RECT	0 71.465 0.32 72.315 ;
		RECT	0 72.515 0.32 72.945 ;
		RECT	0 73.145 0.32 73.475 ;
		RECT	0 73.675 0.32 74.105 ;
		RECT	0 74.305 0.32 75.155 ;
		RECT	0 75.355 0.32 75.785 ;
		RECT	0 75.985 0.32 76.315 ;
		RECT	0 76.515 0.32 76.945 ;
		RECT	0 77.145 0.32 77.995 ;
		RECT	0 78.195 0.32 78.625 ;
		RECT	0 78.825 0.32 79.155 ;
		RECT	0 79.355 0.32 79.785 ;
		RECT	0 79.985 0.32 80.835 ;
		RECT	0 81.035 0.32 81.465 ;
		RECT	0 81.665 0.32 81.995 ;
		RECT	0 82.195 0.32 82.625 ;
		RECT	0 82.825 0.32 83.675 ;
		RECT	0 83.875 0.32 84.305 ;
		RECT	0 84.505 0.32 84.835 ;
		RECT	0 85.035 0.32 85.465 ;
		RECT	0 85.665 0.32 86.515 ;
		RECT	0 86.715 0.32 87.145 ;
		RECT	0 87.345 0.32 87.675 ;
		RECT	0 87.875 0.32 88.305 ;
		RECT	0 88.505 0.32 89.355 ;
		RECT	0 89.555 0.32 89.985 ;
		RECT	0 90.185 0.32 90.515 ;
		RECT	0 90.715 0.32 91.145 ;
		RECT	0 91.345 0.32 94.015 ;
		RECT	0 94.215 0.32 96.46 ;
		RECT	0 96.66 0.32 96.85 ;
		RECT	0 97.05 0.32 97.975 ;
		RECT	0 98.175 0.32 98.47 ;
		RECT	0 98.67 0.32 98.77 ;
		RECT	0 98.97 0.32 99.02 ;
		RECT	0 99.22 0.32 99.84 ;
		RECT	0 100.04 0.32 100.44 ;
		RECT	0 100.64 0.32 100.84 ;
		RECT	0 101.04 0.32 102.75 ;
		RECT	0 102.95 0.32 103.08 ;
		RECT	0 103.28 0.32 104.445 ;
		RECT	0 104.645 0.32 105.185 ;
		RECT	0 105.385 0.32 105.655 ;
		RECT	0 106.255 0.32 106.455 ;
		RECT	0 106.655 0.32 109.415 ;
		RECT	0 109.615 0.32 112.335 ;
		RECT	0 112.535 0.32 112.71 ;
		RECT	0 113.13 0.32 114.68 ;
		RECT	0 114.88 0.32 115.31 ;
		RECT	0 115.51 0.32 115.84 ;
		RECT	0 116.04 0.32 116.47 ;
		RECT	0 116.67 0.32 117.52 ;
		RECT	0 117.72 0.32 118.15 ;
		RECT	0 118.35 0.32 118.68 ;
		RECT	0 118.88 0.32 119.31 ;
		RECT	0 119.51 0.32 120.36 ;
		RECT	0 120.56 0.32 120.99 ;
		RECT	0 121.19 0.32 121.52 ;
		RECT	0 121.72 0.32 122.15 ;
		RECT	0 122.35 0.32 123.2 ;
		RECT	0 123.4 0.32 123.83 ;
		RECT	0 124.03 0.32 124.36 ;
		RECT	0 124.56 0.32 124.99 ;
		RECT	0 125.19 0.32 126.04 ;
		RECT	0 126.24 0.32 126.67 ;
		RECT	0 126.87 0.32 127.2 ;
		RECT	0 127.4 0.32 127.83 ;
		RECT	0 128.03 0.32 128.88 ;
		RECT	0 129.08 0.32 129.51 ;
		RECT	0 129.71 0.32 130.04 ;
		RECT	0 130.24 0.32 130.67 ;
		RECT	0 130.87 0.32 131.72 ;
		RECT	0 131.92 0.32 132.35 ;
		RECT	0 132.55 0.32 132.88 ;
		RECT	0 133.08 0.32 133.51 ;
		RECT	0 133.71 0.32 134.56 ;
		RECT	0 134.76 0.32 135.19 ;
		RECT	0 135.39 0.32 135.72 ;
		RECT	0 135.92 0.32 136.35 ;
		RECT	0 136.55 0.32 137.4 ;
		RECT	0 137.6 0.32 138.03 ;
		RECT	0 138.23 0.32 138.56 ;
		RECT	0 138.76 0.32 139.19 ;
		RECT	0 139.39 0.32 140.24 ;
		RECT	0 140.44 0.32 140.87 ;
		RECT	0 141.07 0.32 141.4 ;
		RECT	0 141.6 0.32 142.03 ;
		RECT	0 142.23 0.32 143.08 ;
		RECT	0 143.28 0.32 143.71 ;
		RECT	0 143.91 0.32 144.24 ;
		RECT	0 144.44 0.32 144.87 ;
		RECT	0 145.07 0.32 145.92 ;
		RECT	0 146.12 0.32 146.55 ;
		RECT	0 146.75 0.32 147.08 ;
		RECT	0 147.28 0.32 147.71 ;
		RECT	0 147.91 0.32 148.76 ;
		RECT	0 148.96 0.32 149.39 ;
		RECT	0 149.59 0.32 149.92 ;
		RECT	0 150.12 0.32 150.55 ;
		RECT	0 150.75 0.32 151.6 ;
		RECT	0 151.8 0.32 152.23 ;
		RECT	0 152.43 0.32 152.76 ;
		RECT	0 152.96 0.32 153.39 ;
		RECT	0 153.59 0.32 154.44 ;
		RECT	0 154.64 0.32 155.07 ;
		RECT	0 155.27 0.32 155.6 ;
		RECT	0 155.8 0.32 156.23 ;
		RECT	0 156.43 0.32 157.28 ;
		RECT	0 157.48 0.32 157.91 ;
		RECT	0 158.11 0.32 158.44 ;
		RECT	0 158.64 0.32 159.07 ;
		RECT	0 159.27 0.32 160.12 ;
		RECT	0 160.32 0.32 160.75 ;
		RECT	0 160.95 0.32 161.28 ;
		RECT	0 161.48 0.32 161.91 ;
		RECT	0 162.11 0.32 162.96 ;
		RECT	0 163.16 0.32 163.59 ;
		RECT	0 163.79 0.32 164.12 ;
		RECT	0 164.32 0.32 164.75 ;
		RECT	0 164.95 0.32 165.8 ;
		RECT	0 166 0.32 166.43 ;
		RECT	0 166.63 0.32 166.96 ;
		RECT	0 167.16 0.32 167.59 ;
		RECT	0 167.79 0.32 168.64 ;
		RECT	0 168.84 0.32 169.27 ;
		RECT	0 169.47 0.32 169.8 ;
		RECT	0 170 0.32 170.43 ;
		RECT	0 170.63 0.32 171.48 ;
		RECT	0 171.68 0.32 172.11 ;
		RECT	0 172.31 0.32 172.64 ;
		RECT	0 172.84 0.32 173.27 ;
		RECT	0 173.47 0.32 174.32 ;
		RECT	0 174.52 0.32 174.95 ;
		RECT	0 175.15 0.32 175.48 ;
		RECT	0 175.68 0.32 176.11 ;
		RECT	0 176.31 0.32 177.16 ;
		RECT	0 177.36 0.32 177.79 ;
		RECT	0 177.99 0.32 178.32 ;
		RECT	0 178.52 0.32 178.95 ;
		RECT	0 179.15 0.32 180 ;
		RECT	0 180.2 0.32 180.63 ;
		RECT	0 180.83 0.32 181.16 ;
		RECT	0 181.36 0.32 181.79 ;
		RECT	0 181.99 0.32 182.84 ;
		RECT	0 183.04 0.32 183.47 ;
		RECT	0 183.67 0.32 184 ;
		RECT	0 184.2 0.32 184.63 ;
		RECT	0 184.83 0.32 185.68 ;
		RECT	0 185.88 0.32 186.31 ;
		RECT	0 186.51 0.32 186.84 ;
		RECT	0 187.04 0.32 187.47 ;
		RECT	0 187.67 0.32 188.52 ;
		RECT	0 188.72 0.32 189.15 ;
		RECT	0 189.35 0.32 189.68 ;
		RECT	0 189.88 0.32 190.31 ;
		RECT	0 190.51 0.32 191.36 ;
		RECT	0 191.56 0.32 191.99 ;
		RECT	0 192.19 0.32 192.52 ;
		RECT	0 192.72 0.32 193.15 ;
		RECT	0 193.35 0.32 194.2 ;
		RECT	0 194.4 0.32 194.83 ;
		RECT	0 195.03 0.32 195.36 ;
		RECT	0 195.56 0.32 195.99 ;
		RECT	0 196.19 0.32 197.04 ;
		RECT	0 197.24 0.32 197.67 ;
		RECT	0 197.87 0.32 198.2 ;
		RECT	0 198.4 0.32 198.83 ;
		RECT	0 199.03 0.32 199.88 ;
		RECT	0 200.08 0.32 200.51 ;
		RECT	0 200.71 0.32 201.04 ;
		RECT	0 201.24 0.32 201.67 ;
		RECT	0 201.87 0.32 202.72 ;
		RECT	0 202.92 0.32 203.35 ;
		RECT	0 203.55 0.32 203.88 ;
		RECT	0 204.08 0.32 204.51 ;
		RECT	0 204.71 0.32 206.025 ;
		RECT	38.08 0 38.4 206.025 ;
		RECT	0.32 0 38.08 0.3 ;
		RECT	0.32 205.725 38.08 206.025 ;
		LAYER	M2 DESIGNRULEWIDTH 0.165 ;
		RECT	0.32 0.3 38.08 205.725 ;
		RECT	0 0 0.32 1.315 ;
		RECT	0 1.515 0.32 1.945 ;
		RECT	0 2.145 0.32 2.475 ;
		RECT	0 2.675 0.32 3.105 ;
		RECT	0 3.305 0.32 4.155 ;
		RECT	0 4.355 0.32 4.785 ;
		RECT	0 4.985 0.32 5.315 ;
		RECT	0 5.515 0.32 5.945 ;
		RECT	0 6.145 0.32 6.995 ;
		RECT	0 7.195 0.32 7.625 ;
		RECT	0 7.825 0.32 8.155 ;
		RECT	0 8.355 0.32 8.785 ;
		RECT	0 8.985 0.32 9.835 ;
		RECT	0 10.035 0.32 10.465 ;
		RECT	0 10.665 0.32 10.995 ;
		RECT	0 11.195 0.32 11.625 ;
		RECT	0 11.825 0.32 12.675 ;
		RECT	0 12.875 0.32 13.305 ;
		RECT	0 13.505 0.32 13.835 ;
		RECT	0 14.035 0.32 14.465 ;
		RECT	0 14.665 0.32 15.515 ;
		RECT	0 15.715 0.32 16.145 ;
		RECT	0 16.345 0.32 16.675 ;
		RECT	0 16.875 0.32 17.305 ;
		RECT	0 17.505 0.32 18.355 ;
		RECT	0 18.555 0.32 18.985 ;
		RECT	0 19.185 0.32 19.515 ;
		RECT	0 19.715 0.32 20.145 ;
		RECT	0 20.345 0.32 21.195 ;
		RECT	0 21.395 0.32 21.825 ;
		RECT	0 22.025 0.32 22.355 ;
		RECT	0 22.555 0.32 22.985 ;
		RECT	0 23.185 0.32 24.035 ;
		RECT	0 24.235 0.32 24.665 ;
		RECT	0 24.865 0.32 25.195 ;
		RECT	0 25.395 0.32 25.825 ;
		RECT	0 26.025 0.32 26.875 ;
		RECT	0 27.075 0.32 27.505 ;
		RECT	0 27.705 0.32 28.035 ;
		RECT	0 28.235 0.32 28.665 ;
		RECT	0 28.865 0.32 29.715 ;
		RECT	0 29.915 0.32 30.345 ;
		RECT	0 30.545 0.32 30.875 ;
		RECT	0 31.075 0.32 31.505 ;
		RECT	0 31.705 0.32 32.555 ;
		RECT	0 32.755 0.32 33.185 ;
		RECT	0 33.385 0.32 33.715 ;
		RECT	0 33.915 0.32 34.345 ;
		RECT	0 34.545 0.32 35.395 ;
		RECT	0 35.595 0.32 36.025 ;
		RECT	0 36.225 0.32 36.555 ;
		RECT	0 36.755 0.32 37.185 ;
		RECT	0 37.385 0.32 38.235 ;
		RECT	0 38.435 0.32 38.865 ;
		RECT	0 39.065 0.32 39.395 ;
		RECT	0 39.595 0.32 40.025 ;
		RECT	0 40.225 0.32 41.075 ;
		RECT	0 41.275 0.32 41.705 ;
		RECT	0 41.905 0.32 42.235 ;
		RECT	0 42.435 0.32 42.865 ;
		RECT	0 43.065 0.32 43.915 ;
		RECT	0 44.115 0.32 44.545 ;
		RECT	0 44.745 0.32 45.075 ;
		RECT	0 45.275 0.32 45.705 ;
		RECT	0 45.905 0.32 46.755 ;
		RECT	0 46.955 0.32 47.385 ;
		RECT	0 47.585 0.32 47.915 ;
		RECT	0 48.115 0.32 48.545 ;
		RECT	0 48.745 0.32 49.595 ;
		RECT	0 49.795 0.32 50.225 ;
		RECT	0 50.425 0.32 50.755 ;
		RECT	0 50.955 0.32 51.385 ;
		RECT	0 51.585 0.32 52.435 ;
		RECT	0 52.635 0.32 53.065 ;
		RECT	0 53.265 0.32 53.595 ;
		RECT	0 53.795 0.32 54.225 ;
		RECT	0 54.425 0.32 55.275 ;
		RECT	0 55.475 0.32 55.905 ;
		RECT	0 56.105 0.32 56.435 ;
		RECT	0 56.635 0.32 57.065 ;
		RECT	0 57.265 0.32 58.115 ;
		RECT	0 58.315 0.32 58.745 ;
		RECT	0 58.945 0.32 59.275 ;
		RECT	0 59.475 0.32 59.905 ;
		RECT	0 60.105 0.32 60.955 ;
		RECT	0 61.155 0.32 61.585 ;
		RECT	0 61.785 0.32 62.115 ;
		RECT	0 62.315 0.32 62.745 ;
		RECT	0 62.945 0.32 63.795 ;
		RECT	0 63.995 0.32 64.425 ;
		RECT	0 64.625 0.32 64.955 ;
		RECT	0 65.155 0.32 65.585 ;
		RECT	0 65.785 0.32 66.635 ;
		RECT	0 66.835 0.32 67.265 ;
		RECT	0 67.465 0.32 67.795 ;
		RECT	0 67.995 0.32 68.425 ;
		RECT	0 68.625 0.32 69.475 ;
		RECT	0 69.675 0.32 70.105 ;
		RECT	0 70.305 0.32 70.635 ;
		RECT	0 70.835 0.32 71.265 ;
		RECT	0 71.465 0.32 72.315 ;
		RECT	0 72.515 0.32 72.945 ;
		RECT	0 73.145 0.32 73.475 ;
		RECT	0 73.675 0.32 74.105 ;
		RECT	0 74.305 0.32 75.155 ;
		RECT	0 75.355 0.32 75.785 ;
		RECT	0 75.985 0.32 76.315 ;
		RECT	0 76.515 0.32 76.945 ;
		RECT	0 77.145 0.32 77.995 ;
		RECT	0 78.195 0.32 78.625 ;
		RECT	0 78.825 0.32 79.155 ;
		RECT	0 79.355 0.32 79.785 ;
		RECT	0 79.985 0.32 80.835 ;
		RECT	0 81.035 0.32 81.465 ;
		RECT	0 81.665 0.32 81.995 ;
		RECT	0 82.195 0.32 82.625 ;
		RECT	0 82.825 0.32 83.675 ;
		RECT	0 83.875 0.32 84.305 ;
		RECT	0 84.505 0.32 84.835 ;
		RECT	0 85.035 0.32 85.465 ;
		RECT	0 85.665 0.32 86.515 ;
		RECT	0 86.715 0.32 87.145 ;
		RECT	0 87.345 0.32 87.675 ;
		RECT	0 87.875 0.32 88.305 ;
		RECT	0 88.505 0.32 89.355 ;
		RECT	0 89.555 0.32 89.985 ;
		RECT	0 90.185 0.32 90.515 ;
		RECT	0 90.715 0.32 91.145 ;
		RECT	0 91.345 0.32 94.015 ;
		RECT	0 94.215 0.32 96.46 ;
		RECT	0 96.66 0.32 96.85 ;
		RECT	0 97.05 0.32 97.975 ;
		RECT	0 98.175 0.32 98.47 ;
		RECT	0 98.67 0.32 98.77 ;
		RECT	0 98.97 0.32 99.02 ;
		RECT	0 99.22 0.32 99.645 ;
		RECT	0 100.04 0.32 100.44 ;
		RECT	0 100.64 0.32 100.84 ;
		RECT	0 101.04 0.32 102.75 ;
		RECT	0 102.95 0.32 103.08 ;
		RECT	0 103.28 0.32 104.445 ;
		RECT	0 104.645 0.32 105.185 ;
		RECT	0 105.385 0.32 105.655 ;
		RECT	0 106.255 0.32 106.455 ;
		RECT	0 106.655 0.32 109.415 ;
		RECT	0 109.615 0.32 112.335 ;
		RECT	0 112.535 0.32 112.71 ;
		RECT	0 113.13 0.32 114.68 ;
		RECT	0 114.88 0.32 115.31 ;
		RECT	0 115.51 0.32 115.84 ;
		RECT	0 116.04 0.32 116.47 ;
		RECT	0 116.67 0.32 117.52 ;
		RECT	0 117.72 0.32 118.15 ;
		RECT	0 118.35 0.32 118.68 ;
		RECT	0 118.88 0.32 119.31 ;
		RECT	0 119.51 0.32 120.36 ;
		RECT	0 120.56 0.32 120.99 ;
		RECT	0 121.19 0.32 121.52 ;
		RECT	0 121.72 0.32 122.15 ;
		RECT	0 122.35 0.32 123.2 ;
		RECT	0 123.4 0.32 123.83 ;
		RECT	0 124.03 0.32 124.36 ;
		RECT	0 124.56 0.32 124.99 ;
		RECT	0 125.19 0.32 126.04 ;
		RECT	0 126.24 0.32 126.67 ;
		RECT	0 126.87 0.32 127.2 ;
		RECT	0 127.4 0.32 127.83 ;
		RECT	0 128.03 0.32 128.88 ;
		RECT	0 129.08 0.32 129.51 ;
		RECT	0 129.71 0.32 130.04 ;
		RECT	0 130.24 0.32 130.67 ;
		RECT	0 130.87 0.32 131.72 ;
		RECT	0 131.92 0.32 132.35 ;
		RECT	0 132.55 0.32 132.88 ;
		RECT	0 133.08 0.32 133.51 ;
		RECT	0 133.71 0.32 134.56 ;
		RECT	0 134.76 0.32 135.19 ;
		RECT	0 135.39 0.32 135.72 ;
		RECT	0 135.92 0.32 136.35 ;
		RECT	0 136.55 0.32 137.4 ;
		RECT	0 137.6 0.32 138.03 ;
		RECT	0 138.23 0.32 138.56 ;
		RECT	0 138.76 0.32 139.19 ;
		RECT	0 139.39 0.32 140.24 ;
		RECT	0 140.44 0.32 140.87 ;
		RECT	0 141.07 0.32 141.4 ;
		RECT	0 141.6 0.32 142.03 ;
		RECT	0 142.23 0.32 143.08 ;
		RECT	0 143.28 0.32 143.71 ;
		RECT	0 143.91 0.32 144.24 ;
		RECT	0 144.44 0.32 144.87 ;
		RECT	0 145.07 0.32 145.92 ;
		RECT	0 146.12 0.32 146.55 ;
		RECT	0 146.75 0.32 147.08 ;
		RECT	0 147.28 0.32 147.71 ;
		RECT	0 147.91 0.32 148.76 ;
		RECT	0 148.96 0.32 149.39 ;
		RECT	0 149.59 0.32 149.92 ;
		RECT	0 150.12 0.32 150.55 ;
		RECT	0 150.75 0.32 151.6 ;
		RECT	0 151.8 0.32 152.23 ;
		RECT	0 152.43 0.32 152.76 ;
		RECT	0 152.96 0.32 153.39 ;
		RECT	0 153.59 0.32 154.44 ;
		RECT	0 154.64 0.32 155.07 ;
		RECT	0 155.27 0.32 155.6 ;
		RECT	0 155.8 0.32 156.23 ;
		RECT	0 156.43 0.32 157.28 ;
		RECT	0 157.48 0.32 157.91 ;
		RECT	0 158.11 0.32 158.44 ;
		RECT	0 158.64 0.32 159.07 ;
		RECT	0 159.27 0.32 160.12 ;
		RECT	0 160.32 0.32 160.75 ;
		RECT	0 160.95 0.32 161.28 ;
		RECT	0 161.48 0.32 161.91 ;
		RECT	0 162.11 0.32 162.96 ;
		RECT	0 163.16 0.32 163.59 ;
		RECT	0 163.79 0.32 164.12 ;
		RECT	0 164.32 0.32 164.75 ;
		RECT	0 164.95 0.32 165.8 ;
		RECT	0 166 0.32 166.43 ;
		RECT	0 166.63 0.32 166.96 ;
		RECT	0 167.16 0.32 167.59 ;
		RECT	0 167.79 0.32 168.64 ;
		RECT	0 168.84 0.32 169.27 ;
		RECT	0 169.47 0.32 169.8 ;
		RECT	0 170 0.32 170.43 ;
		RECT	0 170.63 0.32 171.48 ;
		RECT	0 171.68 0.32 172.11 ;
		RECT	0 172.31 0.32 172.64 ;
		RECT	0 172.84 0.32 173.27 ;
		RECT	0 173.47 0.32 174.32 ;
		RECT	0 174.52 0.32 174.95 ;
		RECT	0 175.15 0.32 175.48 ;
		RECT	0 175.68 0.32 176.11 ;
		RECT	0 176.31 0.32 177.16 ;
		RECT	0 177.36 0.32 177.79 ;
		RECT	0 177.99 0.32 178.32 ;
		RECT	0 178.52 0.32 178.95 ;
		RECT	0 179.15 0.32 180 ;
		RECT	0 180.2 0.32 180.63 ;
		RECT	0 180.83 0.32 181.16 ;
		RECT	0 181.36 0.32 181.79 ;
		RECT	0 181.99 0.32 182.84 ;
		RECT	0 183.04 0.32 183.47 ;
		RECT	0 183.67 0.32 184 ;
		RECT	0 184.2 0.32 184.63 ;
		RECT	0 184.83 0.32 185.68 ;
		RECT	0 185.88 0.32 186.31 ;
		RECT	0 186.51 0.32 186.84 ;
		RECT	0 187.04 0.32 187.47 ;
		RECT	0 187.67 0.32 188.52 ;
		RECT	0 188.72 0.32 189.15 ;
		RECT	0 189.35 0.32 189.68 ;
		RECT	0 189.88 0.32 190.31 ;
		RECT	0 190.51 0.32 191.36 ;
		RECT	0 191.56 0.32 191.99 ;
		RECT	0 192.19 0.32 192.52 ;
		RECT	0 192.72 0.32 193.15 ;
		RECT	0 193.35 0.32 194.2 ;
		RECT	0 194.4 0.32 194.83 ;
		RECT	0 195.03 0.32 195.36 ;
		RECT	0 195.56 0.32 195.99 ;
		RECT	0 196.19 0.32 197.04 ;
		RECT	0 197.24 0.32 197.67 ;
		RECT	0 197.87 0.32 198.2 ;
		RECT	0 198.4 0.32 198.83 ;
		RECT	0 199.03 0.32 199.88 ;
		RECT	0 200.08 0.32 200.51 ;
		RECT	0 200.71 0.32 201.04 ;
		RECT	0 201.24 0.32 201.67 ;
		RECT	0 201.87 0.32 202.72 ;
		RECT	0 202.92 0.32 203.35 ;
		RECT	0 203.55 0.32 203.88 ;
		RECT	0 204.08 0.32 204.51 ;
		RECT	0 204.71 0.32 206.025 ;
		RECT	38.08 0 38.4 206.025 ;
		RECT	0.32 0 38.08 0.3 ;
		RECT	0.32 205.725 38.08 206.025 ;
		LAYER	M3 DESIGNRULEWIDTH 0.165 ;
		RECT	0.32 0.3 38.08 205.725 ;
		RECT	0 0 0.32 1.315 ;
		RECT	0 1.515 0.32 1.945 ;
		RECT	0 2.145 0.32 2.475 ;
		RECT	0 2.675 0.32 3.105 ;
		RECT	0 3.305 0.32 4.155 ;
		RECT	0 4.355 0.32 4.785 ;
		RECT	0 4.985 0.32 5.315 ;
		RECT	0 5.515 0.32 5.945 ;
		RECT	0 6.145 0.32 6.995 ;
		RECT	0 7.195 0.32 7.625 ;
		RECT	0 7.825 0.32 8.155 ;
		RECT	0 8.355 0.32 8.785 ;
		RECT	0 8.985 0.32 9.835 ;
		RECT	0 10.035 0.32 10.465 ;
		RECT	0 10.665 0.32 10.995 ;
		RECT	0 11.195 0.32 11.625 ;
		RECT	0 11.825 0.32 12.675 ;
		RECT	0 12.875 0.32 13.305 ;
		RECT	0 13.505 0.32 13.835 ;
		RECT	0 14.035 0.32 14.465 ;
		RECT	0 14.665 0.32 15.515 ;
		RECT	0 15.715 0.32 16.145 ;
		RECT	0 16.345 0.32 16.675 ;
		RECT	0 16.875 0.32 17.305 ;
		RECT	0 17.505 0.32 18.355 ;
		RECT	0 18.555 0.32 18.985 ;
		RECT	0 19.185 0.32 19.515 ;
		RECT	0 19.715 0.32 20.145 ;
		RECT	0 20.345 0.32 21.195 ;
		RECT	0 21.395 0.32 21.825 ;
		RECT	0 22.025 0.32 22.355 ;
		RECT	0 22.555 0.32 22.985 ;
		RECT	0 23.185 0.32 24.035 ;
		RECT	0 24.235 0.32 24.665 ;
		RECT	0 24.865 0.32 25.195 ;
		RECT	0 25.395 0.32 25.825 ;
		RECT	0 26.025 0.32 26.875 ;
		RECT	0 27.075 0.32 27.505 ;
		RECT	0 27.705 0.32 28.035 ;
		RECT	0 28.235 0.32 28.665 ;
		RECT	0 28.865 0.32 29.715 ;
		RECT	0 29.915 0.32 30.345 ;
		RECT	0 30.545 0.32 30.875 ;
		RECT	0 31.075 0.32 31.505 ;
		RECT	0 31.705 0.32 32.555 ;
		RECT	0 32.755 0.32 33.185 ;
		RECT	0 33.385 0.32 33.715 ;
		RECT	0 33.915 0.32 34.345 ;
		RECT	0 34.545 0.32 35.395 ;
		RECT	0 35.595 0.32 36.025 ;
		RECT	0 36.225 0.32 36.555 ;
		RECT	0 36.755 0.32 37.185 ;
		RECT	0 37.385 0.32 38.235 ;
		RECT	0 38.435 0.32 38.865 ;
		RECT	0 39.065 0.32 39.395 ;
		RECT	0 39.595 0.32 40.025 ;
		RECT	0 40.225 0.32 41.075 ;
		RECT	0 41.275 0.32 41.705 ;
		RECT	0 41.905 0.32 42.235 ;
		RECT	0 42.435 0.32 42.865 ;
		RECT	0 43.065 0.32 43.915 ;
		RECT	0 44.115 0.32 44.545 ;
		RECT	0 44.745 0.32 45.075 ;
		RECT	0 45.275 0.32 45.705 ;
		RECT	0 45.905 0.32 46.755 ;
		RECT	0 46.955 0.32 47.385 ;
		RECT	0 47.585 0.32 47.915 ;
		RECT	0 48.115 0.32 48.545 ;
		RECT	0 48.745 0.32 49.595 ;
		RECT	0 49.795 0.32 50.225 ;
		RECT	0 50.425 0.32 50.755 ;
		RECT	0 50.955 0.32 51.385 ;
		RECT	0 51.585 0.32 52.435 ;
		RECT	0 52.635 0.32 53.065 ;
		RECT	0 53.265 0.32 53.595 ;
		RECT	0 53.795 0.32 54.225 ;
		RECT	0 54.425 0.32 55.275 ;
		RECT	0 55.475 0.32 55.905 ;
		RECT	0 56.105 0.32 56.435 ;
		RECT	0 56.635 0.32 57.065 ;
		RECT	0 57.265 0.32 58.115 ;
		RECT	0 58.315 0.32 58.745 ;
		RECT	0 58.945 0.32 59.275 ;
		RECT	0 59.475 0.32 59.905 ;
		RECT	0 60.105 0.32 60.955 ;
		RECT	0 61.155 0.32 61.585 ;
		RECT	0 61.785 0.32 62.115 ;
		RECT	0 62.315 0.32 62.745 ;
		RECT	0 62.945 0.32 63.795 ;
		RECT	0 63.995 0.32 64.425 ;
		RECT	0 64.625 0.32 64.955 ;
		RECT	0 65.155 0.32 65.585 ;
		RECT	0 65.785 0.32 66.635 ;
		RECT	0 66.835 0.32 67.265 ;
		RECT	0 67.465 0.32 67.795 ;
		RECT	0 67.995 0.32 68.425 ;
		RECT	0 68.625 0.32 69.475 ;
		RECT	0 69.675 0.32 70.105 ;
		RECT	0 70.305 0.32 70.635 ;
		RECT	0 70.835 0.32 71.265 ;
		RECT	0 71.465 0.32 72.315 ;
		RECT	0 72.515 0.32 72.945 ;
		RECT	0 73.145 0.32 73.475 ;
		RECT	0 73.675 0.32 74.105 ;
		RECT	0 74.305 0.32 75.155 ;
		RECT	0 75.355 0.32 75.785 ;
		RECT	0 75.985 0.32 76.315 ;
		RECT	0 76.515 0.32 76.945 ;
		RECT	0 77.145 0.32 77.995 ;
		RECT	0 78.195 0.32 78.625 ;
		RECT	0 78.825 0.32 79.155 ;
		RECT	0 79.355 0.32 79.785 ;
		RECT	0 79.985 0.32 80.835 ;
		RECT	0 81.035 0.32 81.465 ;
		RECT	0 81.665 0.32 81.995 ;
		RECT	0 82.195 0.32 82.625 ;
		RECT	0 82.825 0.32 83.675 ;
		RECT	0 83.875 0.32 84.305 ;
		RECT	0 84.505 0.32 84.835 ;
		RECT	0 85.035 0.32 85.465 ;
		RECT	0 85.665 0.32 86.515 ;
		RECT	0 86.715 0.32 87.145 ;
		RECT	0 87.345 0.32 87.675 ;
		RECT	0 87.875 0.32 88.305 ;
		RECT	0 88.505 0.32 89.355 ;
		RECT	0 89.555 0.32 89.985 ;
		RECT	0 90.185 0.32 90.515 ;
		RECT	0 90.715 0.32 91.145 ;
		RECT	0 91.345 0.32 94.015 ;
		RECT	0 94.215 0.32 96.46 ;
		RECT	0 96.66 0.32 96.85 ;
		RECT	0 97.05 0.32 97.975 ;
		RECT	0 98.175 0.32 98.47 ;
		RECT	0 98.67 0.32 98.77 ;
		RECT	0 98.97 0.32 99.02 ;
		RECT	0 99.22 0.32 99.645 ;
		RECT	0 100.04 0.32 100.44 ;
		RECT	0 100.64 0.32 100.84 ;
		RECT	0 101.04 0.32 102.75 ;
		RECT	0 102.95 0.32 103.08 ;
		RECT	0 103.28 0.32 104.445 ;
		RECT	0 104.645 0.32 105.185 ;
		RECT	0 105.385 0.32 105.655 ;
		RECT	0 106.255 0.32 106.455 ;
		RECT	0 106.655 0.32 109.415 ;
		RECT	0 109.615 0.32 112.335 ;
		RECT	0 112.535 0.32 112.71 ;
		RECT	0 113.13 0.32 114.68 ;
		RECT	0 114.88 0.32 115.31 ;
		RECT	0 115.51 0.32 115.84 ;
		RECT	0 116.04 0.32 116.47 ;
		RECT	0 116.67 0.32 117.52 ;
		RECT	0 117.72 0.32 118.15 ;
		RECT	0 118.35 0.32 118.68 ;
		RECT	0 118.88 0.32 119.31 ;
		RECT	0 119.51 0.32 120.36 ;
		RECT	0 120.56 0.32 120.99 ;
		RECT	0 121.19 0.32 121.52 ;
		RECT	0 121.72 0.32 122.15 ;
		RECT	0 122.35 0.32 123.2 ;
		RECT	0 123.4 0.32 123.83 ;
		RECT	0 124.03 0.32 124.36 ;
		RECT	0 124.56 0.32 124.99 ;
		RECT	0 125.19 0.32 126.04 ;
		RECT	0 126.24 0.32 126.67 ;
		RECT	0 126.87 0.32 127.2 ;
		RECT	0 127.4 0.32 127.83 ;
		RECT	0 128.03 0.32 128.88 ;
		RECT	0 129.08 0.32 129.51 ;
		RECT	0 129.71 0.32 130.04 ;
		RECT	0 130.24 0.32 130.67 ;
		RECT	0 130.87 0.32 131.72 ;
		RECT	0 131.92 0.32 132.35 ;
		RECT	0 132.55 0.32 132.88 ;
		RECT	0 133.08 0.32 133.51 ;
		RECT	0 133.71 0.32 134.56 ;
		RECT	0 134.76 0.32 135.19 ;
		RECT	0 135.39 0.32 135.72 ;
		RECT	0 135.92 0.32 136.35 ;
		RECT	0 136.55 0.32 137.4 ;
		RECT	0 137.6 0.32 138.03 ;
		RECT	0 138.23 0.32 138.56 ;
		RECT	0 138.76 0.32 139.19 ;
		RECT	0 139.39 0.32 140.24 ;
		RECT	0 140.44 0.32 140.87 ;
		RECT	0 141.07 0.32 141.4 ;
		RECT	0 141.6 0.32 142.03 ;
		RECT	0 142.23 0.32 143.08 ;
		RECT	0 143.28 0.32 143.71 ;
		RECT	0 143.91 0.32 144.24 ;
		RECT	0 144.44 0.32 144.87 ;
		RECT	0 145.07 0.32 145.92 ;
		RECT	0 146.12 0.32 146.55 ;
		RECT	0 146.75 0.32 147.08 ;
		RECT	0 147.28 0.32 147.71 ;
		RECT	0 147.91 0.32 148.76 ;
		RECT	0 148.96 0.32 149.39 ;
		RECT	0 149.59 0.32 149.92 ;
		RECT	0 150.12 0.32 150.55 ;
		RECT	0 150.75 0.32 151.6 ;
		RECT	0 151.8 0.32 152.23 ;
		RECT	0 152.43 0.32 152.76 ;
		RECT	0 152.96 0.32 153.39 ;
		RECT	0 153.59 0.32 154.44 ;
		RECT	0 154.64 0.32 155.07 ;
		RECT	0 155.27 0.32 155.6 ;
		RECT	0 155.8 0.32 156.23 ;
		RECT	0 156.43 0.32 157.28 ;
		RECT	0 157.48 0.32 157.91 ;
		RECT	0 158.11 0.32 158.44 ;
		RECT	0 158.64 0.32 159.07 ;
		RECT	0 159.27 0.32 160.12 ;
		RECT	0 160.32 0.32 160.75 ;
		RECT	0 160.95 0.32 161.28 ;
		RECT	0 161.48 0.32 161.91 ;
		RECT	0 162.11 0.32 162.96 ;
		RECT	0 163.16 0.32 163.59 ;
		RECT	0 163.79 0.32 164.12 ;
		RECT	0 164.32 0.32 164.75 ;
		RECT	0 164.95 0.32 165.8 ;
		RECT	0 166 0.32 166.43 ;
		RECT	0 166.63 0.32 166.96 ;
		RECT	0 167.16 0.32 167.59 ;
		RECT	0 167.79 0.32 168.64 ;
		RECT	0 168.84 0.32 169.27 ;
		RECT	0 169.47 0.32 169.8 ;
		RECT	0 170 0.32 170.43 ;
		RECT	0 170.63 0.32 171.48 ;
		RECT	0 171.68 0.32 172.11 ;
		RECT	0 172.31 0.32 172.64 ;
		RECT	0 172.84 0.32 173.27 ;
		RECT	0 173.47 0.32 174.32 ;
		RECT	0 174.52 0.32 174.95 ;
		RECT	0 175.15 0.32 175.48 ;
		RECT	0 175.68 0.32 176.11 ;
		RECT	0 176.31 0.32 177.16 ;
		RECT	0 177.36 0.32 177.79 ;
		RECT	0 177.99 0.32 178.32 ;
		RECT	0 178.52 0.32 178.95 ;
		RECT	0 179.15 0.32 180 ;
		RECT	0 180.2 0.32 180.63 ;
		RECT	0 180.83 0.32 181.16 ;
		RECT	0 181.36 0.32 181.79 ;
		RECT	0 181.99 0.32 182.84 ;
		RECT	0 183.04 0.32 183.47 ;
		RECT	0 183.67 0.32 184 ;
		RECT	0 184.2 0.32 184.63 ;
		RECT	0 184.83 0.32 185.68 ;
		RECT	0 185.88 0.32 186.31 ;
		RECT	0 186.51 0.32 186.84 ;
		RECT	0 187.04 0.32 187.47 ;
		RECT	0 187.67 0.32 188.52 ;
		RECT	0 188.72 0.32 189.15 ;
		RECT	0 189.35 0.32 189.68 ;
		RECT	0 189.88 0.32 190.31 ;
		RECT	0 190.51 0.32 191.36 ;
		RECT	0 191.56 0.32 191.99 ;
		RECT	0 192.19 0.32 192.52 ;
		RECT	0 192.72 0.32 193.15 ;
		RECT	0 193.35 0.32 194.2 ;
		RECT	0 194.4 0.32 194.83 ;
		RECT	0 195.03 0.32 195.36 ;
		RECT	0 195.56 0.32 195.99 ;
		RECT	0 196.19 0.32 197.04 ;
		RECT	0 197.24 0.32 197.67 ;
		RECT	0 197.87 0.32 198.2 ;
		RECT	0 198.4 0.32 198.83 ;
		RECT	0 199.03 0.32 199.88 ;
		RECT	0 200.08 0.32 200.51 ;
		RECT	0 200.71 0.32 201.04 ;
		RECT	0 201.24 0.32 201.67 ;
		RECT	0 201.87 0.32 202.72 ;
		RECT	0 202.92 0.32 203.35 ;
		RECT	0 203.55 0.32 203.88 ;
		RECT	0 204.08 0.32 204.51 ;
		RECT	0 204.71 0.32 206.025 ;
		RECT	38.08 0 38.4 206.025 ;
		RECT	0.32 0 38.08 0.3 ;
		RECT	0.32 205.725 38.08 206.025 ;
		LAYER	M4 DESIGNRULEWIDTH 0.165 ;
		RECT	0.32 0 38.08 0.09 ;
		RECT	0 0 0.32 0.09 ;
		RECT	38.08 0 38.4 0.09 ;
		RECT	0.32 0.9 38.08 1.99 ;
		RECT	0 0.9 0.32 1.99 ;
		RECT	38.08 0.9 38.4 1.99 ;
		RECT	0.32 2.76 38.08 2.83 ;
		RECT	0 2.76 0.32 2.83 ;
		RECT	38.08 2.76 38.4 2.83 ;
		RECT	0.32 3.63 38.08 4.83 ;
		RECT	0 3.63 0.32 4.83 ;
		RECT	38.08 3.63 38.4 4.83 ;
		RECT	0.32 5.6 38.08 5.67 ;
		RECT	0 5.6 0.32 5.67 ;
		RECT	38.08 5.6 38.4 5.67 ;
		RECT	0.32 6.47 38.08 7.67 ;
		RECT	0 6.47 0.32 7.67 ;
		RECT	38.08 6.47 38.4 7.67 ;
		RECT	0.32 8.44 38.08 8.51 ;
		RECT	0 8.44 0.32 8.51 ;
		RECT	38.08 8.44 38.4 8.51 ;
		RECT	0.32 9.31 38.08 10.51 ;
		RECT	0 9.31 0.32 10.51 ;
		RECT	38.08 9.31 38.4 10.51 ;
		RECT	0.32 11.28 38.08 11.35 ;
		RECT	0 11.28 0.32 11.35 ;
		RECT	38.08 11.28 38.4 11.35 ;
		RECT	0.32 12.15 38.08 13.35 ;
		RECT	0 12.15 0.32 13.35 ;
		RECT	38.08 12.15 38.4 13.35 ;
		RECT	0.32 14.12 38.08 14.19 ;
		RECT	0 14.12 0.32 14.19 ;
		RECT	38.08 14.12 38.4 14.19 ;
		RECT	0.32 14.99 38.08 16.19 ;
		RECT	0 14.99 0.32 16.19 ;
		RECT	38.08 14.99 38.4 16.19 ;
		RECT	0.32 16.96 38.08 17.03 ;
		RECT	0 16.96 0.32 17.03 ;
		RECT	38.08 16.96 38.4 17.03 ;
		RECT	0.32 17.83 38.08 19.03 ;
		RECT	0 17.83 0.32 19.03 ;
		RECT	38.08 17.83 38.4 19.03 ;
		RECT	0.32 19.8 38.08 19.87 ;
		RECT	0 19.8 0.32 19.87 ;
		RECT	38.08 19.8 38.4 19.87 ;
		RECT	0.32 20.67 38.08 21.87 ;
		RECT	0 20.67 0.32 21.87 ;
		RECT	38.08 20.67 38.4 21.87 ;
		RECT	0.32 22.64 38.08 22.71 ;
		RECT	0 22.64 0.32 22.71 ;
		RECT	38.08 22.64 38.4 22.71 ;
		RECT	0.32 23.51 38.08 24.71 ;
		RECT	0 23.51 0.32 24.71 ;
		RECT	38.08 23.51 38.4 24.71 ;
		RECT	0.32 25.48 38.08 25.55 ;
		RECT	0 25.48 0.32 25.55 ;
		RECT	38.08 25.48 38.4 25.55 ;
		RECT	0.32 26.35 38.08 27.55 ;
		RECT	0 26.35 0.32 27.55 ;
		RECT	38.08 26.35 38.4 27.55 ;
		RECT	0.32 28.32 38.08 28.39 ;
		RECT	0 28.32 0.32 28.39 ;
		RECT	38.08 28.32 38.4 28.39 ;
		RECT	0.32 29.19 38.08 30.39 ;
		RECT	0 29.19 0.32 30.39 ;
		RECT	38.08 29.19 38.4 30.39 ;
		RECT	0.32 31.16 38.08 31.23 ;
		RECT	0 31.16 0.32 31.23 ;
		RECT	38.08 31.16 38.4 31.23 ;
		RECT	0.32 32.03 38.08 33.23 ;
		RECT	0 32.03 0.32 33.23 ;
		RECT	38.08 32.03 38.4 33.23 ;
		RECT	0.32 34 38.08 34.07 ;
		RECT	0 34 0.32 34.07 ;
		RECT	38.08 34 38.4 34.07 ;
		RECT	0.32 34.87 38.08 36.07 ;
		RECT	0 34.87 0.32 36.07 ;
		RECT	38.08 34.87 38.4 36.07 ;
		RECT	0.32 36.84 38.08 36.91 ;
		RECT	0 36.84 0.32 36.91 ;
		RECT	38.08 36.84 38.4 36.91 ;
		RECT	0.32 37.71 38.08 38.91 ;
		RECT	0 37.71 0.32 38.91 ;
		RECT	38.08 37.71 38.4 38.91 ;
		RECT	0.32 39.68 38.08 39.75 ;
		RECT	0 39.68 0.32 39.75 ;
		RECT	38.08 39.68 38.4 39.75 ;
		RECT	0.32 40.55 38.08 41.75 ;
		RECT	0 40.55 0.32 41.75 ;
		RECT	38.08 40.55 38.4 41.75 ;
		RECT	0.32 42.52 38.08 42.59 ;
		RECT	0 42.52 0.32 42.59 ;
		RECT	38.08 42.52 38.4 42.59 ;
		RECT	0.32 43.39 38.08 44.59 ;
		RECT	0 43.39 0.32 44.59 ;
		RECT	38.08 43.39 38.4 44.59 ;
		RECT	0.32 45.36 38.08 45.43 ;
		RECT	0 45.36 0.32 45.43 ;
		RECT	38.08 45.36 38.4 45.43 ;
		RECT	0.32 46.23 38.08 47.43 ;
		RECT	0 46.23 0.32 47.43 ;
		RECT	38.08 46.23 38.4 47.43 ;
		RECT	0.32 48.2 38.08 48.27 ;
		RECT	0 48.2 0.32 48.27 ;
		RECT	38.08 48.2 38.4 48.27 ;
		RECT	0.32 49.07 38.08 50.27 ;
		RECT	0 49.07 0.32 50.27 ;
		RECT	38.08 49.07 38.4 50.27 ;
		RECT	0.32 51.04 38.08 51.11 ;
		RECT	0 51.04 0.32 51.11 ;
		RECT	38.08 51.04 38.4 51.11 ;
		RECT	0.32 51.91 38.08 53.11 ;
		RECT	0 51.91 0.32 53.11 ;
		RECT	38.08 51.91 38.4 53.11 ;
		RECT	0.32 53.88 38.08 53.95 ;
		RECT	0 53.88 0.32 53.95 ;
		RECT	38.08 53.88 38.4 53.95 ;
		RECT	0.32 54.75 38.08 55.95 ;
		RECT	0 54.75 0.32 55.95 ;
		RECT	38.08 54.75 38.4 55.95 ;
		RECT	0.32 56.72 38.08 56.79 ;
		RECT	0 56.72 0.32 56.79 ;
		RECT	38.08 56.72 38.4 56.79 ;
		RECT	0.32 57.59 38.08 58.79 ;
		RECT	0 57.59 0.32 58.79 ;
		RECT	38.08 57.59 38.4 58.79 ;
		RECT	0.32 59.56 38.08 59.63 ;
		RECT	0 59.56 0.32 59.63 ;
		RECT	38.08 59.56 38.4 59.63 ;
		RECT	0.32 60.43 38.08 61.63 ;
		RECT	0 60.43 0.32 61.63 ;
		RECT	38.08 60.43 38.4 61.63 ;
		RECT	0.32 62.4 38.08 62.47 ;
		RECT	0 62.4 0.32 62.47 ;
		RECT	38.08 62.4 38.4 62.47 ;
		RECT	0.32 63.27 38.08 64.47 ;
		RECT	0 63.27 0.32 64.47 ;
		RECT	38.08 63.27 38.4 64.47 ;
		RECT	0.32 65.24 38.08 65.31 ;
		RECT	0 65.24 0.32 65.31 ;
		RECT	38.08 65.24 38.4 65.31 ;
		RECT	0.32 66.11 38.08 67.31 ;
		RECT	0 66.11 0.32 67.31 ;
		RECT	38.08 66.11 38.4 67.31 ;
		RECT	0.32 68.08 38.08 68.15 ;
		RECT	0 68.08 0.32 68.15 ;
		RECT	38.08 68.08 38.4 68.15 ;
		RECT	0.32 68.95 38.08 70.15 ;
		RECT	0 68.95 0.32 70.15 ;
		RECT	38.08 68.95 38.4 70.15 ;
		RECT	0.32 70.92 38.08 70.99 ;
		RECT	0 70.92 0.32 70.99 ;
		RECT	38.08 70.92 38.4 70.99 ;
		RECT	0.32 71.79 38.08 72.99 ;
		RECT	0 71.79 0.32 72.99 ;
		RECT	38.08 71.79 38.4 72.99 ;
		RECT	0.32 73.76 38.08 73.83 ;
		RECT	0 73.76 0.32 73.83 ;
		RECT	38.08 73.76 38.4 73.83 ;
		RECT	0.32 74.63 38.08 75.83 ;
		RECT	0 74.63 0.32 75.83 ;
		RECT	38.08 74.63 38.4 75.83 ;
		RECT	0.32 76.6 38.08 76.67 ;
		RECT	0 76.6 0.32 76.67 ;
		RECT	38.08 76.6 38.4 76.67 ;
		RECT	0.32 77.47 38.08 78.67 ;
		RECT	0 77.47 0.32 78.67 ;
		RECT	38.08 77.47 38.4 78.67 ;
		RECT	0.32 79.44 38.08 79.51 ;
		RECT	0 79.44 0.32 79.51 ;
		RECT	38.08 79.44 38.4 79.51 ;
		RECT	0.32 80.31 38.08 81.51 ;
		RECT	0 80.31 0.32 81.51 ;
		RECT	38.08 80.31 38.4 81.51 ;
		RECT	0.32 82.28 38.08 82.35 ;
		RECT	0 82.28 0.32 82.35 ;
		RECT	38.08 82.28 38.4 82.35 ;
		RECT	0.32 83.15 38.08 84.35 ;
		RECT	0 83.15 0.32 84.35 ;
		RECT	38.08 83.15 38.4 84.35 ;
		RECT	0.32 85.12 38.08 85.19 ;
		RECT	0 85.12 0.32 85.19 ;
		RECT	38.08 85.12 38.4 85.19 ;
		RECT	0.32 85.99 38.08 87.19 ;
		RECT	0 85.99 0.32 87.19 ;
		RECT	38.08 85.99 38.4 87.19 ;
		RECT	0.32 87.96 38.08 88.03 ;
		RECT	0 87.96 0.32 88.03 ;
		RECT	38.08 87.96 38.4 88.03 ;
		RECT	0.32 88.83 38.08 90.03 ;
		RECT	0 88.83 0.32 90.03 ;
		RECT	38.08 88.83 38.4 90.03 ;
		RECT	0.32 90.8 38.08 90.87 ;
		RECT	0 90.8 0.32 90.87 ;
		RECT	38.08 90.8 38.4 90.87 ;
		RECT	0.32 91.67 38.08 92.185 ;
		RECT	0 91.67 0.32 92.185 ;
		RECT	38.08 91.67 38.4 92.185 ;
		RECT	0.32 92.835 38.08 92.93 ;
		RECT	0 92.835 0.32 92.93 ;
		RECT	38.08 92.835 38.4 92.93 ;
		RECT	0.32 93.16 38.08 93.29 ;
		RECT	0 93.16 0.32 93.29 ;
		RECT	38.08 93.16 38.4 93.29 ;
		RECT	0.32 93.7 38.08 94.175 ;
		RECT	0 93.7 0.32 94.175 ;
		RECT	38.08 93.7 38.4 94.175 ;
		RECT	0.32 95.28 38.08 95.615 ;
		RECT	0 95.28 0.32 95.615 ;
		RECT	38.08 95.28 38.4 95.615 ;
		RECT	0.32 96.275 38.08 96.68 ;
		RECT	0 96.275 0.32 96.46 ;
		RECT	38.08 96.275 38.4 96.68 ;
		RECT	0.32 96.99 38.08 97.075 ;
		RECT	0 96.99 0.32 97.075 ;
		RECT	38.08 96.99 38.4 97.075 ;
		RECT	0.32 97.305 38.08 97.785 ;
		RECT	0 97.305 0.32 97.785 ;
		RECT	38.08 97.305 38.4 97.785 ;
		RECT	0.32 98.46 38.08 98.525 ;
		RECT	0 98.46 0.32 98.525 ;
		RECT	38.08 98.46 38.4 98.525 ;
		RECT	0.32 98.935 38.08 99.375 ;
		RECT	0 98.935 0.32 99.375 ;
		RECT	38.08 98.935 38.4 99.375 ;
		RECT	0.32 99.605 38.08 99.94 ;
		RECT	0 99.605 0.32 99.94 ;
		RECT	38.08 99.605 38.4 99.94 ;
		RECT	0.32 100.35 38.08 100.495 ;
		RECT	0 100.35 0.32 100.495 ;
		RECT	38.08 100.35 38.4 100.495 ;
		RECT	0.32 101.415 38.08 102.53 ;
		RECT	0 101.415 0.32 102.53 ;
		RECT	38.08 101.415 38.4 102.53 ;
		RECT	0.32 102.94 38.08 103.5 ;
		RECT	0 102.94 0.32 103.5 ;
		RECT	38.08 102.94 38.4 103.5 ;
		RECT	0.32 103.91 38.08 105.06 ;
		RECT	0 103.91 0.32 105.06 ;
		RECT	38.08 103.91 38.4 105.06 ;
		RECT	0.32 105.68 38.08 105.92 ;
		RECT	0 105.68 0.32 105.92 ;
		RECT	38.08 105.68 38.4 105.92 ;
		RECT	0.32 106.33 38.08 106.64 ;
		RECT	0 106.33 0.32 106.64 ;
		RECT	38.08 106.33 38.4 106.64 ;
		RECT	0.32 106.87 38.08 106.95 ;
		RECT	0 106.87 0.32 106.95 ;
		RECT	38.08 106.87 38.4 106.95 ;
		RECT	0.32 107.36 38.08 107.715 ;
		RECT	0 107.36 0.32 107.715 ;
		RECT	38.08 107.36 38.4 107.715 ;
		RECT	0.32 108.375 38.08 108.555 ;
		RECT	0 108.375 0.32 108.555 ;
		RECT	38.08 108.375 38.4 108.555 ;
		RECT	0.32 108.965 38.08 109.03 ;
		RECT	0 108.965 0.32 109.03 ;
		RECT	38.08 108.965 38.4 109.03 ;
		RECT	0.32 109.44 38.08 109.595 ;
		RECT	0 109.44 0.32 109.595 ;
		RECT	38.08 109.44 38.4 109.595 ;
		RECT	0.32 109.905 38.08 110.295 ;
		RECT	0 109.905 0.32 110.295 ;
		RECT	38.08 109.905 38.4 110.295 ;
		RECT	0.32 110.705 38.08 110.835 ;
		RECT	0 110.705 0.32 110.835 ;
		RECT	38.08 110.705 38.4 110.835 ;
		RECT	0.32 111.065 38.08 111.49 ;
		RECT	0 111.065 0.32 111.49 ;
		RECT	38.08 111.065 38.4 111.49 ;
		RECT	0.32 111.9 38.08 112.01 ;
		RECT	0 111.9 0.32 112.01 ;
		RECT	38.08 111.9 38.4 112.01 ;
		RECT	0.32 112.795 38.08 112.855 ;
		RECT	0 112.795 0.32 112.855 ;
		RECT	38.08 112.795 38.4 112.855 ;
		RECT	0.32 113.51 38.08 113.6 ;
		RECT	0 113.51 0.32 113.6 ;
		RECT	38.08 113.51 38.4 113.6 ;
		RECT	0.32 114.25 38.08 114.355 ;
		RECT	0 114.25 0.32 114.355 ;
		RECT	38.08 114.25 38.4 114.355 ;
		RECT	0.32 115.155 38.08 115.225 ;
		RECT	0 115.155 0.32 115.225 ;
		RECT	38.08 115.155 38.4 115.225 ;
		RECT	0.32 115.995 38.08 117.195 ;
		RECT	0 115.995 0.32 117.195 ;
		RECT	38.08 115.995 38.4 117.195 ;
		RECT	0.32 117.995 38.08 118.065 ;
		RECT	0 117.995 0.32 118.065 ;
		RECT	38.08 117.995 38.4 118.065 ;
		RECT	0.32 118.835 38.08 120.035 ;
		RECT	0 118.835 0.32 120.035 ;
		RECT	38.08 118.835 38.4 120.035 ;
		RECT	0.32 120.835 38.08 120.905 ;
		RECT	0 120.835 0.32 120.905 ;
		RECT	38.08 120.835 38.4 120.905 ;
		RECT	0.32 121.675 38.08 122.875 ;
		RECT	0 121.675 0.32 122.875 ;
		RECT	38.08 121.675 38.4 122.875 ;
		RECT	0.32 123.675 38.08 123.745 ;
		RECT	0 123.675 0.32 123.745 ;
		RECT	38.08 123.675 38.4 123.745 ;
		RECT	0.32 124.515 38.08 125.715 ;
		RECT	0 124.515 0.32 125.715 ;
		RECT	38.08 124.515 38.4 125.715 ;
		RECT	0.32 126.515 38.08 126.585 ;
		RECT	0 126.515 0.32 126.585 ;
		RECT	38.08 126.515 38.4 126.585 ;
		RECT	0.32 127.355 38.08 128.555 ;
		RECT	0 127.355 0.32 128.555 ;
		RECT	38.08 127.355 38.4 128.555 ;
		RECT	0.32 129.355 38.08 129.425 ;
		RECT	0 129.355 0.32 129.425 ;
		RECT	38.08 129.355 38.4 129.425 ;
		RECT	0.32 130.195 38.08 131.395 ;
		RECT	0 130.195 0.32 131.395 ;
		RECT	38.08 130.195 38.4 131.395 ;
		RECT	0.32 132.195 38.08 132.265 ;
		RECT	0 132.195 0.32 132.265 ;
		RECT	38.08 132.195 38.4 132.265 ;
		RECT	0.32 133.035 38.08 134.235 ;
		RECT	0 133.035 0.32 134.235 ;
		RECT	38.08 133.035 38.4 134.235 ;
		RECT	0.32 135.035 38.08 135.105 ;
		RECT	0 135.035 0.32 135.105 ;
		RECT	38.08 135.035 38.4 135.105 ;
		RECT	0.32 135.875 38.08 137.075 ;
		RECT	0 135.875 0.32 137.075 ;
		RECT	38.08 135.875 38.4 137.075 ;
		RECT	0.32 137.875 38.08 137.945 ;
		RECT	0 137.875 0.32 137.945 ;
		RECT	38.08 137.875 38.4 137.945 ;
		RECT	0.32 138.715 38.08 139.915 ;
		RECT	0 138.715 0.32 139.915 ;
		RECT	38.08 138.715 38.4 139.915 ;
		RECT	0.32 140.715 38.08 140.785 ;
		RECT	0 140.715 0.32 140.785 ;
		RECT	38.08 140.715 38.4 140.785 ;
		RECT	0.32 141.555 38.08 142.755 ;
		RECT	0 141.555 0.32 142.755 ;
		RECT	38.08 141.555 38.4 142.755 ;
		RECT	0.32 143.555 38.08 143.625 ;
		RECT	0 143.555 0.32 143.625 ;
		RECT	38.08 143.555 38.4 143.625 ;
		RECT	0.32 144.395 38.08 145.595 ;
		RECT	0 144.395 0.32 145.595 ;
		RECT	38.08 144.395 38.4 145.595 ;
		RECT	0.32 146.395 38.08 146.465 ;
		RECT	0 146.395 0.32 146.465 ;
		RECT	38.08 146.395 38.4 146.465 ;
		RECT	0.32 147.235 38.08 148.435 ;
		RECT	0 147.235 0.32 148.435 ;
		RECT	38.08 147.235 38.4 148.435 ;
		RECT	0.32 149.235 38.08 149.305 ;
		RECT	0 149.235 0.32 149.305 ;
		RECT	38.08 149.235 38.4 149.305 ;
		RECT	0.32 150.075 38.08 151.275 ;
		RECT	0 150.075 0.32 151.275 ;
		RECT	38.08 150.075 38.4 151.275 ;
		RECT	0.32 152.075 38.08 152.145 ;
		RECT	0 152.075 0.32 152.145 ;
		RECT	38.08 152.075 38.4 152.145 ;
		RECT	0.32 152.915 38.08 154.115 ;
		RECT	0 152.915 0.32 154.115 ;
		RECT	38.08 152.915 38.4 154.115 ;
		RECT	0.32 154.915 38.08 154.985 ;
		RECT	0 154.915 0.32 154.985 ;
		RECT	38.08 154.915 38.4 154.985 ;
		RECT	0.32 155.755 38.08 156.955 ;
		RECT	0 155.755 0.32 156.955 ;
		RECT	38.08 155.755 38.4 156.955 ;
		RECT	0.32 157.755 38.08 157.825 ;
		RECT	0 157.755 0.32 157.825 ;
		RECT	38.08 157.755 38.4 157.825 ;
		RECT	0.32 158.595 38.08 159.795 ;
		RECT	0 158.595 0.32 159.795 ;
		RECT	38.08 158.595 38.4 159.795 ;
		RECT	0.32 160.595 38.08 160.665 ;
		RECT	0 160.595 0.32 160.665 ;
		RECT	38.08 160.595 38.4 160.665 ;
		RECT	0.32 161.435 38.08 162.635 ;
		RECT	0 161.435 0.32 162.635 ;
		RECT	38.08 161.435 38.4 162.635 ;
		RECT	0.32 163.435 38.08 163.505 ;
		RECT	0 163.435 0.32 163.505 ;
		RECT	38.08 163.435 38.4 163.505 ;
		RECT	0.32 164.275 38.08 165.475 ;
		RECT	0 164.275 0.32 165.475 ;
		RECT	38.08 164.275 38.4 165.475 ;
		RECT	0.32 166.275 38.08 166.345 ;
		RECT	0 166.275 0.32 166.345 ;
		RECT	38.08 166.275 38.4 166.345 ;
		RECT	0.32 167.115 38.08 168.315 ;
		RECT	0 167.115 0.32 168.315 ;
		RECT	38.08 167.115 38.4 168.315 ;
		RECT	0.32 169.115 38.08 169.185 ;
		RECT	0 169.115 0.32 169.185 ;
		RECT	38.08 169.115 38.4 169.185 ;
		RECT	0.32 169.955 38.08 171.155 ;
		RECT	0 169.955 0.32 171.155 ;
		RECT	38.08 169.955 38.4 171.155 ;
		RECT	0.32 171.955 38.08 172.025 ;
		RECT	0 171.955 0.32 172.025 ;
		RECT	38.08 171.955 38.4 172.025 ;
		RECT	0.32 172.795 38.08 173.995 ;
		RECT	0 172.795 0.32 173.995 ;
		RECT	38.08 172.795 38.4 173.995 ;
		RECT	0.32 174.795 38.08 174.865 ;
		RECT	0 174.795 0.32 174.865 ;
		RECT	38.08 174.795 38.4 174.865 ;
		RECT	0.32 175.635 38.08 176.835 ;
		RECT	0 175.635 0.32 176.835 ;
		RECT	38.08 175.635 38.4 176.835 ;
		RECT	0.32 177.635 38.08 177.705 ;
		RECT	0 177.635 0.32 177.705 ;
		RECT	38.08 177.635 38.4 177.705 ;
		RECT	0.32 178.475 38.08 179.675 ;
		RECT	0 178.475 0.32 179.675 ;
		RECT	38.08 178.475 38.4 179.675 ;
		RECT	0.32 180.475 38.08 180.545 ;
		RECT	0 180.475 0.32 180.545 ;
		RECT	38.08 180.475 38.4 180.545 ;
		RECT	0.32 181.315 38.08 182.515 ;
		RECT	0 181.315 0.32 182.515 ;
		RECT	38.08 181.315 38.4 182.515 ;
		RECT	0.32 183.315 38.08 183.385 ;
		RECT	0 183.315 0.32 183.385 ;
		RECT	38.08 183.315 38.4 183.385 ;
		RECT	0.32 184.155 38.08 185.355 ;
		RECT	0 184.155 0.32 185.355 ;
		RECT	38.08 184.155 38.4 185.355 ;
		RECT	0.32 186.155 38.08 186.225 ;
		RECT	0 186.155 0.32 186.225 ;
		RECT	38.08 186.155 38.4 186.225 ;
		RECT	0.32 186.995 38.08 188.195 ;
		RECT	0 186.995 0.32 188.195 ;
		RECT	38.08 186.995 38.4 188.195 ;
		RECT	0.32 188.995 38.08 189.065 ;
		RECT	0 188.995 0.32 189.065 ;
		RECT	38.08 188.995 38.4 189.065 ;
		RECT	0.32 189.835 38.08 191.035 ;
		RECT	0 189.835 0.32 191.035 ;
		RECT	38.08 189.835 38.4 191.035 ;
		RECT	0.32 191.835 38.08 191.905 ;
		RECT	0 191.835 0.32 191.905 ;
		RECT	38.08 191.835 38.4 191.905 ;
		RECT	0.32 192.675 38.08 193.875 ;
		RECT	0 192.675 0.32 193.875 ;
		RECT	38.08 192.675 38.4 193.875 ;
		RECT	0.32 194.675 38.08 194.745 ;
		RECT	0 194.675 0.32 194.745 ;
		RECT	38.08 194.675 38.4 194.745 ;
		RECT	0.32 195.515 38.08 196.715 ;
		RECT	0 195.515 0.32 196.715 ;
		RECT	38.08 195.515 38.4 196.715 ;
		RECT	0.32 197.515 38.08 197.585 ;
		RECT	0 197.515 0.32 197.585 ;
		RECT	38.08 197.515 38.4 197.585 ;
		RECT	0.32 198.355 38.08 199.555 ;
		RECT	0 198.355 0.32 199.555 ;
		RECT	38.08 198.355 38.4 199.555 ;
		RECT	0.32 200.355 38.08 200.425 ;
		RECT	0 200.355 0.32 200.425 ;
		RECT	38.08 200.355 38.4 200.425 ;
		RECT	0.32 201.195 38.08 202.395 ;
		RECT	0 201.195 0.32 202.395 ;
		RECT	38.08 201.195 38.4 202.395 ;
		RECT	0.32 203.195 38.08 203.265 ;
		RECT	0 203.195 0.32 203.265 ;
		RECT	38.08 203.195 38.4 203.265 ;
		RECT	0.32 204.035 38.08 205.125 ;
		RECT	0 204.035 0.32 205.125 ;
		RECT	38.08 204.035 38.4 205.125 ;
		RECT	0.32 205.935 38.08 206.025 ;
		RECT	0 205.935 0.32 206.025 ;
		RECT	38.08 205.935 38.4 206.025 ;
		LAYER	VIA1 DESIGNRULEWIDTH 0.07 ;
		RECT	0 0 38.4 206.025 ;
		LAYER	VIA2 DESIGNRULEWIDTH 0.07 ;
		RECT	0 0 38.4 206.025 ;
		LAYER	VIA3 DESIGNRULEWIDTH 0.07 ;
		RECT	0 0 38.4 206.025 ;
	END

END sram128x128

END LIBRARY

